VERSION 5.8 ;
BUSBITCHARS "[]" ;
DIVIDERCHAR "/" ;
UNITS
    DATABASE MICRONS 1000 ;
END UNITS

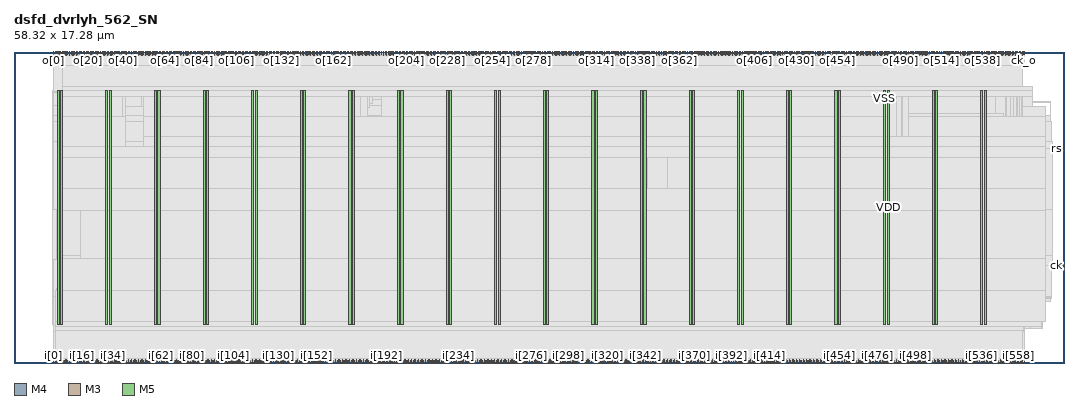
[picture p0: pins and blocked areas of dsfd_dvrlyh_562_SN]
MACRO dsfd_dvrlyh_562_SN
  FOREIGN dsfd_dvrlyh_562_SN 0 0 ;
  CLASS BLOCK ;
  SIZE 58.32 BY 17.28 ;
  PIN ck
    DIRECTION INPUT ;
    USE SIGNAL ;
    PORT
      LAYER M4 ;
        RECT  58.128 5.424 58.32 5.448 ;
    END
  END ck
  PIN ck_o
    DIRECTION OUTPUT ;
    USE SIGNAL ;
    PORT
      LAYER M3 ;
        RECT  56.088 17.136 56.106 17.28 ;
    END
  END ck_o
  PIN i[0]
    DIRECTION INPUT ;
    USE SIGNAL ;
    PORT
      LAYER M3 ;
        RECT  2.196 0 2.214 0.144 ;
    END
  END i[0]
  PIN i[100]
    DIRECTION INPUT ;
    USE SIGNAL ;
    PORT
      LAYER M3 ;
        RECT  11.808 0 11.826 0.144 ;
    END
  END i[100]
  PIN i[101]
    DIRECTION INPUT ;
    USE SIGNAL ;
    PORT
      LAYER M5 ;
        RECT  11.904 0 11.928 0.192 ;
    END
  END i[101]
  PIN i[102]
    DIRECTION INPUT ;
    USE SIGNAL ;
    PORT
      LAYER M3 ;
        RECT  11.988 0 12.006 0.144 ;
    END
  END i[102]
  PIN i[103]
    DIRECTION INPUT ;
    USE SIGNAL ;
    PORT
      LAYER M5 ;
        RECT  12.096 0 12.12 0.192 ;
    END
  END i[103]
  PIN i[104]
    DIRECTION INPUT ;
    USE SIGNAL ;
    PORT
      LAYER M3 ;
        RECT  12.204 0 12.222 0.144 ;
    END
  END i[104]
  PIN i[105]
    DIRECTION INPUT ;
    USE SIGNAL ;
    PORT
      LAYER M5 ;
        RECT  12.288 0 12.312 0.192 ;
    END
  END i[105]
  PIN i[106]
    DIRECTION INPUT ;
    USE SIGNAL ;
    PORT
      LAYER M3 ;
        RECT  12.384 0 12.402 0.144 ;
    END
  END i[106]
  PIN i[107]
    DIRECTION INPUT ;
    USE SIGNAL ;
    PORT
      LAYER M5 ;
        RECT  12.48 0 12.504 0.192 ;
    END
  END i[107]
  PIN i[108]
    DIRECTION INPUT ;
    USE SIGNAL ;
    PORT
      LAYER M3 ;
        RECT  12.564 0 12.582 0.144 ;
    END
  END i[108]
  PIN i[109]
    DIRECTION INPUT ;
    USE SIGNAL ;
    PORT
      LAYER M5 ;
        RECT  12.672 0 12.696 0.192 ;
    END
  END i[109]
  PIN i[10]
    DIRECTION INPUT ;
    USE SIGNAL ;
    PORT
      LAYER M3 ;
        RECT  3.168 0 3.186 0.144 ;
    END
  END i[10]
  PIN i[110]
    DIRECTION INPUT ;
    USE SIGNAL ;
    PORT
      LAYER M3 ;
        RECT  12.78 0 12.798 0.144 ;
    END
  END i[110]
  PIN i[111]
    DIRECTION INPUT ;
    USE SIGNAL ;
    PORT
      LAYER M5 ;
        RECT  12.864 0 12.888 0.192 ;
    END
  END i[111]
  PIN i[112]
    DIRECTION INPUT ;
    USE SIGNAL ;
    PORT
      LAYER M3 ;
        RECT  12.96 0 12.978 0.144 ;
    END
  END i[112]
  PIN i[113]
    DIRECTION INPUT ;
    USE SIGNAL ;
    PORT
      LAYER M5 ;
        RECT  13.056 0 13.08 0.192 ;
    END
  END i[113]
  PIN i[114]
    DIRECTION INPUT ;
    USE SIGNAL ;
    PORT
      LAYER M3 ;
        RECT  13.14 0 13.158 0.144 ;
    END
  END i[114]
  PIN i[115]
    DIRECTION INPUT ;
    USE SIGNAL ;
    PORT
      LAYER M5 ;
        RECT  13.248 0 13.272 0.192 ;
    END
  END i[115]
  PIN i[116]
    DIRECTION INPUT ;
    USE SIGNAL ;
    PORT
      LAYER M3 ;
        RECT  13.356 0 13.374 0.144 ;
    END
  END i[116]
  PIN i[117]
    DIRECTION INPUT ;
    USE SIGNAL ;
    PORT
      LAYER M5 ;
        RECT  13.44 0 13.464 0.192 ;
    END
  END i[117]
  PIN i[118]
    DIRECTION INPUT ;
    USE SIGNAL ;
    PORT
      LAYER M3 ;
        RECT  13.536 0 13.554 0.144 ;
    END
  END i[118]
  PIN i[119]
    DIRECTION INPUT ;
    USE SIGNAL ;
    PORT
      LAYER M5 ;
        RECT  13.632 0 13.656 0.192 ;
    END
  END i[119]
  PIN i[11]
    DIRECTION INPUT ;
    USE SIGNAL ;
    PORT
      LAYER M5 ;
        RECT  3.264 0 3.288 0.192 ;
    END
  END i[11]
  PIN i[120]
    DIRECTION INPUT ;
    USE SIGNAL ;
    PORT
      LAYER M3 ;
        RECT  13.716 0 13.734 0.144 ;
    END
  END i[120]
  PIN i[121]
    DIRECTION INPUT ;
    USE SIGNAL ;
    PORT
      LAYER M5 ;
        RECT  13.824 0 13.848 0.192 ;
    END
  END i[121]
  PIN i[122]
    DIRECTION INPUT ;
    USE SIGNAL ;
    PORT
      LAYER M3 ;
        RECT  13.932 0 13.95 0.144 ;
    END
  END i[122]
  PIN i[123]
    DIRECTION INPUT ;
    USE SIGNAL ;
    PORT
      LAYER M5 ;
        RECT  14.016 0 14.04 0.192 ;
    END
  END i[123]
  PIN i[124]
    DIRECTION INPUT ;
    USE SIGNAL ;
    PORT
      LAYER M3 ;
        RECT  14.112 0 14.13 0.144 ;
    END
  END i[124]
  PIN i[125]
    DIRECTION INPUT ;
    USE SIGNAL ;
    PORT
      LAYER M5 ;
        RECT  14.208 0 14.232 0.192 ;
    END
  END i[125]
  PIN i[126]
    DIRECTION INPUT ;
    USE SIGNAL ;
    PORT
      LAYER M3 ;
        RECT  14.292 0 14.31 0.144 ;
    END
  END i[126]
  PIN i[127]
    DIRECTION INPUT ;
    USE SIGNAL ;
    PORT
      LAYER M5 ;
        RECT  14.4 0 14.424 0.192 ;
    END
  END i[127]
  PIN i[128]
    DIRECTION INPUT ;
    USE SIGNAL ;
    PORT
      LAYER M3 ;
        RECT  14.508 0 14.526 0.144 ;
    END
  END i[128]
  PIN i[129]
    DIRECTION INPUT ;
    USE SIGNAL ;
    PORT
      LAYER M5 ;
        RECT  14.592 0 14.616 0.192 ;
    END
  END i[129]
  PIN i[12]
    DIRECTION INPUT ;
    USE SIGNAL ;
    PORT
      LAYER M3 ;
        RECT  3.348 0 3.366 0.144 ;
    END
  END i[12]
  PIN i[130]
    DIRECTION INPUT ;
    USE SIGNAL ;
    PORT
      LAYER M3 ;
        RECT  14.688 0 14.706 0.144 ;
    END
  END i[130]
  PIN i[131]
    DIRECTION INPUT ;
    USE SIGNAL ;
    PORT
      LAYER M5 ;
        RECT  14.784 0 14.808 0.192 ;
    END
  END i[131]
  PIN i[132]
    DIRECTION INPUT ;
    USE SIGNAL ;
    PORT
      LAYER M3 ;
        RECT  14.868 0 14.886 0.144 ;
    END
  END i[132]
  PIN i[133]
    DIRECTION INPUT ;
    USE SIGNAL ;
    PORT
      LAYER M5 ;
        RECT  14.976 0 15 0.192 ;
    END
  END i[133]
  PIN i[134]
    DIRECTION INPUT ;
    USE SIGNAL ;
    PORT
      LAYER M3 ;
        RECT  15.084 0 15.102 0.144 ;
    END
  END i[134]
  PIN i[135]
    DIRECTION INPUT ;
    USE SIGNAL ;
    PORT
      LAYER M5 ;
        RECT  15.168 0 15.192 0.192 ;
    END
  END i[135]
  PIN i[136]
    DIRECTION INPUT ;
    USE SIGNAL ;
    PORT
      LAYER M3 ;
        RECT  15.264 0 15.282 0.144 ;
    END
  END i[136]
  PIN i[137]
    DIRECTION INPUT ;
    USE SIGNAL ;
    PORT
      LAYER M5 ;
        RECT  15.36 0 15.384 0.192 ;
    END
  END i[137]
  PIN i[138]
    DIRECTION INPUT ;
    USE SIGNAL ;
    PORT
      LAYER M3 ;
        RECT  15.444 0 15.462 0.144 ;
    END
  END i[138]
  PIN i[139]
    DIRECTION INPUT ;
    USE SIGNAL ;
    PORT
      LAYER M5 ;
        RECT  15.552 0 15.576 0.192 ;
    END
  END i[139]
  PIN i[13]
    DIRECTION INPUT ;
    USE SIGNAL ;
    PORT
      LAYER M5 ;
        RECT  3.456 0 3.48 0.192 ;
    END
  END i[13]
  PIN i[140]
    DIRECTION INPUT ;
    USE SIGNAL ;
    PORT
      LAYER M3 ;
        RECT  15.66 0 15.678 0.144 ;
    END
  END i[140]
  PIN i[141]
    DIRECTION INPUT ;
    USE SIGNAL ;
    PORT
      LAYER M5 ;
        RECT  15.744 0 15.768 0.192 ;
    END
  END i[141]
  PIN i[142]
    DIRECTION INPUT ;
    USE SIGNAL ;
    PORT
      LAYER M3 ;
        RECT  15.84 0 15.858 0.144 ;
    END
  END i[142]
  PIN i[143]
    DIRECTION INPUT ;
    USE SIGNAL ;
    PORT
      LAYER M5 ;
        RECT  15.936 0 15.96 0.192 ;
    END
  END i[143]
  PIN i[144]
    DIRECTION INPUT ;
    USE SIGNAL ;
    PORT
      LAYER M3 ;
        RECT  16.02 0 16.038 0.144 ;
    END
  END i[144]
  PIN i[145]
    DIRECTION INPUT ;
    USE SIGNAL ;
    PORT
      LAYER M5 ;
        RECT  16.128 0 16.152 0.192 ;
    END
  END i[145]
  PIN i[146]
    DIRECTION INPUT ;
    USE SIGNAL ;
    PORT
      LAYER M3 ;
        RECT  16.236 0 16.254 0.144 ;
    END
  END i[146]
  PIN i[147]
    DIRECTION INPUT ;
    USE SIGNAL ;
    PORT
      LAYER M5 ;
        RECT  16.32 0 16.344 0.192 ;
    END
  END i[147]
  PIN i[148]
    DIRECTION INPUT ;
    USE SIGNAL ;
    PORT
      LAYER M3 ;
        RECT  16.416 0 16.434 0.144 ;
    END
  END i[148]
  PIN i[149]
    DIRECTION INPUT ;
    USE SIGNAL ;
    PORT
      LAYER M5 ;
        RECT  16.512 0 16.536 0.192 ;
    END
  END i[149]
  PIN i[14]
    DIRECTION INPUT ;
    USE SIGNAL ;
    PORT
      LAYER M3 ;
        RECT  3.528 0 3.546 0.144 ;
    END
  END i[14]
  PIN i[150]
    DIRECTION INPUT ;
    USE SIGNAL ;
    PORT
      LAYER M3 ;
        RECT  16.596 0 16.614 0.144 ;
    END
  END i[150]
  PIN i[151]
    DIRECTION INPUT ;
    USE SIGNAL ;
    PORT
      LAYER M5 ;
        RECT  16.704 0 16.728 0.192 ;
    END
  END i[151]
  PIN i[152]
    DIRECTION INPUT ;
    USE SIGNAL ;
    PORT
      LAYER M3 ;
        RECT  16.812 0 16.83 0.144 ;
    END
  END i[152]
  PIN i[153]
    DIRECTION INPUT ;
    USE SIGNAL ;
    PORT
      LAYER M5 ;
        RECT  16.896 0 16.92 0.192 ;
    END
  END i[153]
  PIN i[154]
    DIRECTION INPUT ;
    USE SIGNAL ;
    PORT
      LAYER M3 ;
        RECT  16.992 0 17.01 0.144 ;
    END
  END i[154]
  PIN i[155]
    DIRECTION INPUT ;
    USE SIGNAL ;
    PORT
      LAYER M5 ;
        RECT  17.088 0 17.112 0.192 ;
    END
  END i[155]
  PIN i[156]
    DIRECTION INPUT ;
    USE SIGNAL ;
    PORT
      LAYER M3 ;
        RECT  17.172 0 17.19 0.144 ;
    END
  END i[156]
  PIN i[157]
    DIRECTION INPUT ;
    USE SIGNAL ;
    PORT
      LAYER M5 ;
        RECT  17.28 0 17.304 0.192 ;
    END
  END i[157]
  PIN i[158]
    DIRECTION INPUT ;
    USE SIGNAL ;
    PORT
      LAYER M3 ;
        RECT  17.388 0 17.406 0.144 ;
    END
  END i[158]
  PIN i[159]
    DIRECTION INPUT ;
    USE SIGNAL ;
    PORT
      LAYER M5 ;
        RECT  17.472 0 17.496 0.192 ;
    END
  END i[159]
  PIN i[15]
    DIRECTION INPUT ;
    USE SIGNAL ;
    PORT
      LAYER M5 ;
        RECT  3.648 0 3.672 0.192 ;
    END
  END i[15]
  PIN i[160]
    DIRECTION INPUT ;
    USE SIGNAL ;
    PORT
      LAYER M3 ;
        RECT  17.568 0 17.586 0.144 ;
    END
  END i[160]
  PIN i[161]
    DIRECTION INPUT ;
    USE SIGNAL ;
    PORT
      LAYER M5 ;
        RECT  17.664 0 17.688 0.192 ;
    END
  END i[161]
  PIN i[162]
    DIRECTION INPUT ;
    USE SIGNAL ;
    PORT
      LAYER M3 ;
        RECT  17.748 0 17.766 0.144 ;
    END
  END i[162]
  PIN i[163]
    DIRECTION INPUT ;
    USE SIGNAL ;
    PORT
      LAYER M5 ;
        RECT  17.856 0 17.88 0.192 ;
    END
  END i[163]
  PIN i[164]
    DIRECTION INPUT ;
    USE SIGNAL ;
    PORT
      LAYER M3 ;
        RECT  17.964 0 17.982 0.144 ;
    END
  END i[164]
  PIN i[165]
    DIRECTION INPUT ;
    USE SIGNAL ;
    PORT
      LAYER M5 ;
        RECT  18.048 0 18.072 0.192 ;
    END
  END i[165]
  PIN i[166]
    DIRECTION INPUT ;
    USE SIGNAL ;
    PORT
      LAYER M3 ;
        RECT  18.144 0 18.162 0.144 ;
    END
  END i[166]
  PIN i[167]
    DIRECTION INPUT ;
    USE SIGNAL ;
    PORT
      LAYER M5 ;
        RECT  18.24 0 18.264 0.192 ;
    END
  END i[167]
  PIN i[168]
    DIRECTION INPUT ;
    USE SIGNAL ;
    PORT
      LAYER M3 ;
        RECT  18.324 0 18.342 0.144 ;
    END
  END i[168]
  PIN i[169]
    DIRECTION INPUT ;
    USE SIGNAL ;
    PORT
      LAYER M5 ;
        RECT  18.432 0 18.456 0.192 ;
    END
  END i[169]
  PIN i[16]
    DIRECTION INPUT ;
    USE SIGNAL ;
    PORT
      LAYER M3 ;
        RECT  3.744 0 3.762 0.144 ;
    END
  END i[16]
  PIN i[170]
    DIRECTION INPUT ;
    USE SIGNAL ;
    PORT
      LAYER M3 ;
        RECT  18.54 0 18.558 0.144 ;
    END
  END i[170]
  PIN i[171]
    DIRECTION INPUT ;
    USE SIGNAL ;
    PORT
      LAYER M5 ;
        RECT  18.624 0 18.648 0.192 ;
    END
  END i[171]
  PIN i[172]
    DIRECTION INPUT ;
    USE SIGNAL ;
    PORT
      LAYER M3 ;
        RECT  18.72 0 18.738 0.144 ;
    END
  END i[172]
  PIN i[173]
    DIRECTION INPUT ;
    USE SIGNAL ;
    PORT
      LAYER M5 ;
        RECT  18.816 0 18.84 0.192 ;
    END
  END i[173]
  PIN i[174]
    DIRECTION INPUT ;
    USE SIGNAL ;
    PORT
      LAYER M3 ;
        RECT  18.9 0 18.918 0.144 ;
    END
  END i[174]
  PIN i[175]
    DIRECTION INPUT ;
    USE SIGNAL ;
    PORT
      LAYER M5 ;
        RECT  19.008 0 19.032 0.192 ;
    END
  END i[175]
  PIN i[176]
    DIRECTION INPUT ;
    USE SIGNAL ;
    PORT
      LAYER M3 ;
        RECT  19.116 0 19.134 0.144 ;
    END
  END i[176]
  PIN i[177]
    DIRECTION INPUT ;
    USE SIGNAL ;
    PORT
      LAYER M5 ;
        RECT  19.2 0 19.224 0.192 ;
    END
  END i[177]
  PIN i[178]
    DIRECTION INPUT ;
    USE SIGNAL ;
    PORT
      LAYER M3 ;
        RECT  19.296 0 19.314 0.144 ;
    END
  END i[178]
  PIN i[179]
    DIRECTION INPUT ;
    USE SIGNAL ;
    PORT
      LAYER M5 ;
        RECT  19.392 0 19.416 0.192 ;
    END
  END i[179]
  PIN i[17]
    DIRECTION INPUT ;
    USE SIGNAL ;
    PORT
      LAYER M5 ;
        RECT  3.84 0 3.864 0.192 ;
    END
  END i[17]
  PIN i[180]
    DIRECTION INPUT ;
    USE SIGNAL ;
    PORT
      LAYER M3 ;
        RECT  19.512 0 19.53 0.144 ;
    END
  END i[180]
  PIN i[181]
    DIRECTION INPUT ;
    USE SIGNAL ;
    PORT
      LAYER M5 ;
        RECT  19.584 0 19.608 0.192 ;
    END
  END i[181]
  PIN i[182]
    DIRECTION INPUT ;
    USE SIGNAL ;
    PORT
      LAYER M3 ;
        RECT  19.692 0 19.71 0.144 ;
    END
  END i[182]
  PIN i[183]
    DIRECTION INPUT ;
    USE SIGNAL ;
    PORT
      LAYER M5 ;
        RECT  19.776 0 19.8 0.192 ;
    END
  END i[183]
  PIN i[184]
    DIRECTION INPUT ;
    USE SIGNAL ;
    PORT
      LAYER M3 ;
        RECT  19.872 0 19.89 0.144 ;
    END
  END i[184]
  PIN i[185]
    DIRECTION INPUT ;
    USE SIGNAL ;
    PORT
      LAYER M5 ;
        RECT  19.968 0 19.992 0.192 ;
    END
  END i[185]
  PIN i[186]
    DIRECTION INPUT ;
    USE SIGNAL ;
    PORT
      LAYER M3 ;
        RECT  20.088 0 20.106 0.144 ;
    END
  END i[186]
  PIN i[187]
    DIRECTION INPUT ;
    USE SIGNAL ;
    PORT
      LAYER M5 ;
        RECT  20.16 0 20.184 0.192 ;
    END
  END i[187]
  PIN i[188]
    DIRECTION INPUT ;
    USE SIGNAL ;
    PORT
      LAYER M3 ;
        RECT  20.268 0 20.286 0.144 ;
    END
  END i[188]
  PIN i[189]
    DIRECTION INPUT ;
    USE SIGNAL ;
    PORT
      LAYER M5 ;
        RECT  20.352 0 20.376 0.192 ;
    END
  END i[189]
  PIN i[18]
    DIRECTION INPUT ;
    USE SIGNAL ;
    PORT
      LAYER M3 ;
        RECT  3.924 0 3.942 0.144 ;
    END
  END i[18]
  PIN i[190]
    DIRECTION INPUT ;
    USE SIGNAL ;
    PORT
      LAYER M3 ;
        RECT  20.448 0 20.466 0.144 ;
    END
  END i[190]
  PIN i[191]
    DIRECTION INPUT ;
    USE SIGNAL ;
    PORT
      LAYER M5 ;
        RECT  20.544 0 20.568 0.192 ;
    END
  END i[191]
  PIN i[192]
    DIRECTION INPUT ;
    USE SIGNAL ;
    PORT
      LAYER M3 ;
        RECT  20.664 0 20.682 0.144 ;
    END
  END i[192]
  PIN i[193]
    DIRECTION INPUT ;
    USE SIGNAL ;
    PORT
      LAYER M5 ;
        RECT  20.736 0 20.76 0.192 ;
    END
  END i[193]
  PIN i[194]
    DIRECTION INPUT ;
    USE SIGNAL ;
    PORT
      LAYER M3 ;
        RECT  20.844 0 20.862 0.144 ;
    END
  END i[194]
  PIN i[195]
    DIRECTION INPUT ;
    USE SIGNAL ;
    PORT
      LAYER M5 ;
        RECT  20.928 0 20.952 0.192 ;
    END
  END i[195]
  PIN i[196]
    DIRECTION INPUT ;
    USE SIGNAL ;
    PORT
      LAYER M3 ;
        RECT  21.024 0 21.042 0.144 ;
    END
  END i[196]
  PIN i[197]
    DIRECTION INPUT ;
    USE SIGNAL ;
    PORT
      LAYER M5 ;
        RECT  21.12 0 21.144 0.192 ;
    END
  END i[197]
  PIN i[198]
    DIRECTION INPUT ;
    USE SIGNAL ;
    PORT
      LAYER M3 ;
        RECT  21.24 0 21.258 0.144 ;
    END
  END i[198]
  PIN i[199]
    DIRECTION INPUT ;
    USE SIGNAL ;
    PORT
      LAYER M5 ;
        RECT  21.312 0 21.336 0.192 ;
    END
  END i[199]
  PIN i[19]
    DIRECTION INPUT ;
    USE SIGNAL ;
    PORT
      LAYER M5 ;
        RECT  4.032 0 4.056 0.192 ;
    END
  END i[19]
  PIN i[1]
    DIRECTION INPUT ;
    USE SIGNAL ;
    PORT
      LAYER M5 ;
        RECT  2.304 0 2.328 0.192 ;
    END
  END i[1]
  PIN i[200]
    DIRECTION INPUT ;
    USE SIGNAL ;
    PORT
      LAYER M3 ;
        RECT  21.42 0 21.438 0.144 ;
    END
  END i[200]
  PIN i[201]
    DIRECTION INPUT ;
    USE SIGNAL ;
    PORT
      LAYER M5 ;
        RECT  21.504 0 21.528 0.192 ;
    END
  END i[201]
  PIN i[202]
    DIRECTION INPUT ;
    USE SIGNAL ;
    PORT
      LAYER M3 ;
        RECT  21.6 0 21.618 0.144 ;
    END
  END i[202]
  PIN i[203]
    DIRECTION INPUT ;
    USE SIGNAL ;
    PORT
      LAYER M5 ;
        RECT  21.696 0 21.72 0.192 ;
    END
  END i[203]
  PIN i[204]
    DIRECTION INPUT ;
    USE SIGNAL ;
    PORT
      LAYER M3 ;
        RECT  21.816 0 21.834 0.144 ;
    END
  END i[204]
  PIN i[205]
    DIRECTION INPUT ;
    USE SIGNAL ;
    PORT
      LAYER M5 ;
        RECT  21.888 0 21.912 0.192 ;
    END
  END i[205]
  PIN i[206]
    DIRECTION INPUT ;
    USE SIGNAL ;
    PORT
      LAYER M3 ;
        RECT  21.996 0 22.014 0.144 ;
    END
  END i[206]
  PIN i[207]
    DIRECTION INPUT ;
    USE SIGNAL ;
    PORT
      LAYER M5 ;
        RECT  22.08 0 22.104 0.192 ;
    END
  END i[207]
  PIN i[208]
    DIRECTION INPUT ;
    USE SIGNAL ;
    PORT
      LAYER M3 ;
        RECT  22.176 0 22.194 0.144 ;
    END
  END i[208]
  PIN i[209]
    DIRECTION INPUT ;
    USE SIGNAL ;
    PORT
      LAYER M5 ;
        RECT  22.272 0 22.296 0.192 ;
    END
  END i[209]
  PIN i[20]
    DIRECTION INPUT ;
    USE SIGNAL ;
    PORT
      LAYER M3 ;
        RECT  4.104 0 4.122 0.144 ;
    END
  END i[20]
  PIN i[210]
    DIRECTION INPUT ;
    USE SIGNAL ;
    PORT
      LAYER M3 ;
        RECT  22.392 0 22.41 0.144 ;
    END
  END i[210]
  PIN i[211]
    DIRECTION INPUT ;
    USE SIGNAL ;
    PORT
      LAYER M5 ;
        RECT  22.464 0 22.488 0.192 ;
    END
  END i[211]
  PIN i[212]
    DIRECTION INPUT ;
    USE SIGNAL ;
    PORT
      LAYER M3 ;
        RECT  22.572 0 22.59 0.144 ;
    END
  END i[212]
  PIN i[213]
    DIRECTION INPUT ;
    USE SIGNAL ;
    PORT
      LAYER M5 ;
        RECT  22.656 0 22.68 0.192 ;
    END
  END i[213]
  PIN i[214]
    DIRECTION INPUT ;
    USE SIGNAL ;
    PORT
      LAYER M3 ;
        RECT  22.752 0 22.77 0.144 ;
    END
  END i[214]
  PIN i[215]
    DIRECTION INPUT ;
    USE SIGNAL ;
    PORT
      LAYER M5 ;
        RECT  22.848 0 22.872 0.192 ;
    END
  END i[215]
  PIN i[216]
    DIRECTION INPUT ;
    USE SIGNAL ;
    PORT
      LAYER M3 ;
        RECT  22.968 0 22.986 0.144 ;
    END
  END i[216]
  PIN i[217]
    DIRECTION INPUT ;
    USE SIGNAL ;
    PORT
      LAYER M5 ;
        RECT  23.04 0 23.064 0.192 ;
    END
  END i[217]
  PIN i[218]
    DIRECTION INPUT ;
    USE SIGNAL ;
    PORT
      LAYER M3 ;
        RECT  23.148 0 23.166 0.144 ;
    END
  END i[218]
  PIN i[219]
    DIRECTION INPUT ;
    USE SIGNAL ;
    PORT
      LAYER M5 ;
        RECT  23.232 0 23.256 0.192 ;
    END
  END i[219]
  PIN i[21]
    DIRECTION INPUT ;
    USE SIGNAL ;
    PORT
      LAYER M5 ;
        RECT  4.224 0 4.248 0.192 ;
    END
  END i[21]
  PIN i[220]
    DIRECTION INPUT ;
    USE SIGNAL ;
    PORT
      LAYER M3 ;
        RECT  23.328 0 23.346 0.144 ;
    END
  END i[220]
  PIN i[221]
    DIRECTION INPUT ;
    USE SIGNAL ;
    PORT
      LAYER M5 ;
        RECT  23.424 0 23.448 0.192 ;
    END
  END i[221]
  PIN i[222]
    DIRECTION INPUT ;
    USE SIGNAL ;
    PORT
      LAYER M3 ;
        RECT  23.544 0 23.562 0.144 ;
    END
  END i[222]
  PIN i[223]
    DIRECTION INPUT ;
    USE SIGNAL ;
    PORT
      LAYER M5 ;
        RECT  23.616 0 23.64 0.192 ;
    END
  END i[223]
  PIN i[224]
    DIRECTION INPUT ;
    USE SIGNAL ;
    PORT
      LAYER M3 ;
        RECT  23.724 0 23.742 0.144 ;
    END
  END i[224]
  PIN i[225]
    DIRECTION INPUT ;
    USE SIGNAL ;
    PORT
      LAYER M5 ;
        RECT  23.808 0 23.832 0.192 ;
    END
  END i[225]
  PIN i[226]
    DIRECTION INPUT ;
    USE SIGNAL ;
    PORT
      LAYER M3 ;
        RECT  23.904 0 23.922 0.144 ;
    END
  END i[226]
  PIN i[227]
    DIRECTION INPUT ;
    USE SIGNAL ;
    PORT
      LAYER M5 ;
        RECT  24 0 24.024 0.192 ;
    END
  END i[227]
  PIN i[228]
    DIRECTION INPUT ;
    USE SIGNAL ;
    PORT
      LAYER M3 ;
        RECT  24.12 0 24.138 0.144 ;
    END
  END i[228]
  PIN i[229]
    DIRECTION INPUT ;
    USE SIGNAL ;
    PORT
      LAYER M5 ;
        RECT  24.192 0 24.216 0.192 ;
    END
  END i[229]
  PIN i[22]
    DIRECTION INPUT ;
    USE SIGNAL ;
    PORT
      LAYER M3 ;
        RECT  4.32 0 4.338 0.144 ;
    END
  END i[22]
  PIN i[230]
    DIRECTION INPUT ;
    USE SIGNAL ;
    PORT
      LAYER M3 ;
        RECT  24.3 0 24.318 0.144 ;
    END
  END i[230]
  PIN i[231]
    DIRECTION INPUT ;
    USE SIGNAL ;
    PORT
      LAYER M5 ;
        RECT  24.384 0 24.408 0.192 ;
    END
  END i[231]
  PIN i[232]
    DIRECTION INPUT ;
    USE SIGNAL ;
    PORT
      LAYER M3 ;
        RECT  24.48 0 24.498 0.144 ;
    END
  END i[232]
  PIN i[233]
    DIRECTION INPUT ;
    USE SIGNAL ;
    PORT
      LAYER M5 ;
        RECT  24.576 0 24.6 0.192 ;
    END
  END i[233]
  PIN i[234]
    DIRECTION INPUT ;
    USE SIGNAL ;
    PORT
      LAYER M3 ;
        RECT  24.696 0 24.714 0.144 ;
    END
  END i[234]
  PIN i[235]
    DIRECTION INPUT ;
    USE SIGNAL ;
    PORT
      LAYER M5 ;
        RECT  24.768 0 24.792 0.192 ;
    END
  END i[235]
  PIN i[236]
    DIRECTION INPUT ;
    USE SIGNAL ;
    PORT
      LAYER M3 ;
        RECT  24.876 0 24.894 0.144 ;
    END
  END i[236]
  PIN i[237]
    DIRECTION INPUT ;
    USE SIGNAL ;
    PORT
      LAYER M5 ;
        RECT  24.96 0 24.984 0.192 ;
    END
  END i[237]
  PIN i[238]
    DIRECTION INPUT ;
    USE SIGNAL ;
    PORT
      LAYER M3 ;
        RECT  25.056 0 25.074 0.144 ;
    END
  END i[238]
  PIN i[239]
    DIRECTION INPUT ;
    USE SIGNAL ;
    PORT
      LAYER M5 ;
        RECT  25.152 0 25.176 0.192 ;
    END
  END i[239]
  PIN i[23]
    DIRECTION INPUT ;
    USE SIGNAL ;
    PORT
      LAYER M5 ;
        RECT  4.416 0 4.44 0.192 ;
    END
  END i[23]
  PIN i[240]
    DIRECTION INPUT ;
    USE SIGNAL ;
    PORT
      LAYER M3 ;
        RECT  25.272 0 25.29 0.144 ;
    END
  END i[240]
  PIN i[241]
    DIRECTION INPUT ;
    USE SIGNAL ;
    PORT
      LAYER M5 ;
        RECT  25.344 0 25.368 0.192 ;
    END
  END i[241]
  PIN i[242]
    DIRECTION INPUT ;
    USE SIGNAL ;
    PORT
      LAYER M3 ;
        RECT  25.452 0 25.47 0.144 ;
    END
  END i[242]
  PIN i[243]
    DIRECTION INPUT ;
    USE SIGNAL ;
    PORT
      LAYER M5 ;
        RECT  25.536 0 25.56 0.192 ;
    END
  END i[243]
  PIN i[244]
    DIRECTION INPUT ;
    USE SIGNAL ;
    PORT
      LAYER M3 ;
        RECT  25.632 0 25.65 0.144 ;
    END
  END i[244]
  PIN i[245]
    DIRECTION INPUT ;
    USE SIGNAL ;
    PORT
      LAYER M5 ;
        RECT  25.728 0 25.752 0.192 ;
    END
  END i[245]
  PIN i[246]
    DIRECTION INPUT ;
    USE SIGNAL ;
    PORT
      LAYER M3 ;
        RECT  25.848 0 25.866 0.144 ;
    END
  END i[246]
  PIN i[247]
    DIRECTION INPUT ;
    USE SIGNAL ;
    PORT
      LAYER M5 ;
        RECT  25.92 0 25.944 0.192 ;
    END
  END i[247]
  PIN i[248]
    DIRECTION INPUT ;
    USE SIGNAL ;
    PORT
      LAYER M3 ;
        RECT  26.028 0 26.046 0.144 ;
    END
  END i[248]
  PIN i[249]
    DIRECTION INPUT ;
    USE SIGNAL ;
    PORT
      LAYER M5 ;
        RECT  26.112 0 26.136 0.192 ;
    END
  END i[249]
  PIN i[24]
    DIRECTION INPUT ;
    USE SIGNAL ;
    PORT
      LAYER M3 ;
        RECT  4.5 0 4.518 0.144 ;
    END
  END i[24]
  PIN i[250]
    DIRECTION INPUT ;
    USE SIGNAL ;
    PORT
      LAYER M3 ;
        RECT  26.208 0 26.226 0.144 ;
    END
  END i[250]
  PIN i[251]
    DIRECTION INPUT ;
    USE SIGNAL ;
    PORT
      LAYER M5 ;
        RECT  26.304 0 26.328 0.192 ;
    END
  END i[251]
  PIN i[252]
    DIRECTION INPUT ;
    USE SIGNAL ;
    PORT
      LAYER M3 ;
        RECT  26.424 0 26.442 0.144 ;
    END
  END i[252]
  PIN i[253]
    DIRECTION INPUT ;
    USE SIGNAL ;
    PORT
      LAYER M5 ;
        RECT  26.496 0 26.52 0.192 ;
    END
  END i[253]
  PIN i[254]
    DIRECTION INPUT ;
    USE SIGNAL ;
    PORT
      LAYER M3 ;
        RECT  26.604 0 26.622 0.144 ;
    END
  END i[254]
  PIN i[255]
    DIRECTION INPUT ;
    USE SIGNAL ;
    PORT
      LAYER M5 ;
        RECT  26.688 0 26.712 0.192 ;
    END
  END i[255]
  PIN i[256]
    DIRECTION INPUT ;
    USE SIGNAL ;
    PORT
      LAYER M3 ;
        RECT  26.784 0 26.802 0.144 ;
    END
  END i[256]
  PIN i[257]
    DIRECTION INPUT ;
    USE SIGNAL ;
    PORT
      LAYER M5 ;
        RECT  26.88 0 26.904 0.192 ;
    END
  END i[257]
  PIN i[258]
    DIRECTION INPUT ;
    USE SIGNAL ;
    PORT
      LAYER M3 ;
        RECT  27 0 27.018 0.144 ;
    END
  END i[258]
  PIN i[259]
    DIRECTION INPUT ;
    USE SIGNAL ;
    PORT
      LAYER M5 ;
        RECT  27.072 0 27.096 0.192 ;
    END
  END i[259]
  PIN i[25]
    DIRECTION INPUT ;
    USE SIGNAL ;
    PORT
      LAYER M5 ;
        RECT  4.608 0 4.632 0.192 ;
    END
  END i[25]
  PIN i[260]
    DIRECTION INPUT ;
    USE SIGNAL ;
    PORT
      LAYER M3 ;
        RECT  27.18 0 27.198 0.144 ;
    END
  END i[260]
  PIN i[261]
    DIRECTION INPUT ;
    USE SIGNAL ;
    PORT
      LAYER M5 ;
        RECT  27.264 0 27.288 0.192 ;
    END
  END i[261]
  PIN i[262]
    DIRECTION INPUT ;
    USE SIGNAL ;
    PORT
      LAYER M3 ;
        RECT  27.36 0 27.378 0.144 ;
    END
  END i[262]
  PIN i[263]
    DIRECTION INPUT ;
    USE SIGNAL ;
    PORT
      LAYER M5 ;
        RECT  27.456 0 27.48 0.192 ;
    END
  END i[263]
  PIN i[264]
    DIRECTION INPUT ;
    USE SIGNAL ;
    PORT
      LAYER M3 ;
        RECT  27.576 0 27.594 0.144 ;
    END
  END i[264]
  PIN i[265]
    DIRECTION INPUT ;
    USE SIGNAL ;
    PORT
      LAYER M5 ;
        RECT  27.648 0 27.672 0.192 ;
    END
  END i[265]
  PIN i[266]
    DIRECTION INPUT ;
    USE SIGNAL ;
    PORT
      LAYER M3 ;
        RECT  27.756 0 27.774 0.144 ;
    END
  END i[266]
  PIN i[267]
    DIRECTION INPUT ;
    USE SIGNAL ;
    PORT
      LAYER M5 ;
        RECT  27.84 0 27.864 0.192 ;
    END
  END i[267]
  PIN i[268]
    DIRECTION INPUT ;
    USE SIGNAL ;
    PORT
      LAYER M3 ;
        RECT  27.936 0 27.954 0.144 ;
    END
  END i[268]
  PIN i[269]
    DIRECTION INPUT ;
    USE SIGNAL ;
    PORT
      LAYER M5 ;
        RECT  28.032 0 28.056 0.192 ;
    END
  END i[269]
  PIN i[26]
    DIRECTION INPUT ;
    USE SIGNAL ;
    PORT
      LAYER M3 ;
        RECT  4.68 0 4.698 0.144 ;
    END
  END i[26]
  PIN i[270]
    DIRECTION INPUT ;
    USE SIGNAL ;
    PORT
      LAYER M3 ;
        RECT  28.152 0 28.17 0.144 ;
    END
  END i[270]
  PIN i[271]
    DIRECTION INPUT ;
    USE SIGNAL ;
    PORT
      LAYER M5 ;
        RECT  28.224 0 28.248 0.192 ;
    END
  END i[271]
  PIN i[272]
    DIRECTION INPUT ;
    USE SIGNAL ;
    PORT
      LAYER M3 ;
        RECT  28.332 0 28.35 0.144 ;
    END
  END i[272]
  PIN i[273]
    DIRECTION INPUT ;
    USE SIGNAL ;
    PORT
      LAYER M5 ;
        RECT  28.416 0 28.44 0.192 ;
    END
  END i[273]
  PIN i[274]
    DIRECTION INPUT ;
    USE SIGNAL ;
    PORT
      LAYER M3 ;
        RECT  28.512 0 28.53 0.144 ;
    END
  END i[274]
  PIN i[275]
    DIRECTION INPUT ;
    USE SIGNAL ;
    PORT
      LAYER M5 ;
        RECT  28.608 0 28.632 0.192 ;
    END
  END i[275]
  PIN i[276]
    DIRECTION INPUT ;
    USE SIGNAL ;
    PORT
      LAYER M3 ;
        RECT  28.728 0 28.746 0.144 ;
    END
  END i[276]
  PIN i[277]
    DIRECTION INPUT ;
    USE SIGNAL ;
    PORT
      LAYER M5 ;
        RECT  28.8 0 28.824 0.192 ;
    END
  END i[277]
  PIN i[278]
    DIRECTION INPUT ;
    USE SIGNAL ;
    PORT
      LAYER M3 ;
        RECT  28.908 0 28.926 0.144 ;
    END
  END i[278]
  PIN i[279]
    DIRECTION INPUT ;
    USE SIGNAL ;
    PORT
      LAYER M5 ;
        RECT  28.992 0 29.016 0.192 ;
    END
  END i[279]
  PIN i[27]
    DIRECTION INPUT ;
    USE SIGNAL ;
    PORT
      LAYER M5 ;
        RECT  4.8 0 4.824 0.192 ;
    END
  END i[27]
  PIN i[280]
    DIRECTION INPUT ;
    USE SIGNAL ;
    PORT
      LAYER M3 ;
        RECT  29.088 0 29.106 0.144 ;
    END
  END i[280]
  PIN i[281]
    DIRECTION INPUT ;
    USE SIGNAL ;
    PORT
      LAYER M5 ;
        RECT  29.184 0 29.208 0.192 ;
    END
  END i[281]
  PIN i[282]
    DIRECTION INPUT ;
    USE SIGNAL ;
    PORT
      LAYER M3 ;
        RECT  29.304 0 29.322 0.144 ;
    END
  END i[282]
  PIN i[283]
    DIRECTION INPUT ;
    USE SIGNAL ;
    PORT
      LAYER M5 ;
        RECT  29.376 0 29.4 0.192 ;
    END
  END i[283]
  PIN i[284]
    DIRECTION INPUT ;
    USE SIGNAL ;
    PORT
      LAYER M3 ;
        RECT  29.484 0 29.502 0.144 ;
    END
  END i[284]
  PIN i[285]
    DIRECTION INPUT ;
    USE SIGNAL ;
    PORT
      LAYER M5 ;
        RECT  29.568 0 29.592 0.192 ;
    END
  END i[285]
  PIN i[286]
    DIRECTION INPUT ;
    USE SIGNAL ;
    PORT
      LAYER M3 ;
        RECT  29.664 0 29.682 0.144 ;
    END
  END i[286]
  PIN i[287]
    DIRECTION INPUT ;
    USE SIGNAL ;
    PORT
      LAYER M5 ;
        RECT  29.76 0 29.784 0.192 ;
    END
  END i[287]
  PIN i[288]
    DIRECTION INPUT ;
    USE SIGNAL ;
    PORT
      LAYER M3 ;
        RECT  29.88 0 29.898 0.144 ;
    END
  END i[288]
  PIN i[289]
    DIRECTION INPUT ;
    USE SIGNAL ;
    PORT
      LAYER M5 ;
        RECT  29.952 0 29.976 0.192 ;
    END
  END i[289]
  PIN i[28]
    DIRECTION INPUT ;
    USE SIGNAL ;
    PORT
      LAYER M3 ;
        RECT  4.896 0 4.914 0.144 ;
    END
  END i[28]
  PIN i[290]
    DIRECTION INPUT ;
    USE SIGNAL ;
    PORT
      LAYER M3 ;
        RECT  30.06 0 30.078 0.144 ;
    END
  END i[290]
  PIN i[291]
    DIRECTION INPUT ;
    USE SIGNAL ;
    PORT
      LAYER M5 ;
        RECT  30.144 0 30.168 0.192 ;
    END
  END i[291]
  PIN i[292]
    DIRECTION INPUT ;
    USE SIGNAL ;
    PORT
      LAYER M3 ;
        RECT  30.24 0 30.258 0.144 ;
    END
  END i[292]
  PIN i[293]
    DIRECTION INPUT ;
    USE SIGNAL ;
    PORT
      LAYER M5 ;
        RECT  30.336 0 30.36 0.192 ;
    END
  END i[293]
  PIN i[294]
    DIRECTION INPUT ;
    USE SIGNAL ;
    PORT
      LAYER M3 ;
        RECT  30.456 0 30.474 0.144 ;
    END
  END i[294]
  PIN i[295]
    DIRECTION INPUT ;
    USE SIGNAL ;
    PORT
      LAYER M5 ;
        RECT  30.528 0 30.552 0.192 ;
    END
  END i[295]
  PIN i[296]
    DIRECTION INPUT ;
    USE SIGNAL ;
    PORT
      LAYER M3 ;
        RECT  30.636 0 30.654 0.144 ;
    END
  END i[296]
  PIN i[297]
    DIRECTION INPUT ;
    USE SIGNAL ;
    PORT
      LAYER M5 ;
        RECT  30.72 0 30.744 0.192 ;
    END
  END i[297]
  PIN i[298]
    DIRECTION INPUT ;
    USE SIGNAL ;
    PORT
      LAYER M3 ;
        RECT  30.816 0 30.834 0.144 ;
    END
  END i[298]
  PIN i[299]
    DIRECTION INPUT ;
    USE SIGNAL ;
    PORT
      LAYER M5 ;
        RECT  30.912 0 30.936 0.192 ;
    END
  END i[299]
  PIN i[29]
    DIRECTION INPUT ;
    USE SIGNAL ;
    PORT
      LAYER M5 ;
        RECT  4.992 0 5.016 0.192 ;
    END
  END i[29]
  PIN i[2]
    DIRECTION INPUT ;
    USE SIGNAL ;
    PORT
      LAYER M3 ;
        RECT  2.376 0 2.394 0.144 ;
    END
  END i[2]
  PIN i[300]
    DIRECTION INPUT ;
    USE SIGNAL ;
    PORT
      LAYER M3 ;
        RECT  31.032 0 31.05 0.144 ;
    END
  END i[300]
  PIN i[301]
    DIRECTION INPUT ;
    USE SIGNAL ;
    PORT
      LAYER M5 ;
        RECT  31.104 0 31.128 0.192 ;
    END
  END i[301]
  PIN i[302]
    DIRECTION INPUT ;
    USE SIGNAL ;
    PORT
      LAYER M3 ;
        RECT  31.212 0 31.23 0.144 ;
    END
  END i[302]
  PIN i[303]
    DIRECTION INPUT ;
    USE SIGNAL ;
    PORT
      LAYER M5 ;
        RECT  31.296 0 31.32 0.192 ;
    END
  END i[303]
  PIN i[304]
    DIRECTION INPUT ;
    USE SIGNAL ;
    PORT
      LAYER M3 ;
        RECT  31.392 0 31.41 0.144 ;
    END
  END i[304]
  PIN i[305]
    DIRECTION INPUT ;
    USE SIGNAL ;
    PORT
      LAYER M5 ;
        RECT  31.488 0 31.512 0.192 ;
    END
  END i[305]
  PIN i[306]
    DIRECTION INPUT ;
    USE SIGNAL ;
    PORT
      LAYER M3 ;
        RECT  31.608 0 31.626 0.144 ;
    END
  END i[306]
  PIN i[307]
    DIRECTION INPUT ;
    USE SIGNAL ;
    PORT
      LAYER M5 ;
        RECT  31.68 0 31.704 0.192 ;
    END
  END i[307]
  PIN i[308]
    DIRECTION INPUT ;
    USE SIGNAL ;
    PORT
      LAYER M3 ;
        RECT  31.788 0 31.806 0.144 ;
    END
  END i[308]
  PIN i[309]
    DIRECTION INPUT ;
    USE SIGNAL ;
    PORT
      LAYER M5 ;
        RECT  31.872 0 31.896 0.192 ;
    END
  END i[309]
  PIN i[30]
    DIRECTION INPUT ;
    USE SIGNAL ;
    PORT
      LAYER M3 ;
        RECT  5.076 0 5.094 0.144 ;
    END
  END i[30]
  PIN i[310]
    DIRECTION INPUT ;
    USE SIGNAL ;
    PORT
      LAYER M3 ;
        RECT  31.968 0 31.986 0.144 ;
    END
  END i[310]
  PIN i[311]
    DIRECTION INPUT ;
    USE SIGNAL ;
    PORT
      LAYER M5 ;
        RECT  32.064 0 32.088 0.192 ;
    END
  END i[311]
  PIN i[312]
    DIRECTION INPUT ;
    USE SIGNAL ;
    PORT
      LAYER M3 ;
        RECT  32.184 0 32.202 0.144 ;
    END
  END i[312]
  PIN i[313]
    DIRECTION INPUT ;
    USE SIGNAL ;
    PORT
      LAYER M5 ;
        RECT  32.256 0 32.28 0.192 ;
    END
  END i[313]
  PIN i[314]
    DIRECTION INPUT ;
    USE SIGNAL ;
    PORT
      LAYER M3 ;
        RECT  32.364 0 32.382 0.144 ;
    END
  END i[314]
  PIN i[315]
    DIRECTION INPUT ;
    USE SIGNAL ;
    PORT
      LAYER M5 ;
        RECT  32.448 0 32.472 0.192 ;
    END
  END i[315]
  PIN i[316]
    DIRECTION INPUT ;
    USE SIGNAL ;
    PORT
      LAYER M3 ;
        RECT  32.58 0 32.598 0.144 ;
    END
  END i[316]
  PIN i[317]
    DIRECTION INPUT ;
    USE SIGNAL ;
    PORT
      LAYER M5 ;
        RECT  32.64 0 32.664 0.192 ;
    END
  END i[317]
  PIN i[318]
    DIRECTION INPUT ;
    USE SIGNAL ;
    PORT
      LAYER M3 ;
        RECT  32.76 0 32.778 0.144 ;
    END
  END i[318]
  PIN i[319]
    DIRECTION INPUT ;
    USE SIGNAL ;
    PORT
      LAYER M5 ;
        RECT  32.832 0 32.856 0.192 ;
    END
  END i[319]
  PIN i[31]
    DIRECTION INPUT ;
    USE SIGNAL ;
    PORT
      LAYER M5 ;
        RECT  5.184 0 5.208 0.192 ;
    END
  END i[31]
  PIN i[320]
    DIRECTION INPUT ;
    USE SIGNAL ;
    PORT
      LAYER M3 ;
        RECT  32.94 0 32.958 0.144 ;
    END
  END i[320]
  PIN i[321]
    DIRECTION INPUT ;
    USE SIGNAL ;
    PORT
      LAYER M5 ;
        RECT  33.024 0 33.048 0.192 ;
    END
  END i[321]
  PIN i[322]
    DIRECTION INPUT ;
    USE SIGNAL ;
    PORT
      LAYER M3 ;
        RECT  33.156 0 33.174 0.144 ;
    END
  END i[322]
  PIN i[323]
    DIRECTION INPUT ;
    USE SIGNAL ;
    PORT
      LAYER M5 ;
        RECT  33.216 0 33.24 0.192 ;
    END
  END i[323]
  PIN i[324]
    DIRECTION INPUT ;
    USE SIGNAL ;
    PORT
      LAYER M3 ;
        RECT  33.336 0 33.354 0.144 ;
    END
  END i[324]
  PIN i[325]
    DIRECTION INPUT ;
    USE SIGNAL ;
    PORT
      LAYER M5 ;
        RECT  33.408 0 33.432 0.192 ;
    END
  END i[325]
  PIN i[326]
    DIRECTION INPUT ;
    USE SIGNAL ;
    PORT
      LAYER M3 ;
        RECT  33.516 0 33.534 0.144 ;
    END
  END i[326]
  PIN i[327]
    DIRECTION INPUT ;
    USE SIGNAL ;
    PORT
      LAYER M5 ;
        RECT  33.6 0 33.624 0.192 ;
    END
  END i[327]
  PIN i[328]
    DIRECTION INPUT ;
    USE SIGNAL ;
    PORT
      LAYER M3 ;
        RECT  33.732 0 33.75 0.144 ;
    END
  END i[328]
  PIN i[329]
    DIRECTION INPUT ;
    USE SIGNAL ;
    PORT
      LAYER M5 ;
        RECT  33.792 0 33.816 0.192 ;
    END
  END i[329]
  PIN i[32]
    DIRECTION INPUT ;
    USE SIGNAL ;
    PORT
      LAYER M3 ;
        RECT  5.256 0 5.274 0.144 ;
    END
  END i[32]
  PIN i[330]
    DIRECTION INPUT ;
    USE SIGNAL ;
    PORT
      LAYER M3 ;
        RECT  33.912 0 33.93 0.144 ;
    END
  END i[330]
  PIN i[331]
    DIRECTION INPUT ;
    USE SIGNAL ;
    PORT
      LAYER M5 ;
        RECT  33.984 0 34.008 0.192 ;
    END
  END i[331]
  PIN i[332]
    DIRECTION INPUT ;
    USE SIGNAL ;
    PORT
      LAYER M3 ;
        RECT  34.092 0 34.11 0.144 ;
    END
  END i[332]
  PIN i[333]
    DIRECTION INPUT ;
    USE SIGNAL ;
    PORT
      LAYER M5 ;
        RECT  34.176 0 34.2 0.192 ;
    END
  END i[333]
  PIN i[334]
    DIRECTION INPUT ;
    USE SIGNAL ;
    PORT
      LAYER M3 ;
        RECT  34.308 0 34.326 0.144 ;
    END
  END i[334]
  PIN i[335]
    DIRECTION INPUT ;
    USE SIGNAL ;
    PORT
      LAYER M5 ;
        RECT  34.368 0 34.392 0.192 ;
    END
  END i[335]
  PIN i[336]
    DIRECTION INPUT ;
    USE SIGNAL ;
    PORT
      LAYER M3 ;
        RECT  34.488 0 34.506 0.144 ;
    END
  END i[336]
  PIN i[337]
    DIRECTION INPUT ;
    USE SIGNAL ;
    PORT
      LAYER M5 ;
        RECT  34.56 0 34.584 0.192 ;
    END
  END i[337]
  PIN i[338]
    DIRECTION INPUT ;
    USE SIGNAL ;
    PORT
      LAYER M3 ;
        RECT  34.668 0 34.686 0.144 ;
    END
  END i[338]
  PIN i[339]
    DIRECTION INPUT ;
    USE SIGNAL ;
    PORT
      LAYER M5 ;
        RECT  34.752 0 34.776 0.192 ;
    END
  END i[339]
  PIN i[33]
    DIRECTION INPUT ;
    USE SIGNAL ;
    PORT
      LAYER M5 ;
        RECT  5.376 0 5.4 0.192 ;
    END
  END i[33]
  PIN i[340]
    DIRECTION INPUT ;
    USE SIGNAL ;
    PORT
      LAYER M3 ;
        RECT  34.884 0 34.902 0.144 ;
    END
  END i[340]
  PIN i[341]
    DIRECTION INPUT ;
    USE SIGNAL ;
    PORT
      LAYER M5 ;
        RECT  34.944 0 34.968 0.192 ;
    END
  END i[341]
  PIN i[342]
    DIRECTION INPUT ;
    USE SIGNAL ;
    PORT
      LAYER M3 ;
        RECT  35.064 0 35.082 0.144 ;
    END
  END i[342]
  PIN i[343]
    DIRECTION INPUT ;
    USE SIGNAL ;
    PORT
      LAYER M5 ;
        RECT  35.136 0 35.16 0.192 ;
    END
  END i[343]
  PIN i[344]
    DIRECTION INPUT ;
    USE SIGNAL ;
    PORT
      LAYER M3 ;
        RECT  35.244 0 35.262 0.144 ;
    END
  END i[344]
  PIN i[345]
    DIRECTION INPUT ;
    USE SIGNAL ;
    PORT
      LAYER M5 ;
        RECT  35.328 0 35.352 0.192 ;
    END
  END i[345]
  PIN i[346]
    DIRECTION INPUT ;
    USE SIGNAL ;
    PORT
      LAYER M3 ;
        RECT  35.46 0 35.478 0.144 ;
    END
  END i[346]
  PIN i[347]
    DIRECTION INPUT ;
    USE SIGNAL ;
    PORT
      LAYER M5 ;
        RECT  35.52 0 35.544 0.192 ;
    END
  END i[347]
  PIN i[348]
    DIRECTION INPUT ;
    USE SIGNAL ;
    PORT
      LAYER M3 ;
        RECT  35.64 0 35.658 0.144 ;
    END
  END i[348]
  PIN i[349]
    DIRECTION INPUT ;
    USE SIGNAL ;
    PORT
      LAYER M5 ;
        RECT  35.712 0 35.736 0.192 ;
    END
  END i[349]
  PIN i[34]
    DIRECTION INPUT ;
    USE SIGNAL ;
    PORT
      LAYER M3 ;
        RECT  5.472 0 5.49 0.144 ;
    END
  END i[34]
  PIN i[350]
    DIRECTION INPUT ;
    USE SIGNAL ;
    PORT
      LAYER M3 ;
        RECT  35.82 0 35.838 0.144 ;
    END
  END i[350]
  PIN i[351]
    DIRECTION INPUT ;
    USE SIGNAL ;
    PORT
      LAYER M5 ;
        RECT  35.904 0 35.928 0.192 ;
    END
  END i[351]
  PIN i[352]
    DIRECTION INPUT ;
    USE SIGNAL ;
    PORT
      LAYER M3 ;
        RECT  36.036 0 36.054 0.144 ;
    END
  END i[352]
  PIN i[353]
    DIRECTION INPUT ;
    USE SIGNAL ;
    PORT
      LAYER M5 ;
        RECT  36.096 0 36.12 0.192 ;
    END
  END i[353]
  PIN i[354]
    DIRECTION INPUT ;
    USE SIGNAL ;
    PORT
      LAYER M3 ;
        RECT  36.216 0 36.234 0.144 ;
    END
  END i[354]
  PIN i[355]
    DIRECTION INPUT ;
    USE SIGNAL ;
    PORT
      LAYER M5 ;
        RECT  36.288 0 36.312 0.192 ;
    END
  END i[355]
  PIN i[356]
    DIRECTION INPUT ;
    USE SIGNAL ;
    PORT
      LAYER M3 ;
        RECT  36.396 0 36.414 0.144 ;
    END
  END i[356]
  PIN i[357]
    DIRECTION INPUT ;
    USE SIGNAL ;
    PORT
      LAYER M5 ;
        RECT  36.48 0 36.504 0.192 ;
    END
  END i[357]
  PIN i[358]
    DIRECTION INPUT ;
    USE SIGNAL ;
    PORT
      LAYER M3 ;
        RECT  36.612 0 36.63 0.144 ;
    END
  END i[358]
  PIN i[359]
    DIRECTION INPUT ;
    USE SIGNAL ;
    PORT
      LAYER M5 ;
        RECT  36.672 0 36.696 0.192 ;
    END
  END i[359]
  PIN i[35]
    DIRECTION INPUT ;
    USE SIGNAL ;
    PORT
      LAYER M5 ;
        RECT  5.568 0 5.592 0.192 ;
    END
  END i[35]
  PIN i[360]
    DIRECTION INPUT ;
    USE SIGNAL ;
    PORT
      LAYER M3 ;
        RECT  36.792 0 36.81 0.144 ;
    END
  END i[360]
  PIN i[361]
    DIRECTION INPUT ;
    USE SIGNAL ;
    PORT
      LAYER M5 ;
        RECT  36.864 0 36.888 0.192 ;
    END
  END i[361]
  PIN i[362]
    DIRECTION INPUT ;
    USE SIGNAL ;
    PORT
      LAYER M3 ;
        RECT  36.972 0 36.99 0.144 ;
    END
  END i[362]
  PIN i[363]
    DIRECTION INPUT ;
    USE SIGNAL ;
    PORT
      LAYER M5 ;
        RECT  37.056 0 37.08 0.192 ;
    END
  END i[363]
  PIN i[364]
    DIRECTION INPUT ;
    USE SIGNAL ;
    PORT
      LAYER M3 ;
        RECT  37.188 0 37.206 0.144 ;
    END
  END i[364]
  PIN i[365]
    DIRECTION INPUT ;
    USE SIGNAL ;
    PORT
      LAYER M5 ;
        RECT  37.248 0 37.272 0.192 ;
    END
  END i[365]
  PIN i[366]
    DIRECTION INPUT ;
    USE SIGNAL ;
    PORT
      LAYER M3 ;
        RECT  37.368 0 37.386 0.144 ;
    END
  END i[366]
  PIN i[367]
    DIRECTION INPUT ;
    USE SIGNAL ;
    PORT
      LAYER M5 ;
        RECT  37.44 0 37.464 0.192 ;
    END
  END i[367]
  PIN i[368]
    DIRECTION INPUT ;
    USE SIGNAL ;
    PORT
      LAYER M3 ;
        RECT  37.548 0 37.566 0.144 ;
    END
  END i[368]
  PIN i[369]
    DIRECTION INPUT ;
    USE SIGNAL ;
    PORT
      LAYER M5 ;
        RECT  37.632 0 37.656 0.192 ;
    END
  END i[369]
  PIN i[36]
    DIRECTION INPUT ;
    USE SIGNAL ;
    PORT
      LAYER M3 ;
        RECT  5.652 0 5.67 0.144 ;
    END
  END i[36]
  PIN i[370]
    DIRECTION INPUT ;
    USE SIGNAL ;
    PORT
      LAYER M3 ;
        RECT  37.764 0 37.782 0.144 ;
    END
  END i[370]
  PIN i[371]
    DIRECTION INPUT ;
    USE SIGNAL ;
    PORT
      LAYER M5 ;
        RECT  37.824 0 37.848 0.192 ;
    END
  END i[371]
  PIN i[372]
    DIRECTION INPUT ;
    USE SIGNAL ;
    PORT
      LAYER M3 ;
        RECT  37.944 0 37.962 0.144 ;
    END
  END i[372]
  PIN i[373]
    DIRECTION INPUT ;
    USE SIGNAL ;
    PORT
      LAYER M5 ;
        RECT  38.016 0 38.04 0.192 ;
    END
  END i[373]
  PIN i[374]
    DIRECTION INPUT ;
    USE SIGNAL ;
    PORT
      LAYER M3 ;
        RECT  38.124 0 38.142 0.144 ;
    END
  END i[374]
  PIN i[375]
    DIRECTION INPUT ;
    USE SIGNAL ;
    PORT
      LAYER M5 ;
        RECT  38.208 0 38.232 0.192 ;
    END
  END i[375]
  PIN i[376]
    DIRECTION INPUT ;
    USE SIGNAL ;
    PORT
      LAYER M3 ;
        RECT  38.34 0 38.358 0.144 ;
    END
  END i[376]
  PIN i[377]
    DIRECTION INPUT ;
    USE SIGNAL ;
    PORT
      LAYER M5 ;
        RECT  38.4 0 38.424 0.192 ;
    END
  END i[377]
  PIN i[378]
    DIRECTION INPUT ;
    USE SIGNAL ;
    PORT
      LAYER M3 ;
        RECT  38.52 0 38.538 0.144 ;
    END
  END i[378]
  PIN i[379]
    DIRECTION INPUT ;
    USE SIGNAL ;
    PORT
      LAYER M5 ;
        RECT  38.592 0 38.616 0.192 ;
    END
  END i[379]
  PIN i[37]
    DIRECTION INPUT ;
    USE SIGNAL ;
    PORT
      LAYER M5 ;
        RECT  5.76 0 5.784 0.192 ;
    END
  END i[37]
  PIN i[380]
    DIRECTION INPUT ;
    USE SIGNAL ;
    PORT
      LAYER M3 ;
        RECT  38.7 0 38.718 0.144 ;
    END
  END i[380]
  PIN i[381]
    DIRECTION INPUT ;
    USE SIGNAL ;
    PORT
      LAYER M5 ;
        RECT  38.784 0 38.808 0.192 ;
    END
  END i[381]
  PIN i[382]
    DIRECTION INPUT ;
    USE SIGNAL ;
    PORT
      LAYER M3 ;
        RECT  38.916 0 38.934 0.144 ;
    END
  END i[382]
  PIN i[383]
    DIRECTION INPUT ;
    USE SIGNAL ;
    PORT
      LAYER M5 ;
        RECT  38.976 0 39 0.192 ;
    END
  END i[383]
  PIN i[384]
    DIRECTION INPUT ;
    USE SIGNAL ;
    PORT
      LAYER M3 ;
        RECT  39.096 0 39.114 0.144 ;
    END
  END i[384]
  PIN i[385]
    DIRECTION INPUT ;
    USE SIGNAL ;
    PORT
      LAYER M5 ;
        RECT  39.168 0 39.192 0.192 ;
    END
  END i[385]
  PIN i[386]
    DIRECTION INPUT ;
    USE SIGNAL ;
    PORT
      LAYER M3 ;
        RECT  39.276 0 39.294 0.144 ;
    END
  END i[386]
  PIN i[387]
    DIRECTION INPUT ;
    USE SIGNAL ;
    PORT
      LAYER M5 ;
        RECT  39.36 0 39.384 0.192 ;
    END
  END i[387]
  PIN i[388]
    DIRECTION INPUT ;
    USE SIGNAL ;
    PORT
      LAYER M3 ;
        RECT  39.492 0 39.51 0.144 ;
    END
  END i[388]
  PIN i[389]
    DIRECTION INPUT ;
    USE SIGNAL ;
    PORT
      LAYER M5 ;
        RECT  39.552 0 39.576 0.192 ;
    END
  END i[389]
  PIN i[38]
    DIRECTION INPUT ;
    USE SIGNAL ;
    PORT
      LAYER M3 ;
        RECT  5.868 0 5.886 0.144 ;
    END
  END i[38]
  PIN i[390]
    DIRECTION INPUT ;
    USE SIGNAL ;
    PORT
      LAYER M3 ;
        RECT  39.672 0 39.69 0.144 ;
    END
  END i[390]
  PIN i[391]
    DIRECTION INPUT ;
    USE SIGNAL ;
    PORT
      LAYER M5 ;
        RECT  39.744 0 39.768 0.192 ;
    END
  END i[391]
  PIN i[392]
    DIRECTION INPUT ;
    USE SIGNAL ;
    PORT
      LAYER M3 ;
        RECT  39.852 0 39.87 0.144 ;
    END
  END i[392]
  PIN i[393]
    DIRECTION INPUT ;
    USE SIGNAL ;
    PORT
      LAYER M5 ;
        RECT  39.936 0 39.96 0.192 ;
    END
  END i[393]
  PIN i[394]
    DIRECTION INPUT ;
    USE SIGNAL ;
    PORT
      LAYER M3 ;
        RECT  40.068 0 40.086 0.144 ;
    END
  END i[394]
  PIN i[395]
    DIRECTION INPUT ;
    USE SIGNAL ;
    PORT
      LAYER M5 ;
        RECT  40.128 0 40.152 0.192 ;
    END
  END i[395]
  PIN i[396]
    DIRECTION INPUT ;
    USE SIGNAL ;
    PORT
      LAYER M3 ;
        RECT  40.248 0 40.266 0.144 ;
    END
  END i[396]
  PIN i[397]
    DIRECTION INPUT ;
    USE SIGNAL ;
    PORT
      LAYER M5 ;
        RECT  40.32 0 40.344 0.192 ;
    END
  END i[397]
  PIN i[398]
    DIRECTION INPUT ;
    USE SIGNAL ;
    PORT
      LAYER M3 ;
        RECT  40.428 0 40.446 0.144 ;
    END
  END i[398]
  PIN i[399]
    DIRECTION INPUT ;
    USE SIGNAL ;
    PORT
      LAYER M5 ;
        RECT  40.512 0 40.536 0.192 ;
    END
  END i[399]
  PIN i[39]
    DIRECTION INPUT ;
    USE SIGNAL ;
    PORT
      LAYER M5 ;
        RECT  5.952 0 5.976 0.192 ;
    END
  END i[39]
  PIN i[3]
    DIRECTION INPUT ;
    USE SIGNAL ;
    PORT
      LAYER M5 ;
        RECT  2.496 0 2.52 0.192 ;
    END
  END i[3]
  PIN i[400]
    DIRECTION INPUT ;
    USE SIGNAL ;
    PORT
      LAYER M3 ;
        RECT  40.644 0 40.662 0.144 ;
    END
  END i[400]
  PIN i[401]
    DIRECTION INPUT ;
    USE SIGNAL ;
    PORT
      LAYER M5 ;
        RECT  40.704 0 40.728 0.192 ;
    END
  END i[401]
  PIN i[402]
    DIRECTION INPUT ;
    USE SIGNAL ;
    PORT
      LAYER M3 ;
        RECT  40.824 0 40.842 0.144 ;
    END
  END i[402]
  PIN i[403]
    DIRECTION INPUT ;
    USE SIGNAL ;
    PORT
      LAYER M5 ;
        RECT  40.896 0 40.92 0.192 ;
    END
  END i[403]
  PIN i[404]
    DIRECTION INPUT ;
    USE SIGNAL ;
    PORT
      LAYER M3 ;
        RECT  41.004 0 41.022 0.144 ;
    END
  END i[404]
  PIN i[405]
    DIRECTION INPUT ;
    USE SIGNAL ;
    PORT
      LAYER M5 ;
        RECT  41.088 0 41.112 0.192 ;
    END
  END i[405]
  PIN i[406]
    DIRECTION INPUT ;
    USE SIGNAL ;
    PORT
      LAYER M3 ;
        RECT  41.22 0 41.238 0.144 ;
    END
  END i[406]
  PIN i[407]
    DIRECTION INPUT ;
    USE SIGNAL ;
    PORT
      LAYER M5 ;
        RECT  41.28 0 41.304 0.192 ;
    END
  END i[407]
  PIN i[408]
    DIRECTION INPUT ;
    USE SIGNAL ;
    PORT
      LAYER M3 ;
        RECT  41.4 0 41.418 0.144 ;
    END
  END i[408]
  PIN i[409]
    DIRECTION INPUT ;
    USE SIGNAL ;
    PORT
      LAYER M5 ;
        RECT  41.472 0 41.496 0.192 ;
    END
  END i[409]
  PIN i[40]
    DIRECTION INPUT ;
    USE SIGNAL ;
    PORT
      LAYER M3 ;
        RECT  6.048 0 6.066 0.144 ;
    END
  END i[40]
  PIN i[410]
    DIRECTION INPUT ;
    USE SIGNAL ;
    PORT
      LAYER M3 ;
        RECT  41.58 0 41.598 0.144 ;
    END
  END i[410]
  PIN i[411]
    DIRECTION INPUT ;
    USE SIGNAL ;
    PORT
      LAYER M5 ;
        RECT  41.664 0 41.688 0.192 ;
    END
  END i[411]
  PIN i[412]
    DIRECTION INPUT ;
    USE SIGNAL ;
    PORT
      LAYER M3 ;
        RECT  41.796 0 41.814 0.144 ;
    END
  END i[412]
  PIN i[413]
    DIRECTION INPUT ;
    USE SIGNAL ;
    PORT
      LAYER M5 ;
        RECT  41.856 0 41.88 0.192 ;
    END
  END i[413]
  PIN i[414]
    DIRECTION INPUT ;
    USE SIGNAL ;
    PORT
      LAYER M3 ;
        RECT  41.976 0 41.994 0.144 ;
    END
  END i[414]
  PIN i[415]
    DIRECTION INPUT ;
    USE SIGNAL ;
    PORT
      LAYER M5 ;
        RECT  42.048 0 42.072 0.192 ;
    END
  END i[415]
  PIN i[416]
    DIRECTION INPUT ;
    USE SIGNAL ;
    PORT
      LAYER M3 ;
        RECT  42.156 0 42.174 0.144 ;
    END
  END i[416]
  PIN i[417]
    DIRECTION INPUT ;
    USE SIGNAL ;
    PORT
      LAYER M5 ;
        RECT  42.24 0 42.264 0.192 ;
    END
  END i[417]
  PIN i[418]
    DIRECTION INPUT ;
    USE SIGNAL ;
    PORT
      LAYER M3 ;
        RECT  42.372 0 42.39 0.144 ;
    END
  END i[418]
  PIN i[419]
    DIRECTION INPUT ;
    USE SIGNAL ;
    PORT
      LAYER M5 ;
        RECT  42.432 0 42.456 0.192 ;
    END
  END i[419]
  PIN i[41]
    DIRECTION INPUT ;
    USE SIGNAL ;
    PORT
      LAYER M5 ;
        RECT  6.144 0 6.168 0.192 ;
    END
  END i[41]
  PIN i[420]
    DIRECTION INPUT ;
    USE SIGNAL ;
    PORT
      LAYER M3 ;
        RECT  42.552 0 42.57 0.144 ;
    END
  END i[420]
  PIN i[421]
    DIRECTION INPUT ;
    USE SIGNAL ;
    PORT
      LAYER M5 ;
        RECT  42.624 0 42.648 0.192 ;
    END
  END i[421]
  PIN i[422]
    DIRECTION INPUT ;
    USE SIGNAL ;
    PORT
      LAYER M3 ;
        RECT  42.732 0 42.75 0.144 ;
    END
  END i[422]
  PIN i[423]
    DIRECTION INPUT ;
    USE SIGNAL ;
    PORT
      LAYER M5 ;
        RECT  42.864 0 42.888 0.192 ;
    END
  END i[423]
  PIN i[424]
    DIRECTION INPUT ;
    USE SIGNAL ;
    PORT
      LAYER M3 ;
        RECT  42.948 0 42.966 0.144 ;
    END
  END i[424]
  PIN i[425]
    DIRECTION INPUT ;
    USE SIGNAL ;
    PORT
      LAYER M5 ;
        RECT  43.056 0 43.08 0.192 ;
    END
  END i[425]
  PIN i[426]
    DIRECTION INPUT ;
    USE SIGNAL ;
    PORT
      LAYER M3 ;
        RECT  43.128 0 43.146 0.144 ;
    END
  END i[426]
  PIN i[427]
    DIRECTION INPUT ;
    USE SIGNAL ;
    PORT
      LAYER M5 ;
        RECT  43.248 0 43.272 0.192 ;
    END
  END i[427]
  PIN i[428]
    DIRECTION INPUT ;
    USE SIGNAL ;
    PORT
      LAYER M3 ;
        RECT  43.308 0 43.326 0.144 ;
    END
  END i[428]
  PIN i[429]
    DIRECTION INPUT ;
    USE SIGNAL ;
    PORT
      LAYER M5 ;
        RECT  43.44 0 43.464 0.192 ;
    END
  END i[429]
  PIN i[42]
    DIRECTION INPUT ;
    USE SIGNAL ;
    PORT
      LAYER M3 ;
        RECT  6.228 0 6.246 0.144 ;
    END
  END i[42]
  PIN i[430]
    DIRECTION INPUT ;
    USE SIGNAL ;
    PORT
      LAYER M3 ;
        RECT  43.524 0 43.542 0.144 ;
    END
  END i[430]
  PIN i[431]
    DIRECTION INPUT ;
    USE SIGNAL ;
    PORT
      LAYER M5 ;
        RECT  43.632 0 43.656 0.192 ;
    END
  END i[431]
  PIN i[432]
    DIRECTION INPUT ;
    USE SIGNAL ;
    PORT
      LAYER M3 ;
        RECT  43.704 0 43.722 0.144 ;
    END
  END i[432]
  PIN i[433]
    DIRECTION INPUT ;
    USE SIGNAL ;
    PORT
      LAYER M5 ;
        RECT  43.824 0 43.848 0.192 ;
    END
  END i[433]
  PIN i[434]
    DIRECTION INPUT ;
    USE SIGNAL ;
    PORT
      LAYER M3 ;
        RECT  43.884 0 43.902 0.144 ;
    END
  END i[434]
  PIN i[435]
    DIRECTION INPUT ;
    USE SIGNAL ;
    PORT
      LAYER M5 ;
        RECT  44.016 0 44.04 0.192 ;
    END
  END i[435]
  PIN i[436]
    DIRECTION INPUT ;
    USE SIGNAL ;
    PORT
      LAYER M3 ;
        RECT  44.1 0 44.118 0.144 ;
    END
  END i[436]
  PIN i[437]
    DIRECTION INPUT ;
    USE SIGNAL ;
    PORT
      LAYER M5 ;
        RECT  44.208 0 44.232 0.192 ;
    END
  END i[437]
  PIN i[438]
    DIRECTION INPUT ;
    USE SIGNAL ;
    PORT
      LAYER M3 ;
        RECT  44.28 0 44.298 0.144 ;
    END
  END i[438]
  PIN i[439]
    DIRECTION INPUT ;
    USE SIGNAL ;
    PORT
      LAYER M5 ;
        RECT  44.4 0 44.424 0.192 ;
    END
  END i[439]
  PIN i[43]
    DIRECTION INPUT ;
    USE SIGNAL ;
    PORT
      LAYER M5 ;
        RECT  6.336 0 6.36 0.192 ;
    END
  END i[43]
  PIN i[440]
    DIRECTION INPUT ;
    USE SIGNAL ;
    PORT
      LAYER M3 ;
        RECT  44.46 0 44.478 0.144 ;
    END
  END i[440]
  PIN i[441]
    DIRECTION INPUT ;
    USE SIGNAL ;
    PORT
      LAYER M5 ;
        RECT  44.592 0 44.616 0.192 ;
    END
  END i[441]
  PIN i[442]
    DIRECTION INPUT ;
    USE SIGNAL ;
    PORT
      LAYER M3 ;
        RECT  44.676 0 44.694 0.144 ;
    END
  END i[442]
  PIN i[443]
    DIRECTION INPUT ;
    USE SIGNAL ;
    PORT
      LAYER M5 ;
        RECT  44.784 0 44.808 0.192 ;
    END
  END i[443]
  PIN i[444]
    DIRECTION INPUT ;
    USE SIGNAL ;
    PORT
      LAYER M3 ;
        RECT  44.856 0 44.874 0.144 ;
    END
  END i[444]
  PIN i[445]
    DIRECTION INPUT ;
    USE SIGNAL ;
    PORT
      LAYER M5 ;
        RECT  44.976 0 45 0.192 ;
    END
  END i[445]
  PIN i[446]
    DIRECTION INPUT ;
    USE SIGNAL ;
    PORT
      LAYER M3 ;
        RECT  45.036 0 45.054 0.144 ;
    END
  END i[446]
  PIN i[447]
    DIRECTION INPUT ;
    USE SIGNAL ;
    PORT
      LAYER M5 ;
        RECT  45.168 0 45.192 0.192 ;
    END
  END i[447]
  PIN i[448]
    DIRECTION INPUT ;
    USE SIGNAL ;
    PORT
      LAYER M3 ;
        RECT  45.252 0 45.27 0.144 ;
    END
  END i[448]
  PIN i[449]
    DIRECTION INPUT ;
    USE SIGNAL ;
    PORT
      LAYER M5 ;
        RECT  45.36 0 45.384 0.192 ;
    END
  END i[449]
  PIN i[44]
    DIRECTION INPUT ;
    USE SIGNAL ;
    PORT
      LAYER M3 ;
        RECT  6.444 0 6.462 0.144 ;
    END
  END i[44]
  PIN i[450]
    DIRECTION INPUT ;
    USE SIGNAL ;
    PORT
      LAYER M3 ;
        RECT  45.432 0 45.45 0.144 ;
    END
  END i[450]
  PIN i[451]
    DIRECTION INPUT ;
    USE SIGNAL ;
    PORT
      LAYER M5 ;
        RECT  45.552 0 45.576 0.192 ;
    END
  END i[451]
  PIN i[452]
    DIRECTION INPUT ;
    USE SIGNAL ;
    PORT
      LAYER M3 ;
        RECT  45.612 0 45.63 0.144 ;
    END
  END i[452]
  PIN i[453]
    DIRECTION INPUT ;
    USE SIGNAL ;
    PORT
      LAYER M5 ;
        RECT  45.744 0 45.768 0.192 ;
    END
  END i[453]
  PIN i[454]
    DIRECTION INPUT ;
    USE SIGNAL ;
    PORT
      LAYER M3 ;
        RECT  45.828 0 45.846 0.144 ;
    END
  END i[454]
  PIN i[455]
    DIRECTION INPUT ;
    USE SIGNAL ;
    PORT
      LAYER M5 ;
        RECT  45.936 0 45.96 0.192 ;
    END
  END i[455]
  PIN i[456]
    DIRECTION INPUT ;
    USE SIGNAL ;
    PORT
      LAYER M3 ;
        RECT  46.008 0 46.026 0.144 ;
    END
  END i[456]
  PIN i[457]
    DIRECTION INPUT ;
    USE SIGNAL ;
    PORT
      LAYER M5 ;
        RECT  46.128 0 46.152 0.192 ;
    END
  END i[457]
  PIN i[458]
    DIRECTION INPUT ;
    USE SIGNAL ;
    PORT
      LAYER M3 ;
        RECT  46.224 0 46.242 0.144 ;
    END
  END i[458]
  PIN i[459]
    DIRECTION INPUT ;
    USE SIGNAL ;
    PORT
      LAYER M5 ;
        RECT  46.32 0 46.344 0.192 ;
    END
  END i[459]
  PIN i[45]
    DIRECTION INPUT ;
    USE SIGNAL ;
    PORT
      LAYER M5 ;
        RECT  6.528 0 6.552 0.192 ;
    END
  END i[45]
  PIN i[460]
    DIRECTION INPUT ;
    USE SIGNAL ;
    PORT
      LAYER M3 ;
        RECT  46.404 0 46.422 0.144 ;
    END
  END i[460]
  PIN i[461]
    DIRECTION INPUT ;
    USE SIGNAL ;
    PORT
      LAYER M5 ;
        RECT  46.512 0 46.536 0.192 ;
    END
  END i[461]
  PIN i[462]
    DIRECTION INPUT ;
    USE SIGNAL ;
    PORT
      LAYER M3 ;
        RECT  46.584 0 46.602 0.144 ;
    END
  END i[462]
  PIN i[463]
    DIRECTION INPUT ;
    USE SIGNAL ;
    PORT
      LAYER M5 ;
        RECT  46.704 0 46.728 0.192 ;
    END
  END i[463]
  PIN i[464]
    DIRECTION INPUT ;
    USE SIGNAL ;
    PORT
      LAYER M3 ;
        RECT  46.8 0 46.818 0.144 ;
    END
  END i[464]
  PIN i[465]
    DIRECTION INPUT ;
    USE SIGNAL ;
    PORT
      LAYER M5 ;
        RECT  46.896 0 46.92 0.192 ;
    END
  END i[465]
  PIN i[466]
    DIRECTION INPUT ;
    USE SIGNAL ;
    PORT
      LAYER M3 ;
        RECT  46.98 0 46.998 0.144 ;
    END
  END i[466]
  PIN i[467]
    DIRECTION INPUT ;
    USE SIGNAL ;
    PORT
      LAYER M5 ;
        RECT  47.088 0 47.112 0.192 ;
    END
  END i[467]
  PIN i[468]
    DIRECTION INPUT ;
    USE SIGNAL ;
    PORT
      LAYER M3 ;
        RECT  47.16 0 47.178 0.144 ;
    END
  END i[468]
  PIN i[469]
    DIRECTION INPUT ;
    USE SIGNAL ;
    PORT
      LAYER M5 ;
        RECT  47.28 0 47.304 0.192 ;
    END
  END i[469]
  PIN i[46]
    DIRECTION INPUT ;
    USE SIGNAL ;
    PORT
      LAYER M3 ;
        RECT  6.624 0 6.642 0.144 ;
    END
  END i[46]
  PIN i[470]
    DIRECTION INPUT ;
    USE SIGNAL ;
    PORT
      LAYER M3 ;
        RECT  47.376 0 47.394 0.144 ;
    END
  END i[470]
  PIN i[471]
    DIRECTION INPUT ;
    USE SIGNAL ;
    PORT
      LAYER M5 ;
        RECT  47.472 0 47.496 0.192 ;
    END
  END i[471]
  PIN i[472]
    DIRECTION INPUT ;
    USE SIGNAL ;
    PORT
      LAYER M3 ;
        RECT  47.556 0 47.574 0.144 ;
    END
  END i[472]
  PIN i[473]
    DIRECTION INPUT ;
    USE SIGNAL ;
    PORT
      LAYER M5 ;
        RECT  47.664 0 47.688 0.192 ;
    END
  END i[473]
  PIN i[474]
    DIRECTION INPUT ;
    USE SIGNAL ;
    PORT
      LAYER M3 ;
        RECT  47.736 0 47.754 0.144 ;
    END
  END i[474]
  PIN i[475]
    DIRECTION INPUT ;
    USE SIGNAL ;
    PORT
      LAYER M5 ;
        RECT  47.856 0 47.88 0.192 ;
    END
  END i[475]
  PIN i[476]
    DIRECTION INPUT ;
    USE SIGNAL ;
    PORT
      LAYER M3 ;
        RECT  47.952 0 47.97 0.144 ;
    END
  END i[476]
  PIN i[477]
    DIRECTION INPUT ;
    USE SIGNAL ;
    PORT
      LAYER M5 ;
        RECT  48.048 0 48.072 0.192 ;
    END
  END i[477]
  PIN i[478]
    DIRECTION INPUT ;
    USE SIGNAL ;
    PORT
      LAYER M3 ;
        RECT  48.132 0 48.15 0.144 ;
    END
  END i[478]
  PIN i[479]
    DIRECTION INPUT ;
    USE SIGNAL ;
    PORT
      LAYER M5 ;
        RECT  48.24 0 48.264 0.192 ;
    END
  END i[479]
  PIN i[47]
    DIRECTION INPUT ;
    USE SIGNAL ;
    PORT
      LAYER M5 ;
        RECT  6.72 0 6.744 0.192 ;
    END
  END i[47]
  PIN i[480]
    DIRECTION INPUT ;
    USE SIGNAL ;
    PORT
      LAYER M3 ;
        RECT  48.312 0 48.33 0.144 ;
    END
  END i[480]
  PIN i[481]
    DIRECTION INPUT ;
    USE SIGNAL ;
    PORT
      LAYER M5 ;
        RECT  48.432 0 48.456 0.192 ;
    END
  END i[481]
  PIN i[482]
    DIRECTION INPUT ;
    USE SIGNAL ;
    PORT
      LAYER M3 ;
        RECT  48.528 0 48.546 0.144 ;
    END
  END i[482]
  PIN i[483]
    DIRECTION INPUT ;
    USE SIGNAL ;
    PORT
      LAYER M5 ;
        RECT  48.624 0 48.648 0.192 ;
    END
  END i[483]
  PIN i[484]
    DIRECTION INPUT ;
    USE SIGNAL ;
    PORT
      LAYER M3 ;
        RECT  48.708 0 48.726 0.144 ;
    END
  END i[484]
  PIN i[485]
    DIRECTION INPUT ;
    USE SIGNAL ;
    PORT
      LAYER M5 ;
        RECT  48.816 0 48.84 0.192 ;
    END
  END i[485]
  PIN i[486]
    DIRECTION INPUT ;
    USE SIGNAL ;
    PORT
      LAYER M3 ;
        RECT  48.888 0 48.906 0.144 ;
    END
  END i[486]
  PIN i[487]
    DIRECTION INPUT ;
    USE SIGNAL ;
    PORT
      LAYER M5 ;
        RECT  49.008 0 49.032 0.192 ;
    END
  END i[487]
  PIN i[488]
    DIRECTION INPUT ;
    USE SIGNAL ;
    PORT
      LAYER M3 ;
        RECT  49.104 0 49.122 0.144 ;
    END
  END i[488]
  PIN i[489]
    DIRECTION INPUT ;
    USE SIGNAL ;
    PORT
      LAYER M5 ;
        RECT  49.2 0 49.224 0.192 ;
    END
  END i[489]
  PIN i[48]
    DIRECTION INPUT ;
    USE SIGNAL ;
    PORT
      LAYER M3 ;
        RECT  6.804 0 6.822 0.144 ;
    END
  END i[48]
  PIN i[490]
    DIRECTION INPUT ;
    USE SIGNAL ;
    PORT
      LAYER M3 ;
        RECT  49.284 0 49.302 0.144 ;
    END
  END i[490]
  PIN i[491]
    DIRECTION INPUT ;
    USE SIGNAL ;
    PORT
      LAYER M5 ;
        RECT  49.392 0 49.416 0.192 ;
    END
  END i[491]
  PIN i[492]
    DIRECTION INPUT ;
    USE SIGNAL ;
    PORT
      LAYER M3 ;
        RECT  49.464 0 49.482 0.144 ;
    END
  END i[492]
  PIN i[493]
    DIRECTION INPUT ;
    USE SIGNAL ;
    PORT
      LAYER M5 ;
        RECT  49.584 0 49.608 0.192 ;
    END
  END i[493]
  PIN i[494]
    DIRECTION INPUT ;
    USE SIGNAL ;
    PORT
      LAYER M3 ;
        RECT  49.68 0 49.698 0.144 ;
    END
  END i[494]
  PIN i[495]
    DIRECTION INPUT ;
    USE SIGNAL ;
    PORT
      LAYER M5 ;
        RECT  49.776 0 49.8 0.192 ;
    END
  END i[495]
  PIN i[496]
    DIRECTION INPUT ;
    USE SIGNAL ;
    PORT
      LAYER M3 ;
        RECT  49.86 0 49.878 0.144 ;
    END
  END i[496]
  PIN i[497]
    DIRECTION INPUT ;
    USE SIGNAL ;
    PORT
      LAYER M5 ;
        RECT  49.968 0 49.992 0.192 ;
    END
  END i[497]
  PIN i[498]
    DIRECTION INPUT ;
    USE SIGNAL ;
    PORT
      LAYER M3 ;
        RECT  50.04 0 50.058 0.144 ;
    END
  END i[498]
  PIN i[499]
    DIRECTION INPUT ;
    USE SIGNAL ;
    PORT
      LAYER M5 ;
        RECT  50.16 0 50.184 0.192 ;
    END
  END i[499]
  PIN i[49]
    DIRECTION INPUT ;
    USE SIGNAL ;
    PORT
      LAYER M5 ;
        RECT  6.912 0 6.936 0.192 ;
    END
  END i[49]
  PIN i[4]
    DIRECTION INPUT ;
    USE SIGNAL ;
    PORT
      LAYER M3 ;
        RECT  2.592 0 2.61 0.144 ;
    END
  END i[4]
  PIN i[500]
    DIRECTION INPUT ;
    USE SIGNAL ;
    PORT
      LAYER M3 ;
        RECT  50.256 0 50.274 0.144 ;
    END
  END i[500]
  PIN i[501]
    DIRECTION INPUT ;
    USE SIGNAL ;
    PORT
      LAYER M5 ;
        RECT  50.352 0 50.376 0.192 ;
    END
  END i[501]
  PIN i[502]
    DIRECTION INPUT ;
    USE SIGNAL ;
    PORT
      LAYER M3 ;
        RECT  50.436 0 50.454 0.144 ;
    END
  END i[502]
  PIN i[503]
    DIRECTION INPUT ;
    USE SIGNAL ;
    PORT
      LAYER M5 ;
        RECT  50.544 0 50.568 0.192 ;
    END
  END i[503]
  PIN i[504]
    DIRECTION INPUT ;
    USE SIGNAL ;
    PORT
      LAYER M3 ;
        RECT  50.616 0 50.634 0.144 ;
    END
  END i[504]
  PIN i[505]
    DIRECTION INPUT ;
    USE SIGNAL ;
    PORT
      LAYER M5 ;
        RECT  50.736 0 50.76 0.192 ;
    END
  END i[505]
  PIN i[506]
    DIRECTION INPUT ;
    USE SIGNAL ;
    PORT
      LAYER M3 ;
        RECT  50.832 0 50.85 0.144 ;
    END
  END i[506]
  PIN i[507]
    DIRECTION INPUT ;
    USE SIGNAL ;
    PORT
      LAYER M5 ;
        RECT  50.928 0 50.952 0.192 ;
    END
  END i[507]
  PIN i[508]
    DIRECTION INPUT ;
    USE SIGNAL ;
    PORT
      LAYER M3 ;
        RECT  51.012 0 51.03 0.144 ;
    END
  END i[508]
  PIN i[509]
    DIRECTION INPUT ;
    USE SIGNAL ;
    PORT
      LAYER M5 ;
        RECT  51.12 0 51.144 0.192 ;
    END
  END i[509]
  PIN i[50]
    DIRECTION INPUT ;
    USE SIGNAL ;
    PORT
      LAYER M3 ;
        RECT  7.02 0 7.038 0.144 ;
    END
  END i[50]
  PIN i[510]
    DIRECTION INPUT ;
    USE SIGNAL ;
    PORT
      LAYER M3 ;
        RECT  51.192 0 51.21 0.144 ;
    END
  END i[510]
  PIN i[511]
    DIRECTION INPUT ;
    USE SIGNAL ;
    PORT
      LAYER M5 ;
        RECT  51.312 0 51.336 0.192 ;
    END
  END i[511]
  PIN i[512]
    DIRECTION INPUT ;
    USE SIGNAL ;
    PORT
      LAYER M3 ;
        RECT  51.408 0 51.426 0.144 ;
    END
  END i[512]
  PIN i[513]
    DIRECTION INPUT ;
    USE SIGNAL ;
    PORT
      LAYER M5 ;
        RECT  51.504 0 51.528 0.192 ;
    END
  END i[513]
  PIN i[514]
    DIRECTION INPUT ;
    USE SIGNAL ;
    PORT
      LAYER M3 ;
        RECT  51.588 0 51.606 0.144 ;
    END
  END i[514]
  PIN i[515]
    DIRECTION INPUT ;
    USE SIGNAL ;
    PORT
      LAYER M5 ;
        RECT  51.696 0 51.72 0.192 ;
    END
  END i[515]
  PIN i[516]
    DIRECTION INPUT ;
    USE SIGNAL ;
    PORT
      LAYER M3 ;
        RECT  51.768 0 51.786 0.144 ;
    END
  END i[516]
  PIN i[517]
    DIRECTION INPUT ;
    USE SIGNAL ;
    PORT
      LAYER M5 ;
        RECT  51.888 0 51.912 0.192 ;
    END
  END i[517]
  PIN i[518]
    DIRECTION INPUT ;
    USE SIGNAL ;
    PORT
      LAYER M3 ;
        RECT  51.984 0 52.002 0.144 ;
    END
  END i[518]
  PIN i[519]
    DIRECTION INPUT ;
    USE SIGNAL ;
    PORT
      LAYER M5 ;
        RECT  52.08 0 52.104 0.192 ;
    END
  END i[519]
  PIN i[51]
    DIRECTION INPUT ;
    USE SIGNAL ;
    PORT
      LAYER M5 ;
        RECT  7.104 0 7.128 0.192 ;
    END
  END i[51]
  PIN i[520]
    DIRECTION INPUT ;
    USE SIGNAL ;
    PORT
      LAYER M3 ;
        RECT  52.164 0 52.182 0.144 ;
    END
  END i[520]
  PIN i[521]
    DIRECTION INPUT ;
    USE SIGNAL ;
    PORT
      LAYER M5 ;
        RECT  52.272 0 52.296 0.192 ;
    END
  END i[521]
  PIN i[522]
    DIRECTION INPUT ;
    USE SIGNAL ;
    PORT
      LAYER M3 ;
        RECT  52.344 0 52.362 0.144 ;
    END
  END i[522]
  PIN i[523]
    DIRECTION INPUT ;
    USE SIGNAL ;
    PORT
      LAYER M5 ;
        RECT  52.464 0 52.488 0.192 ;
    END
  END i[523]
  PIN i[524]
    DIRECTION INPUT ;
    USE SIGNAL ;
    PORT
      LAYER M3 ;
        RECT  52.56 0 52.578 0.144 ;
    END
  END i[524]
  PIN i[525]
    DIRECTION INPUT ;
    USE SIGNAL ;
    PORT
      LAYER M5 ;
        RECT  52.656 0 52.68 0.192 ;
    END
  END i[525]
  PIN i[526]
    DIRECTION INPUT ;
    USE SIGNAL ;
    PORT
      LAYER M3 ;
        RECT  52.74 0 52.758 0.144 ;
    END
  END i[526]
  PIN i[527]
    DIRECTION INPUT ;
    USE SIGNAL ;
    PORT
      LAYER M5 ;
        RECT  52.848 0 52.872 0.192 ;
    END
  END i[527]
  PIN i[528]
    DIRECTION INPUT ;
    USE SIGNAL ;
    PORT
      LAYER M3 ;
        RECT  52.92 0 52.938 0.144 ;
    END
  END i[528]
  PIN i[529]
    DIRECTION INPUT ;
    USE SIGNAL ;
    PORT
      LAYER M5 ;
        RECT  53.04 0 53.064 0.192 ;
    END
  END i[529]
  PIN i[52]
    DIRECTION INPUT ;
    USE SIGNAL ;
    PORT
      LAYER M3 ;
        RECT  7.2 0 7.218 0.144 ;
    END
  END i[52]
  PIN i[530]
    DIRECTION INPUT ;
    USE SIGNAL ;
    PORT
      LAYER M3 ;
        RECT  53.136 0 53.154 0.144 ;
    END
  END i[530]
  PIN i[531]
    DIRECTION INPUT ;
    USE SIGNAL ;
    PORT
      LAYER M5 ;
        RECT  53.232 0 53.256 0.192 ;
    END
  END i[531]
  PIN i[532]
    DIRECTION INPUT ;
    USE SIGNAL ;
    PORT
      LAYER M3 ;
        RECT  53.316 0 53.334 0.144 ;
    END
  END i[532]
  PIN i[533]
    DIRECTION INPUT ;
    USE SIGNAL ;
    PORT
      LAYER M5 ;
        RECT  53.424 0 53.448 0.192 ;
    END
  END i[533]
  PIN i[534]
    DIRECTION INPUT ;
    USE SIGNAL ;
    PORT
      LAYER M3 ;
        RECT  53.496 0 53.514 0.144 ;
    END
  END i[534]
  PIN i[535]
    DIRECTION INPUT ;
    USE SIGNAL ;
    PORT
      LAYER M5 ;
        RECT  53.616 0 53.64 0.192 ;
    END
  END i[535]
  PIN i[536]
    DIRECTION INPUT ;
    USE SIGNAL ;
    PORT
      LAYER M3 ;
        RECT  53.712 0 53.73 0.144 ;
    END
  END i[536]
  PIN i[537]
    DIRECTION INPUT ;
    USE SIGNAL ;
    PORT
      LAYER M5 ;
        RECT  53.808 0 53.832 0.192 ;
    END
  END i[537]
  PIN i[538]
    DIRECTION INPUT ;
    USE SIGNAL ;
    PORT
      LAYER M3 ;
        RECT  53.892 0 53.91 0.144 ;
    END
  END i[538]
  PIN i[539]
    DIRECTION INPUT ;
    USE SIGNAL ;
    PORT
      LAYER M5 ;
        RECT  54 0 54.024 0.192 ;
    END
  END i[539]
  PIN i[53]
    DIRECTION INPUT ;
    USE SIGNAL ;
    PORT
      LAYER M5 ;
        RECT  7.296 0 7.32 0.192 ;
    END
  END i[53]
  PIN i[540]
    DIRECTION INPUT ;
    USE SIGNAL ;
    PORT
      LAYER M3 ;
        RECT  54.072 0 54.09 0.144 ;
    END
  END i[540]
  PIN i[541]
    DIRECTION INPUT ;
    USE SIGNAL ;
    PORT
      LAYER M5 ;
        RECT  54.192 0 54.216 0.192 ;
    END
  END i[541]
  PIN i[542]
    DIRECTION INPUT ;
    USE SIGNAL ;
    PORT
      LAYER M3 ;
        RECT  54.288 0 54.306 0.144 ;
    END
  END i[542]
  PIN i[543]
    DIRECTION INPUT ;
    USE SIGNAL ;
    PORT
      LAYER M5 ;
        RECT  54.384 0 54.408 0.192 ;
    END
  END i[543]
  PIN i[544]
    DIRECTION INPUT ;
    USE SIGNAL ;
    PORT
      LAYER M3 ;
        RECT  54.468 0 54.486 0.144 ;
    END
  END i[544]
  PIN i[545]
    DIRECTION INPUT ;
    USE SIGNAL ;
    PORT
      LAYER M5 ;
        RECT  54.576 0 54.6 0.192 ;
    END
  END i[545]
  PIN i[546]
    DIRECTION INPUT ;
    USE SIGNAL ;
    PORT
      LAYER M3 ;
        RECT  54.648 0 54.666 0.144 ;
    END
  END i[546]
  PIN i[547]
    DIRECTION INPUT ;
    USE SIGNAL ;
    PORT
      LAYER M5 ;
        RECT  54.768 0 54.792 0.192 ;
    END
  END i[547]
  PIN i[548]
    DIRECTION INPUT ;
    USE SIGNAL ;
    PORT
      LAYER M3 ;
        RECT  54.864 0 54.882 0.144 ;
    END
  END i[548]
  PIN i[549]
    DIRECTION INPUT ;
    USE SIGNAL ;
    PORT
      LAYER M5 ;
        RECT  54.96 0 54.984 0.192 ;
    END
  END i[549]
  PIN i[54]
    DIRECTION INPUT ;
    USE SIGNAL ;
    PORT
      LAYER M3 ;
        RECT  7.38 0 7.398 0.144 ;
    END
  END i[54]
  PIN i[550]
    DIRECTION INPUT ;
    USE SIGNAL ;
    PORT
      LAYER M3 ;
        RECT  55.044 0 55.062 0.144 ;
    END
  END i[550]
  PIN i[551]
    DIRECTION INPUT ;
    USE SIGNAL ;
    PORT
      LAYER M5 ;
        RECT  55.152 0 55.176 0.192 ;
    END
  END i[551]
  PIN i[552]
    DIRECTION INPUT ;
    USE SIGNAL ;
    PORT
      LAYER M3 ;
        RECT  55.224 0 55.242 0.144 ;
    END
  END i[552]
  PIN i[553]
    DIRECTION INPUT ;
    USE SIGNAL ;
    PORT
      LAYER M5 ;
        RECT  55.344 0 55.368 0.192 ;
    END
  END i[553]
  PIN i[554]
    DIRECTION INPUT ;
    USE SIGNAL ;
    PORT
      LAYER M3 ;
        RECT  55.44 0 55.458 0.144 ;
    END
  END i[554]
  PIN i[555]
    DIRECTION INPUT ;
    USE SIGNAL ;
    PORT
      LAYER M5 ;
        RECT  55.536 0 55.56 0.192 ;
    END
  END i[555]
  PIN i[556]
    DIRECTION INPUT ;
    USE SIGNAL ;
    PORT
      LAYER M3 ;
        RECT  55.62 0 55.638 0.144 ;
    END
  END i[556]
  PIN i[557]
    DIRECTION INPUT ;
    USE SIGNAL ;
    PORT
      LAYER M5 ;
        RECT  55.728 0 55.752 0.192 ;
    END
  END i[557]
  PIN i[558]
    DIRECTION INPUT ;
    USE SIGNAL ;
    PORT
      LAYER M3 ;
        RECT  55.8 0 55.818 0.144 ;
    END
  END i[558]
  PIN i[559]
    DIRECTION INPUT ;
    USE SIGNAL ;
    PORT
      LAYER M5 ;
        RECT  55.92 0 55.944 0.192 ;
    END
  END i[559]
  PIN i[55]
    DIRECTION INPUT ;
    USE SIGNAL ;
    PORT
      LAYER M5 ;
        RECT  7.488 0 7.512 0.192 ;
    END
  END i[55]
  PIN i[560]
    DIRECTION INPUT ;
    USE SIGNAL ;
    PORT
      LAYER M3 ;
        RECT  56.016 0 56.034 0.144 ;
    END
  END i[560]
  PIN i[561]
    DIRECTION INPUT ;
    USE SIGNAL ;
    PORT
      LAYER M5 ;
        RECT  56.112 0 56.136 0.192 ;
    END
  END i[561]
  PIN i[56]
    DIRECTION INPUT ;
    USE SIGNAL ;
    PORT
      LAYER M3 ;
        RECT  7.596 0 7.614 0.144 ;
    END
  END i[56]
  PIN i[57]
    DIRECTION INPUT ;
    USE SIGNAL ;
    PORT
      LAYER M5 ;
        RECT  7.68 0 7.704 0.192 ;
    END
  END i[57]
  PIN i[58]
    DIRECTION INPUT ;
    USE SIGNAL ;
    PORT
      LAYER M3 ;
        RECT  7.776 0 7.794 0.144 ;
    END
  END i[58]
  PIN i[59]
    DIRECTION INPUT ;
    USE SIGNAL ;
    PORT
      LAYER M5 ;
        RECT  7.872 0 7.896 0.192 ;
    END
  END i[59]
  PIN i[5]
    DIRECTION INPUT ;
    USE SIGNAL ;
    PORT
      LAYER M5 ;
        RECT  2.688 0 2.712 0.192 ;
    END
  END i[5]
  PIN i[60]
    DIRECTION INPUT ;
    USE SIGNAL ;
    PORT
      LAYER M3 ;
        RECT  7.956 0 7.974 0.144 ;
    END
  END i[60]
  PIN i[61]
    DIRECTION INPUT ;
    USE SIGNAL ;
    PORT
      LAYER M5 ;
        RECT  8.064 0 8.088 0.192 ;
    END
  END i[61]
  PIN i[62]
    DIRECTION INPUT ;
    USE SIGNAL ;
    PORT
      LAYER M3 ;
        RECT  8.172 0 8.19 0.144 ;
    END
  END i[62]
  PIN i[63]
    DIRECTION INPUT ;
    USE SIGNAL ;
    PORT
      LAYER M5 ;
        RECT  8.256 0 8.28 0.192 ;
    END
  END i[63]
  PIN i[64]
    DIRECTION INPUT ;
    USE SIGNAL ;
    PORT
      LAYER M3 ;
        RECT  8.352 0 8.37 0.144 ;
    END
  END i[64]
  PIN i[65]
    DIRECTION INPUT ;
    USE SIGNAL ;
    PORT
      LAYER M5 ;
        RECT  8.448 0 8.472 0.192 ;
    END
  END i[65]
  PIN i[66]
    DIRECTION INPUT ;
    USE SIGNAL ;
    PORT
      LAYER M3 ;
        RECT  8.532 0 8.55 0.144 ;
    END
  END i[66]
  PIN i[67]
    DIRECTION INPUT ;
    USE SIGNAL ;
    PORT
      LAYER M5 ;
        RECT  8.64 0 8.664 0.192 ;
    END
  END i[67]
  PIN i[68]
    DIRECTION INPUT ;
    USE SIGNAL ;
    PORT
      LAYER M3 ;
        RECT  8.748 0 8.766 0.144 ;
    END
  END i[68]
  PIN i[69]
    DIRECTION INPUT ;
    USE SIGNAL ;
    PORT
      LAYER M5 ;
        RECT  8.832 0 8.856 0.192 ;
    END
  END i[69]
  PIN i[6]
    DIRECTION INPUT ;
    USE SIGNAL ;
    PORT
      LAYER M3 ;
        RECT  2.772 0 2.79 0.144 ;
    END
  END i[6]
  PIN i[70]
    DIRECTION INPUT ;
    USE SIGNAL ;
    PORT
      LAYER M3 ;
        RECT  8.928 0 8.946 0.144 ;
    END
  END i[70]
  PIN i[71]
    DIRECTION INPUT ;
    USE SIGNAL ;
    PORT
      LAYER M5 ;
        RECT  9.024 0 9.048 0.192 ;
    END
  END i[71]
  PIN i[72]
    DIRECTION INPUT ;
    USE SIGNAL ;
    PORT
      LAYER M3 ;
        RECT  9.108 0 9.126 0.144 ;
    END
  END i[72]
  PIN i[73]
    DIRECTION INPUT ;
    USE SIGNAL ;
    PORT
      LAYER M5 ;
        RECT  9.216 0 9.24 0.192 ;
    END
  END i[73]
  PIN i[74]
    DIRECTION INPUT ;
    USE SIGNAL ;
    PORT
      LAYER M3 ;
        RECT  9.324 0 9.342 0.144 ;
    END
  END i[74]
  PIN i[75]
    DIRECTION INPUT ;
    USE SIGNAL ;
    PORT
      LAYER M5 ;
        RECT  9.408 0 9.432 0.192 ;
    END
  END i[75]
  PIN i[76]
    DIRECTION INPUT ;
    USE SIGNAL ;
    PORT
      LAYER M3 ;
        RECT  9.504 0 9.522 0.144 ;
    END
  END i[76]
  PIN i[77]
    DIRECTION INPUT ;
    USE SIGNAL ;
    PORT
      LAYER M5 ;
        RECT  9.6 0 9.624 0.192 ;
    END
  END i[77]
  PIN i[78]
    DIRECTION INPUT ;
    USE SIGNAL ;
    PORT
      LAYER M3 ;
        RECT  9.684 0 9.702 0.144 ;
    END
  END i[78]
  PIN i[79]
    DIRECTION INPUT ;
    USE SIGNAL ;
    PORT
      LAYER M5 ;
        RECT  9.792 0 9.816 0.192 ;
    END
  END i[79]
  PIN i[7]
    DIRECTION INPUT ;
    USE SIGNAL ;
    PORT
      LAYER M5 ;
        RECT  2.88 0 2.904 0.192 ;
    END
  END i[7]
  PIN i[80]
    DIRECTION INPUT ;
    USE SIGNAL ;
    PORT
      LAYER M3 ;
        RECT  9.9 0 9.918 0.144 ;
    END
  END i[80]
  PIN i[81]
    DIRECTION INPUT ;
    USE SIGNAL ;
    PORT
      LAYER M5 ;
        RECT  9.984 0 10.008 0.192 ;
    END
  END i[81]
  PIN i[82]
    DIRECTION INPUT ;
    USE SIGNAL ;
    PORT
      LAYER M3 ;
        RECT  10.08 0 10.098 0.144 ;
    END
  END i[82]
  PIN i[83]
    DIRECTION INPUT ;
    USE SIGNAL ;
    PORT
      LAYER M5 ;
        RECT  10.176 0 10.2 0.192 ;
    END
  END i[83]
  PIN i[84]
    DIRECTION INPUT ;
    USE SIGNAL ;
    PORT
      LAYER M3 ;
        RECT  10.26 0 10.278 0.144 ;
    END
  END i[84]
  PIN i[85]
    DIRECTION INPUT ;
    USE SIGNAL ;
    PORT
      LAYER M5 ;
        RECT  10.368 0 10.392 0.192 ;
    END
  END i[85]
  PIN i[86]
    DIRECTION INPUT ;
    USE SIGNAL ;
    PORT
      LAYER M3 ;
        RECT  10.476 0 10.494 0.144 ;
    END
  END i[86]
  PIN i[87]
    DIRECTION INPUT ;
    USE SIGNAL ;
    PORT
      LAYER M5 ;
        RECT  10.56 0 10.584 0.192 ;
    END
  END i[87]
  PIN i[88]
    DIRECTION INPUT ;
    USE SIGNAL ;
    PORT
      LAYER M3 ;
        RECT  10.656 0 10.674 0.144 ;
    END
  END i[88]
  PIN i[89]
    DIRECTION INPUT ;
    USE SIGNAL ;
    PORT
      LAYER M5 ;
        RECT  10.752 0 10.776 0.192 ;
    END
  END i[89]
  PIN i[8]
    DIRECTION INPUT ;
    USE SIGNAL ;
    PORT
      LAYER M3 ;
        RECT  2.952 0 2.97 0.144 ;
    END
  END i[8]
  PIN i[90]
    DIRECTION INPUT ;
    USE SIGNAL ;
    PORT
      LAYER M3 ;
        RECT  10.836 0 10.854 0.144 ;
    END
  END i[90]
  PIN i[91]
    DIRECTION INPUT ;
    USE SIGNAL ;
    PORT
      LAYER M5 ;
        RECT  10.944 0 10.968 0.192 ;
    END
  END i[91]
  PIN i[92]
    DIRECTION INPUT ;
    USE SIGNAL ;
    PORT
      LAYER M3 ;
        RECT  11.052 0 11.07 0.144 ;
    END
  END i[92]
  PIN i[93]
    DIRECTION INPUT ;
    USE SIGNAL ;
    PORT
      LAYER M5 ;
        RECT  11.136 0 11.16 0.192 ;
    END
  END i[93]
  PIN i[94]
    DIRECTION INPUT ;
    USE SIGNAL ;
    PORT
      LAYER M3 ;
        RECT  11.232 0 11.25 0.144 ;
    END
  END i[94]
  PIN i[95]
    DIRECTION INPUT ;
    USE SIGNAL ;
    PORT
      LAYER M5 ;
        RECT  11.328 0 11.352 0.192 ;
    END
  END i[95]
  PIN i[96]
    DIRECTION INPUT ;
    USE SIGNAL ;
    PORT
      LAYER M3 ;
        RECT  11.412 0 11.43 0.144 ;
    END
  END i[96]
  PIN i[97]
    DIRECTION INPUT ;
    USE SIGNAL ;
    PORT
      LAYER M5 ;
        RECT  11.52 0 11.544 0.192 ;
    END
  END i[97]
  PIN i[98]
    DIRECTION INPUT ;
    USE SIGNAL ;
    PORT
      LAYER M3 ;
        RECT  11.628 0 11.646 0.144 ;
    END
  END i[98]
  PIN i[99]
    DIRECTION INPUT ;
    USE SIGNAL ;
    PORT
      LAYER M5 ;
        RECT  11.712 0 11.736 0.192 ;
    END
  END i[99]
  PIN i[9]
    DIRECTION INPUT ;
    USE SIGNAL ;
    PORT
      LAYER M5 ;
        RECT  3.072 0 3.096 0.192 ;
    END
  END i[9]
  PIN o[0]
    DIRECTION OUTPUT ;
    USE SIGNAL ;
    PORT
      LAYER M3 ;
        RECT  2.196 17.136 2.214 17.28 ;
    END
  END o[0]
  PIN o[100]
    DIRECTION OUTPUT ;
    USE SIGNAL ;
    PORT
      LAYER M3 ;
        RECT  11.808 17.136 11.826 17.28 ;
    END
  END o[100]
  PIN o[101]
    DIRECTION OUTPUT ;
    USE SIGNAL ;
    PORT
      LAYER M5 ;
        RECT  11.904 17.088 11.928 17.28 ;
    END
  END o[101]
  PIN o[102]
    DIRECTION OUTPUT ;
    USE SIGNAL ;
    PORT
      LAYER M3 ;
        RECT  11.988 17.136 12.006 17.28 ;
    END
  END o[102]
  PIN o[103]
    DIRECTION OUTPUT ;
    USE SIGNAL ;
    PORT
      LAYER M5 ;
        RECT  12.096 17.088 12.12 17.28 ;
    END
  END o[103]
  PIN o[104]
    DIRECTION OUTPUT ;
    USE SIGNAL ;
    PORT
      LAYER M3 ;
        RECT  12.168 17.136 12.186 17.28 ;
    END
  END o[104]
  PIN o[105]
    DIRECTION OUTPUT ;
    USE SIGNAL ;
    PORT
      LAYER M5 ;
        RECT  12.288 17.088 12.312 17.28 ;
    END
  END o[105]
  PIN o[106]
    DIRECTION OUTPUT ;
    USE SIGNAL ;
    PORT
      LAYER M3 ;
        RECT  12.348 17.136 12.366 17.28 ;
    END
  END o[106]
  PIN o[107]
    DIRECTION OUTPUT ;
    USE SIGNAL ;
    PORT
      LAYER M5 ;
        RECT  12.48 17.088 12.504 17.28 ;
    END
  END o[107]
  PIN o[108]
    DIRECTION OUTPUT ;
    USE SIGNAL ;
    PORT
      LAYER M3 ;
        RECT  12.564 17.136 12.582 17.28 ;
    END
  END o[108]
  PIN o[109]
    DIRECTION OUTPUT ;
    USE SIGNAL ;
    PORT
      LAYER M5 ;
        RECT  12.672 17.088 12.696 17.28 ;
    END
  END o[109]
  PIN o[10]
    DIRECTION OUTPUT ;
    USE SIGNAL ;
    PORT
      LAYER M3 ;
        RECT  3.168 17.136 3.186 17.28 ;
    END
  END o[10]
  PIN o[110]
    DIRECTION OUTPUT ;
    USE SIGNAL ;
    PORT
      LAYER M3 ;
        RECT  12.744 17.136 12.762 17.28 ;
    END
  END o[110]
  PIN o[111]
    DIRECTION OUTPUT ;
    USE SIGNAL ;
    PORT
      LAYER M5 ;
        RECT  12.864 17.088 12.888 17.28 ;
    END
  END o[111]
  PIN o[112]
    DIRECTION OUTPUT ;
    USE SIGNAL ;
    PORT
      LAYER M3 ;
        RECT  12.924 17.136 12.942 17.28 ;
    END
  END o[112]
  PIN o[113]
    DIRECTION OUTPUT ;
    USE SIGNAL ;
    PORT
      LAYER M5 ;
        RECT  13.056 17.088 13.08 17.28 ;
    END
  END o[113]
  PIN o[114]
    DIRECTION OUTPUT ;
    USE SIGNAL ;
    PORT
      LAYER M3 ;
        RECT  13.14 17.136 13.158 17.28 ;
    END
  END o[114]
  PIN o[115]
    DIRECTION OUTPUT ;
    USE SIGNAL ;
    PORT
      LAYER M5 ;
        RECT  13.248 17.088 13.272 17.28 ;
    END
  END o[115]
  PIN o[116]
    DIRECTION OUTPUT ;
    USE SIGNAL ;
    PORT
      LAYER M3 ;
        RECT  13.32 17.136 13.338 17.28 ;
    END
  END o[116]
  PIN o[117]
    DIRECTION OUTPUT ;
    USE SIGNAL ;
    PORT
      LAYER M5 ;
        RECT  13.44 17.088 13.464 17.28 ;
    END
  END o[117]
  PIN o[118]
    DIRECTION OUTPUT ;
    USE SIGNAL ;
    PORT
      LAYER M3 ;
        RECT  13.5 17.136 13.518 17.28 ;
    END
  END o[118]
  PIN o[119]
    DIRECTION OUTPUT ;
    USE SIGNAL ;
    PORT
      LAYER M5 ;
        RECT  13.632 17.088 13.656 17.28 ;
    END
  END o[119]
  PIN o[11]
    DIRECTION OUTPUT ;
    USE SIGNAL ;
    PORT
      LAYER M5 ;
        RECT  3.264 17.088 3.288 17.28 ;
    END
  END o[11]
  PIN o[120]
    DIRECTION OUTPUT ;
    USE SIGNAL ;
    PORT
      LAYER M3 ;
        RECT  13.716 17.136 13.734 17.28 ;
    END
  END o[120]
  PIN o[121]
    DIRECTION OUTPUT ;
    USE SIGNAL ;
    PORT
      LAYER M5 ;
        RECT  13.824 17.088 13.848 17.28 ;
    END
  END o[121]
  PIN o[122]
    DIRECTION OUTPUT ;
    USE SIGNAL ;
    PORT
      LAYER M3 ;
        RECT  13.896 17.136 13.914 17.28 ;
    END
  END o[122]
  PIN o[123]
    DIRECTION OUTPUT ;
    USE SIGNAL ;
    PORT
      LAYER M5 ;
        RECT  14.016 17.088 14.04 17.28 ;
    END
  END o[123]
  PIN o[124]
    DIRECTION OUTPUT ;
    USE SIGNAL ;
    PORT
      LAYER M3 ;
        RECT  14.076 17.136 14.094 17.28 ;
    END
  END o[124]
  PIN o[125]
    DIRECTION OUTPUT ;
    USE SIGNAL ;
    PORT
      LAYER M5 ;
        RECT  14.208 17.088 14.232 17.28 ;
    END
  END o[125]
  PIN o[126]
    DIRECTION OUTPUT ;
    USE SIGNAL ;
    PORT
      LAYER M3 ;
        RECT  14.292 17.136 14.31 17.28 ;
    END
  END o[126]
  PIN o[127]
    DIRECTION OUTPUT ;
    USE SIGNAL ;
    PORT
      LAYER M5 ;
        RECT  14.4 17.088 14.424 17.28 ;
    END
  END o[127]
  PIN o[128]
    DIRECTION OUTPUT ;
    USE SIGNAL ;
    PORT
      LAYER M3 ;
        RECT  14.472 17.136 14.49 17.28 ;
    END
  END o[128]
  PIN o[129]
    DIRECTION OUTPUT ;
    USE SIGNAL ;
    PORT
      LAYER M5 ;
        RECT  14.592 17.088 14.616 17.28 ;
    END
  END o[129]
  PIN o[12]
    DIRECTION OUTPUT ;
    USE SIGNAL ;
    PORT
      LAYER M3 ;
        RECT  3.348 17.136 3.366 17.28 ;
    END
  END o[12]
  PIN o[130]
    DIRECTION OUTPUT ;
    USE SIGNAL ;
    PORT
      LAYER M3 ;
        RECT  14.652 17.136 14.67 17.28 ;
    END
  END o[130]
  PIN o[131]
    DIRECTION OUTPUT ;
    USE SIGNAL ;
    PORT
      LAYER M5 ;
        RECT  14.784 17.088 14.808 17.28 ;
    END
  END o[131]
  PIN o[132]
    DIRECTION OUTPUT ;
    USE SIGNAL ;
    PORT
      LAYER M3 ;
        RECT  14.868 17.136 14.886 17.28 ;
    END
  END o[132]
  PIN o[133]
    DIRECTION OUTPUT ;
    USE SIGNAL ;
    PORT
      LAYER M5 ;
        RECT  14.976 17.088 15 17.28 ;
    END
  END o[133]
  PIN o[134]
    DIRECTION OUTPUT ;
    USE SIGNAL ;
    PORT
      LAYER M3 ;
        RECT  15.048 17.136 15.066 17.28 ;
    END
  END o[134]
  PIN o[135]
    DIRECTION OUTPUT ;
    USE SIGNAL ;
    PORT
      LAYER M5 ;
        RECT  15.168 17.088 15.192 17.28 ;
    END
  END o[135]
  PIN o[136]
    DIRECTION OUTPUT ;
    USE SIGNAL ;
    PORT
      LAYER M3 ;
        RECT  15.228 17.136 15.246 17.28 ;
    END
  END o[136]
  PIN o[137]
    DIRECTION OUTPUT ;
    USE SIGNAL ;
    PORT
      LAYER M5 ;
        RECT  15.36 17.088 15.384 17.28 ;
    END
  END o[137]
  PIN o[138]
    DIRECTION OUTPUT ;
    USE SIGNAL ;
    PORT
      LAYER M3 ;
        RECT  15.444 17.136 15.462 17.28 ;
    END
  END o[138]
  PIN o[139]
    DIRECTION OUTPUT ;
    USE SIGNAL ;
    PORT
      LAYER M5 ;
        RECT  15.552 17.088 15.576 17.28 ;
    END
  END o[139]
  PIN o[13]
    DIRECTION OUTPUT ;
    USE SIGNAL ;
    PORT
      LAYER M5 ;
        RECT  3.456 17.088 3.48 17.28 ;
    END
  END o[13]
  PIN o[140]
    DIRECTION OUTPUT ;
    USE SIGNAL ;
    PORT
      LAYER M3 ;
        RECT  15.624 17.136 15.642 17.28 ;
    END
  END o[140]
  PIN o[141]
    DIRECTION OUTPUT ;
    USE SIGNAL ;
    PORT
      LAYER M5 ;
        RECT  15.696 17.088 15.72 17.28 ;
    END
  END o[141]
  PIN o[142]
    DIRECTION OUTPUT ;
    USE SIGNAL ;
    PORT
      LAYER M3 ;
        RECT  15.804 17.136 15.822 17.28 ;
    END
  END o[142]
  PIN o[143]
    DIRECTION OUTPUT ;
    USE SIGNAL ;
    PORT
      LAYER M5 ;
        RECT  15.888 17.088 15.912 17.28 ;
    END
  END o[143]
  PIN o[144]
    DIRECTION OUTPUT ;
    USE SIGNAL ;
    PORT
      LAYER M3 ;
        RECT  16.02 17.136 16.038 17.28 ;
    END
  END o[144]
  PIN o[145]
    DIRECTION OUTPUT ;
    USE SIGNAL ;
    PORT
      LAYER M5 ;
        RECT  16.08 17.088 16.104 17.28 ;
    END
  END o[145]
  PIN o[146]
    DIRECTION OUTPUT ;
    USE SIGNAL ;
    PORT
      LAYER M3 ;
        RECT  16.2 17.136 16.218 17.28 ;
    END
  END o[146]
  PIN o[147]
    DIRECTION OUTPUT ;
    USE SIGNAL ;
    PORT
      LAYER M5 ;
        RECT  16.272 17.088 16.296 17.28 ;
    END
  END o[147]
  PIN o[148]
    DIRECTION OUTPUT ;
    USE SIGNAL ;
    PORT
      LAYER M3 ;
        RECT  16.38 17.136 16.398 17.28 ;
    END
  END o[148]
  PIN o[149]
    DIRECTION OUTPUT ;
    USE SIGNAL ;
    PORT
      LAYER M5 ;
        RECT  16.464 17.088 16.488 17.28 ;
    END
  END o[149]
  PIN o[14]
    DIRECTION OUTPUT ;
    USE SIGNAL ;
    PORT
      LAYER M3 ;
        RECT  3.528 17.136 3.546 17.28 ;
    END
  END o[14]
  PIN o[150]
    DIRECTION OUTPUT ;
    USE SIGNAL ;
    PORT
      LAYER M3 ;
        RECT  16.596 17.136 16.614 17.28 ;
    END
  END o[150]
  PIN o[151]
    DIRECTION OUTPUT ;
    USE SIGNAL ;
    PORT
      LAYER M5 ;
        RECT  16.656 17.088 16.68 17.28 ;
    END
  END o[151]
  PIN o[152]
    DIRECTION OUTPUT ;
    USE SIGNAL ;
    PORT
      LAYER M3 ;
        RECT  16.776 17.136 16.794 17.28 ;
    END
  END o[152]
  PIN o[153]
    DIRECTION OUTPUT ;
    USE SIGNAL ;
    PORT
      LAYER M5 ;
        RECT  16.848 17.088 16.872 17.28 ;
    END
  END o[153]
  PIN o[154]
    DIRECTION OUTPUT ;
    USE SIGNAL ;
    PORT
      LAYER M3 ;
        RECT  16.956 17.136 16.974 17.28 ;
    END
  END o[154]
  PIN o[155]
    DIRECTION OUTPUT ;
    USE SIGNAL ;
    PORT
      LAYER M5 ;
        RECT  17.04 17.088 17.064 17.28 ;
    END
  END o[155]
  PIN o[156]
    DIRECTION OUTPUT ;
    USE SIGNAL ;
    PORT
      LAYER M3 ;
        RECT  17.172 17.136 17.19 17.28 ;
    END
  END o[156]
  PIN o[157]
    DIRECTION OUTPUT ;
    USE SIGNAL ;
    PORT
      LAYER M5 ;
        RECT  17.232 17.088 17.256 17.28 ;
    END
  END o[157]
  PIN o[158]
    DIRECTION OUTPUT ;
    USE SIGNAL ;
    PORT
      LAYER M3 ;
        RECT  17.352 17.136 17.37 17.28 ;
    END
  END o[158]
  PIN o[159]
    DIRECTION OUTPUT ;
    USE SIGNAL ;
    PORT
      LAYER M5 ;
        RECT  17.424 17.088 17.448 17.28 ;
    END
  END o[159]
  PIN o[15]
    DIRECTION OUTPUT ;
    USE SIGNAL ;
    PORT
      LAYER M5 ;
        RECT  3.648 17.088 3.672 17.28 ;
    END
  END o[15]
  PIN o[160]
    DIRECTION OUTPUT ;
    USE SIGNAL ;
    PORT
      LAYER M3 ;
        RECT  17.532 17.136 17.55 17.28 ;
    END
  END o[160]
  PIN o[161]
    DIRECTION OUTPUT ;
    USE SIGNAL ;
    PORT
      LAYER M5 ;
        RECT  17.616 17.088 17.64 17.28 ;
    END
  END o[161]
  PIN o[162]
    DIRECTION OUTPUT ;
    USE SIGNAL ;
    PORT
      LAYER M3 ;
        RECT  17.748 17.136 17.766 17.28 ;
    END
  END o[162]
  PIN o[163]
    DIRECTION OUTPUT ;
    USE SIGNAL ;
    PORT
      LAYER M5 ;
        RECT  17.808 17.088 17.832 17.28 ;
    END
  END o[163]
  PIN o[164]
    DIRECTION OUTPUT ;
    USE SIGNAL ;
    PORT
      LAYER M3 ;
        RECT  17.928 17.136 17.946 17.28 ;
    END
  END o[164]
  PIN o[165]
    DIRECTION OUTPUT ;
    USE SIGNAL ;
    PORT
      LAYER M5 ;
        RECT  18 17.088 18.024 17.28 ;
    END
  END o[165]
  PIN o[166]
    DIRECTION OUTPUT ;
    USE SIGNAL ;
    PORT
      LAYER M3 ;
        RECT  18.108 17.136 18.126 17.28 ;
    END
  END o[166]
  PIN o[167]
    DIRECTION OUTPUT ;
    USE SIGNAL ;
    PORT
      LAYER M5 ;
        RECT  18.192 17.088 18.216 17.28 ;
    END
  END o[167]
  PIN o[168]
    DIRECTION OUTPUT ;
    USE SIGNAL ;
    PORT
      LAYER M3 ;
        RECT  18.324 17.136 18.342 17.28 ;
    END
  END o[168]
  PIN o[169]
    DIRECTION OUTPUT ;
    USE SIGNAL ;
    PORT
      LAYER M5 ;
        RECT  18.384 17.088 18.408 17.28 ;
    END
  END o[169]
  PIN o[16]
    DIRECTION OUTPUT ;
    USE SIGNAL ;
    PORT
      LAYER M3 ;
        RECT  3.744 17.136 3.762 17.28 ;
    END
  END o[16]
  PIN o[170]
    DIRECTION OUTPUT ;
    USE SIGNAL ;
    PORT
      LAYER M3 ;
        RECT  18.504 17.136 18.522 17.28 ;
    END
  END o[170]
  PIN o[171]
    DIRECTION OUTPUT ;
    USE SIGNAL ;
    PORT
      LAYER M5 ;
        RECT  18.576 17.088 18.6 17.28 ;
    END
  END o[171]
  PIN o[172]
    DIRECTION OUTPUT ;
    USE SIGNAL ;
    PORT
      LAYER M3 ;
        RECT  18.684 17.136 18.702 17.28 ;
    END
  END o[172]
  PIN o[173]
    DIRECTION OUTPUT ;
    USE SIGNAL ;
    PORT
      LAYER M5 ;
        RECT  18.768 17.088 18.792 17.28 ;
    END
  END o[173]
  PIN o[174]
    DIRECTION OUTPUT ;
    USE SIGNAL ;
    PORT
      LAYER M3 ;
        RECT  18.9 17.136 18.918 17.28 ;
    END
  END o[174]
  PIN o[175]
    DIRECTION OUTPUT ;
    USE SIGNAL ;
    PORT
      LAYER M5 ;
        RECT  18.96 17.088 18.984 17.28 ;
    END
  END o[175]
  PIN o[176]
    DIRECTION OUTPUT ;
    USE SIGNAL ;
    PORT
      LAYER M3 ;
        RECT  19.08 17.136 19.098 17.28 ;
    END
  END o[176]
  PIN o[177]
    DIRECTION OUTPUT ;
    USE SIGNAL ;
    PORT
      LAYER M5 ;
        RECT  19.152 17.088 19.176 17.28 ;
    END
  END o[177]
  PIN o[178]
    DIRECTION OUTPUT ;
    USE SIGNAL ;
    PORT
      LAYER M3 ;
        RECT  19.26 17.136 19.278 17.28 ;
    END
  END o[178]
  PIN o[179]
    DIRECTION OUTPUT ;
    USE SIGNAL ;
    PORT
      LAYER M5 ;
        RECT  19.344 17.088 19.368 17.28 ;
    END
  END o[179]
  PIN o[17]
    DIRECTION OUTPUT ;
    USE SIGNAL ;
    PORT
      LAYER M5 ;
        RECT  3.84 17.088 3.864 17.28 ;
    END
  END o[17]
  PIN o[180]
    DIRECTION OUTPUT ;
    USE SIGNAL ;
    PORT
      LAYER M3 ;
        RECT  19.476 17.136 19.494 17.28 ;
    END
  END o[180]
  PIN o[181]
    DIRECTION OUTPUT ;
    USE SIGNAL ;
    PORT
      LAYER M5 ;
        RECT  19.536 17.088 19.56 17.28 ;
    END
  END o[181]
  PIN o[182]
    DIRECTION OUTPUT ;
    USE SIGNAL ;
    PORT
      LAYER M3 ;
        RECT  19.656 17.136 19.674 17.28 ;
    END
  END o[182]
  PIN o[183]
    DIRECTION OUTPUT ;
    USE SIGNAL ;
    PORT
      LAYER M5 ;
        RECT  19.728 17.088 19.752 17.28 ;
    END
  END o[183]
  PIN o[184]
    DIRECTION OUTPUT ;
    USE SIGNAL ;
    PORT
      LAYER M3 ;
        RECT  19.836 17.136 19.854 17.28 ;
    END
  END o[184]
  PIN o[185]
    DIRECTION OUTPUT ;
    USE SIGNAL ;
    PORT
      LAYER M5 ;
        RECT  19.92 17.088 19.944 17.28 ;
    END
  END o[185]
  PIN o[186]
    DIRECTION OUTPUT ;
    USE SIGNAL ;
    PORT
      LAYER M3 ;
        RECT  20.052 17.136 20.07 17.28 ;
    END
  END o[186]
  PIN o[187]
    DIRECTION OUTPUT ;
    USE SIGNAL ;
    PORT
      LAYER M5 ;
        RECT  20.112 17.088 20.136 17.28 ;
    END
  END o[187]
  PIN o[188]
    DIRECTION OUTPUT ;
    USE SIGNAL ;
    PORT
      LAYER M3 ;
        RECT  20.232 17.136 20.25 17.28 ;
    END
  END o[188]
  PIN o[189]
    DIRECTION OUTPUT ;
    USE SIGNAL ;
    PORT
      LAYER M5 ;
        RECT  20.304 17.088 20.328 17.28 ;
    END
  END o[189]
  PIN o[18]
    DIRECTION OUTPUT ;
    USE SIGNAL ;
    PORT
      LAYER M3 ;
        RECT  3.924 17.136 3.942 17.28 ;
    END
  END o[18]
  PIN o[190]
    DIRECTION OUTPUT ;
    USE SIGNAL ;
    PORT
      LAYER M3 ;
        RECT  20.412 17.136 20.43 17.28 ;
    END
  END o[190]
  PIN o[191]
    DIRECTION OUTPUT ;
    USE SIGNAL ;
    PORT
      LAYER M5 ;
        RECT  20.496 17.088 20.52 17.28 ;
    END
  END o[191]
  PIN o[192]
    DIRECTION OUTPUT ;
    USE SIGNAL ;
    PORT
      LAYER M3 ;
        RECT  20.628 17.136 20.646 17.28 ;
    END
  END o[192]
  PIN o[193]
    DIRECTION OUTPUT ;
    USE SIGNAL ;
    PORT
      LAYER M5 ;
        RECT  20.688 17.088 20.712 17.28 ;
    END
  END o[193]
  PIN o[194]
    DIRECTION OUTPUT ;
    USE SIGNAL ;
    PORT
      LAYER M3 ;
        RECT  20.808 17.136 20.826 17.28 ;
    END
  END o[194]
  PIN o[195]
    DIRECTION OUTPUT ;
    USE SIGNAL ;
    PORT
      LAYER M5 ;
        RECT  20.88 17.088 20.904 17.28 ;
    END
  END o[195]
  PIN o[196]
    DIRECTION OUTPUT ;
    USE SIGNAL ;
    PORT
      LAYER M3 ;
        RECT  20.988 17.136 21.006 17.28 ;
    END
  END o[196]
  PIN o[197]
    DIRECTION OUTPUT ;
    USE SIGNAL ;
    PORT
      LAYER M5 ;
        RECT  21.072 17.088 21.096 17.28 ;
    END
  END o[197]
  PIN o[198]
    DIRECTION OUTPUT ;
    USE SIGNAL ;
    PORT
      LAYER M3 ;
        RECT  21.204 17.136 21.222 17.28 ;
    END
  END o[198]
  PIN o[199]
    DIRECTION OUTPUT ;
    USE SIGNAL ;
    PORT
      LAYER M5 ;
        RECT  21.264 17.088 21.288 17.28 ;
    END
  END o[199]
  PIN o[19]
    DIRECTION OUTPUT ;
    USE SIGNAL ;
    PORT
      LAYER M5 ;
        RECT  4.032 17.088 4.056 17.28 ;
    END
  END o[19]
  PIN o[1]
    DIRECTION OUTPUT ;
    USE SIGNAL ;
    PORT
      LAYER M5 ;
        RECT  2.304 17.088 2.328 17.28 ;
    END
  END o[1]
  PIN o[200]
    DIRECTION OUTPUT ;
    USE SIGNAL ;
    PORT
      LAYER M3 ;
        RECT  21.384 17.136 21.402 17.28 ;
    END
  END o[200]
  PIN o[201]
    DIRECTION OUTPUT ;
    USE SIGNAL ;
    PORT
      LAYER M5 ;
        RECT  21.456 17.088 21.48 17.28 ;
    END
  END o[201]
  PIN o[202]
    DIRECTION OUTPUT ;
    USE SIGNAL ;
    PORT
      LAYER M3 ;
        RECT  21.564 17.136 21.582 17.28 ;
    END
  END o[202]
  PIN o[203]
    DIRECTION OUTPUT ;
    USE SIGNAL ;
    PORT
      LAYER M5 ;
        RECT  21.648 17.088 21.672 17.28 ;
    END
  END o[203]
  PIN o[204]
    DIRECTION OUTPUT ;
    USE SIGNAL ;
    PORT
      LAYER M3 ;
        RECT  21.78 17.136 21.798 17.28 ;
    END
  END o[204]
  PIN o[205]
    DIRECTION OUTPUT ;
    USE SIGNAL ;
    PORT
      LAYER M5 ;
        RECT  21.84 17.088 21.864 17.28 ;
    END
  END o[205]
  PIN o[206]
    DIRECTION OUTPUT ;
    USE SIGNAL ;
    PORT
      LAYER M3 ;
        RECT  21.96 17.136 21.978 17.28 ;
    END
  END o[206]
  PIN o[207]
    DIRECTION OUTPUT ;
    USE SIGNAL ;
    PORT
      LAYER M5 ;
        RECT  22.032 17.088 22.056 17.28 ;
    END
  END o[207]
  PIN o[208]
    DIRECTION OUTPUT ;
    USE SIGNAL ;
    PORT
      LAYER M3 ;
        RECT  22.14 17.136 22.158 17.28 ;
    END
  END o[208]
  PIN o[209]
    DIRECTION OUTPUT ;
    USE SIGNAL ;
    PORT
      LAYER M5 ;
        RECT  22.224 17.088 22.248 17.28 ;
    END
  END o[209]
  PIN o[20]
    DIRECTION OUTPUT ;
    USE SIGNAL ;
    PORT
      LAYER M3 ;
        RECT  4.104 17.136 4.122 17.28 ;
    END
  END o[20]
  PIN o[210]
    DIRECTION OUTPUT ;
    USE SIGNAL ;
    PORT
      LAYER M3 ;
        RECT  22.356 17.136 22.374 17.28 ;
    END
  END o[210]
  PIN o[211]
    DIRECTION OUTPUT ;
    USE SIGNAL ;
    PORT
      LAYER M5 ;
        RECT  22.416 17.088 22.44 17.28 ;
    END
  END o[211]
  PIN o[212]
    DIRECTION OUTPUT ;
    USE SIGNAL ;
    PORT
      LAYER M3 ;
        RECT  22.536 17.136 22.554 17.28 ;
    END
  END o[212]
  PIN o[213]
    DIRECTION OUTPUT ;
    USE SIGNAL ;
    PORT
      LAYER M5 ;
        RECT  22.608 17.088 22.632 17.28 ;
    END
  END o[213]
  PIN o[214]
    DIRECTION OUTPUT ;
    USE SIGNAL ;
    PORT
      LAYER M3 ;
        RECT  22.716 17.136 22.734 17.28 ;
    END
  END o[214]
  PIN o[215]
    DIRECTION OUTPUT ;
    USE SIGNAL ;
    PORT
      LAYER M5 ;
        RECT  22.8 17.088 22.824 17.28 ;
    END
  END o[215]
  PIN o[216]
    DIRECTION OUTPUT ;
    USE SIGNAL ;
    PORT
      LAYER M3 ;
        RECT  22.932 17.136 22.95 17.28 ;
    END
  END o[216]
  PIN o[217]
    DIRECTION OUTPUT ;
    USE SIGNAL ;
    PORT
      LAYER M5 ;
        RECT  22.992 17.088 23.016 17.28 ;
    END
  END o[217]
  PIN o[218]
    DIRECTION OUTPUT ;
    USE SIGNAL ;
    PORT
      LAYER M3 ;
        RECT  23.112 17.136 23.13 17.28 ;
    END
  END o[218]
  PIN o[219]
    DIRECTION OUTPUT ;
    USE SIGNAL ;
    PORT
      LAYER M5 ;
        RECT  23.184 17.088 23.208 17.28 ;
    END
  END o[219]
  PIN o[21]
    DIRECTION OUTPUT ;
    USE SIGNAL ;
    PORT
      LAYER M5 ;
        RECT  4.224 17.088 4.248 17.28 ;
    END
  END o[21]
  PIN o[220]
    DIRECTION OUTPUT ;
    USE SIGNAL ;
    PORT
      LAYER M3 ;
        RECT  23.292 17.136 23.31 17.28 ;
    END
  END o[220]
  PIN o[221]
    DIRECTION OUTPUT ;
    USE SIGNAL ;
    PORT
      LAYER M5 ;
        RECT  23.376 17.088 23.4 17.28 ;
    END
  END o[221]
  PIN o[222]
    DIRECTION OUTPUT ;
    USE SIGNAL ;
    PORT
      LAYER M3 ;
        RECT  23.508 17.136 23.526 17.28 ;
    END
  END o[222]
  PIN o[223]
    DIRECTION OUTPUT ;
    USE SIGNAL ;
    PORT
      LAYER M5 ;
        RECT  23.568 17.088 23.592 17.28 ;
    END
  END o[223]
  PIN o[224]
    DIRECTION OUTPUT ;
    USE SIGNAL ;
    PORT
      LAYER M3 ;
        RECT  23.688 17.136 23.706 17.28 ;
    END
  END o[224]
  PIN o[225]
    DIRECTION OUTPUT ;
    USE SIGNAL ;
    PORT
      LAYER M5 ;
        RECT  23.76 17.088 23.784 17.28 ;
    END
  END o[225]
  PIN o[226]
    DIRECTION OUTPUT ;
    USE SIGNAL ;
    PORT
      LAYER M3 ;
        RECT  23.868 17.136 23.886 17.28 ;
    END
  END o[226]
  PIN o[227]
    DIRECTION OUTPUT ;
    USE SIGNAL ;
    PORT
      LAYER M5 ;
        RECT  23.952 17.088 23.976 17.28 ;
    END
  END o[227]
  PIN o[228]
    DIRECTION OUTPUT ;
    USE SIGNAL ;
    PORT
      LAYER M3 ;
        RECT  24.084 17.136 24.102 17.28 ;
    END
  END o[228]
  PIN o[229]
    DIRECTION OUTPUT ;
    USE SIGNAL ;
    PORT
      LAYER M5 ;
        RECT  24.144 17.088 24.168 17.28 ;
    END
  END o[229]
  PIN o[22]
    DIRECTION OUTPUT ;
    USE SIGNAL ;
    PORT
      LAYER M3 ;
        RECT  4.32 17.136 4.338 17.28 ;
    END
  END o[22]
  PIN o[230]
    DIRECTION OUTPUT ;
    USE SIGNAL ;
    PORT
      LAYER M3 ;
        RECT  24.264 17.136 24.282 17.28 ;
    END
  END o[230]
  PIN o[231]
    DIRECTION OUTPUT ;
    USE SIGNAL ;
    PORT
      LAYER M5 ;
        RECT  24.336 17.088 24.36 17.28 ;
    END
  END o[231]
  PIN o[232]
    DIRECTION OUTPUT ;
    USE SIGNAL ;
    PORT
      LAYER M3 ;
        RECT  24.444 17.136 24.462 17.28 ;
    END
  END o[232]
  PIN o[233]
    DIRECTION OUTPUT ;
    USE SIGNAL ;
    PORT
      LAYER M5 ;
        RECT  24.528 17.088 24.552 17.28 ;
    END
  END o[233]
  PIN o[234]
    DIRECTION OUTPUT ;
    USE SIGNAL ;
    PORT
      LAYER M3 ;
        RECT  24.66 17.136 24.678 17.28 ;
    END
  END o[234]
  PIN o[235]
    DIRECTION OUTPUT ;
    USE SIGNAL ;
    PORT
      LAYER M5 ;
        RECT  24.72 17.088 24.744 17.28 ;
    END
  END o[235]
  PIN o[236]
    DIRECTION OUTPUT ;
    USE SIGNAL ;
    PORT
      LAYER M3 ;
        RECT  24.84 17.136 24.858 17.28 ;
    END
  END o[236]
  PIN o[237]
    DIRECTION OUTPUT ;
    USE SIGNAL ;
    PORT
      LAYER M5 ;
        RECT  24.912 17.088 24.936 17.28 ;
    END
  END o[237]
  PIN o[238]
    DIRECTION OUTPUT ;
    USE SIGNAL ;
    PORT
      LAYER M3 ;
        RECT  25.02 17.136 25.038 17.28 ;
    END
  END o[238]
  PIN o[239]
    DIRECTION OUTPUT ;
    USE SIGNAL ;
    PORT
      LAYER M5 ;
        RECT  25.104 17.088 25.128 17.28 ;
    END
  END o[239]
  PIN o[23]
    DIRECTION OUTPUT ;
    USE SIGNAL ;
    PORT
      LAYER M5 ;
        RECT  4.416 17.088 4.44 17.28 ;
    END
  END o[23]
  PIN o[240]
    DIRECTION OUTPUT ;
    USE SIGNAL ;
    PORT
      LAYER M3 ;
        RECT  25.236 17.136 25.254 17.28 ;
    END
  END o[240]
  PIN o[241]
    DIRECTION OUTPUT ;
    USE SIGNAL ;
    PORT
      LAYER M5 ;
        RECT  25.296 17.088 25.32 17.28 ;
    END
  END o[241]
  PIN o[242]
    DIRECTION OUTPUT ;
    USE SIGNAL ;
    PORT
      LAYER M3 ;
        RECT  25.416 17.136 25.434 17.28 ;
    END
  END o[242]
  PIN o[243]
    DIRECTION OUTPUT ;
    USE SIGNAL ;
    PORT
      LAYER M5 ;
        RECT  25.488 17.088 25.512 17.28 ;
    END
  END o[243]
  PIN o[244]
    DIRECTION OUTPUT ;
    USE SIGNAL ;
    PORT
      LAYER M3 ;
        RECT  25.596 17.136 25.614 17.28 ;
    END
  END o[244]
  PIN o[245]
    DIRECTION OUTPUT ;
    USE SIGNAL ;
    PORT
      LAYER M5 ;
        RECT  25.68 17.088 25.704 17.28 ;
    END
  END o[245]
  PIN o[246]
    DIRECTION OUTPUT ;
    USE SIGNAL ;
    PORT
      LAYER M3 ;
        RECT  25.776 17.136 25.794 17.28 ;
    END
  END o[246]
  PIN o[247]
    DIRECTION OUTPUT ;
    USE SIGNAL ;
    PORT
      LAYER M5 ;
        RECT  25.872 17.088 25.896 17.28 ;
    END
  END o[247]
  PIN o[248]
    DIRECTION OUTPUT ;
    USE SIGNAL ;
    PORT
      LAYER M3 ;
        RECT  25.992 17.136 26.01 17.28 ;
    END
  END o[248]
  PIN o[249]
    DIRECTION OUTPUT ;
    USE SIGNAL ;
    PORT
      LAYER M5 ;
        RECT  26.064 17.088 26.088 17.28 ;
    END
  END o[249]
  PIN o[24]
    DIRECTION OUTPUT ;
    USE SIGNAL ;
    PORT
      LAYER M3 ;
        RECT  4.5 17.136 4.518 17.28 ;
    END
  END o[24]
  PIN o[250]
    DIRECTION OUTPUT ;
    USE SIGNAL ;
    PORT
      LAYER M3 ;
        RECT  26.172 17.136 26.19 17.28 ;
    END
  END o[250]
  PIN o[251]
    DIRECTION OUTPUT ;
    USE SIGNAL ;
    PORT
      LAYER M5 ;
        RECT  26.256 17.088 26.28 17.28 ;
    END
  END o[251]
  PIN o[252]
    DIRECTION OUTPUT ;
    USE SIGNAL ;
    PORT
      LAYER M3 ;
        RECT  26.352 17.136 26.37 17.28 ;
    END
  END o[252]
  PIN o[253]
    DIRECTION OUTPUT ;
    USE SIGNAL ;
    PORT
      LAYER M5 ;
        RECT  26.448 17.088 26.472 17.28 ;
    END
  END o[253]
  PIN o[254]
    DIRECTION OUTPUT ;
    USE SIGNAL ;
    PORT
      LAYER M3 ;
        RECT  26.568 17.136 26.586 17.28 ;
    END
  END o[254]
  PIN o[255]
    DIRECTION OUTPUT ;
    USE SIGNAL ;
    PORT
      LAYER M5 ;
        RECT  26.64 17.088 26.664 17.28 ;
    END
  END o[255]
  PIN o[256]
    DIRECTION OUTPUT ;
    USE SIGNAL ;
    PORT
      LAYER M3 ;
        RECT  26.748 17.136 26.766 17.28 ;
    END
  END o[256]
  PIN o[257]
    DIRECTION OUTPUT ;
    USE SIGNAL ;
    PORT
      LAYER M5 ;
        RECT  26.832 17.088 26.856 17.28 ;
    END
  END o[257]
  PIN o[258]
    DIRECTION OUTPUT ;
    USE SIGNAL ;
    PORT
      LAYER M3 ;
        RECT  26.928 17.136 26.946 17.28 ;
    END
  END o[258]
  PIN o[259]
    DIRECTION OUTPUT ;
    USE SIGNAL ;
    PORT
      LAYER M5 ;
        RECT  27.024 17.088 27.048 17.28 ;
    END
  END o[259]
  PIN o[25]
    DIRECTION OUTPUT ;
    USE SIGNAL ;
    PORT
      LAYER M5 ;
        RECT  4.608 17.088 4.632 17.28 ;
    END
  END o[25]
  PIN o[260]
    DIRECTION OUTPUT ;
    USE SIGNAL ;
    PORT
      LAYER M3 ;
        RECT  27.144 17.136 27.162 17.28 ;
    END
  END o[260]
  PIN o[261]
    DIRECTION OUTPUT ;
    USE SIGNAL ;
    PORT
      LAYER M5 ;
        RECT  27.216 17.088 27.24 17.28 ;
    END
  END o[261]
  PIN o[262]
    DIRECTION OUTPUT ;
    USE SIGNAL ;
    PORT
      LAYER M3 ;
        RECT  27.324 17.136 27.342 17.28 ;
    END
  END o[262]
  PIN o[263]
    DIRECTION OUTPUT ;
    USE SIGNAL ;
    PORT
      LAYER M5 ;
        RECT  27.408 17.088 27.432 17.28 ;
    END
  END o[263]
  PIN o[264]
    DIRECTION OUTPUT ;
    USE SIGNAL ;
    PORT
      LAYER M3 ;
        RECT  27.504 17.136 27.522 17.28 ;
    END
  END o[264]
  PIN o[265]
    DIRECTION OUTPUT ;
    USE SIGNAL ;
    PORT
      LAYER M5 ;
        RECT  27.6 17.088 27.624 17.28 ;
    END
  END o[265]
  PIN o[266]
    DIRECTION OUTPUT ;
    USE SIGNAL ;
    PORT
      LAYER M3 ;
        RECT  27.72 17.136 27.738 17.28 ;
    END
  END o[266]
  PIN o[267]
    DIRECTION OUTPUT ;
    USE SIGNAL ;
    PORT
      LAYER M5 ;
        RECT  27.792 17.088 27.816 17.28 ;
    END
  END o[267]
  PIN o[268]
    DIRECTION OUTPUT ;
    USE SIGNAL ;
    PORT
      LAYER M3 ;
        RECT  27.9 17.136 27.918 17.28 ;
    END
  END o[268]
  PIN o[269]
    DIRECTION OUTPUT ;
    USE SIGNAL ;
    PORT
      LAYER M5 ;
        RECT  27.984 17.088 28.008 17.28 ;
    END
  END o[269]
  PIN o[26]
    DIRECTION OUTPUT ;
    USE SIGNAL ;
    PORT
      LAYER M3 ;
        RECT  4.68 17.136 4.698 17.28 ;
    END
  END o[26]
  PIN o[270]
    DIRECTION OUTPUT ;
    USE SIGNAL ;
    PORT
      LAYER M3 ;
        RECT  28.08 17.136 28.098 17.28 ;
    END
  END o[270]
  PIN o[271]
    DIRECTION OUTPUT ;
    USE SIGNAL ;
    PORT
      LAYER M5 ;
        RECT  28.176 17.088 28.2 17.28 ;
    END
  END o[271]
  PIN o[272]
    DIRECTION OUTPUT ;
    USE SIGNAL ;
    PORT
      LAYER M3 ;
        RECT  28.296 17.136 28.314 17.28 ;
    END
  END o[272]
  PIN o[273]
    DIRECTION OUTPUT ;
    USE SIGNAL ;
    PORT
      LAYER M5 ;
        RECT  28.368 17.088 28.392 17.28 ;
    END
  END o[273]
  PIN o[274]
    DIRECTION OUTPUT ;
    USE SIGNAL ;
    PORT
      LAYER M3 ;
        RECT  28.476 17.136 28.494 17.28 ;
    END
  END o[274]
  PIN o[275]
    DIRECTION OUTPUT ;
    USE SIGNAL ;
    PORT
      LAYER M5 ;
        RECT  28.56 17.088 28.584 17.28 ;
    END
  END o[275]
  PIN o[276]
    DIRECTION OUTPUT ;
    USE SIGNAL ;
    PORT
      LAYER M3 ;
        RECT  28.656 17.136 28.674 17.28 ;
    END
  END o[276]
  PIN o[277]
    DIRECTION OUTPUT ;
    USE SIGNAL ;
    PORT
      LAYER M5 ;
        RECT  28.752 17.088 28.776 17.28 ;
    END
  END o[277]
  PIN o[278]
    DIRECTION OUTPUT ;
    USE SIGNAL ;
    PORT
      LAYER M3 ;
        RECT  28.872 17.136 28.89 17.28 ;
    END
  END o[278]
  PIN o[279]
    DIRECTION OUTPUT ;
    USE SIGNAL ;
    PORT
      LAYER M5 ;
        RECT  28.944 17.088 28.968 17.28 ;
    END
  END o[279]
  PIN o[27]
    DIRECTION OUTPUT ;
    USE SIGNAL ;
    PORT
      LAYER M5 ;
        RECT  4.8 17.088 4.824 17.28 ;
    END
  END o[27]
  PIN o[280]
    DIRECTION OUTPUT ;
    USE SIGNAL ;
    PORT
      LAYER M3 ;
        RECT  29.052 17.136 29.07 17.28 ;
    END
  END o[280]
  PIN o[281]
    DIRECTION OUTPUT ;
    USE SIGNAL ;
    PORT
      LAYER M5 ;
        RECT  29.136 17.088 29.16 17.28 ;
    END
  END o[281]
  PIN o[282]
    DIRECTION OUTPUT ;
    USE SIGNAL ;
    PORT
      LAYER M3 ;
        RECT  29.232 17.136 29.25 17.28 ;
    END
  END o[282]
  PIN o[283]
    DIRECTION OUTPUT ;
    USE SIGNAL ;
    PORT
      LAYER M5 ;
        RECT  29.328 17.088 29.352 17.28 ;
    END
  END o[283]
  PIN o[284]
    DIRECTION OUTPUT ;
    USE SIGNAL ;
    PORT
      LAYER M3 ;
        RECT  29.448 17.136 29.466 17.28 ;
    END
  END o[284]
  PIN o[285]
    DIRECTION OUTPUT ;
    USE SIGNAL ;
    PORT
      LAYER M5 ;
        RECT  29.52 17.088 29.544 17.28 ;
    END
  END o[285]
  PIN o[286]
    DIRECTION OUTPUT ;
    USE SIGNAL ;
    PORT
      LAYER M3 ;
        RECT  29.628 17.136 29.646 17.28 ;
    END
  END o[286]
  PIN o[287]
    DIRECTION OUTPUT ;
    USE SIGNAL ;
    PORT
      LAYER M5 ;
        RECT  29.712 17.088 29.736 17.28 ;
    END
  END o[287]
  PIN o[288]
    DIRECTION OUTPUT ;
    USE SIGNAL ;
    PORT
      LAYER M3 ;
        RECT  29.808 17.136 29.826 17.28 ;
    END
  END o[288]
  PIN o[289]
    DIRECTION OUTPUT ;
    USE SIGNAL ;
    PORT
      LAYER M5 ;
        RECT  29.904 17.088 29.928 17.28 ;
    END
  END o[289]
  PIN o[28]
    DIRECTION OUTPUT ;
    USE SIGNAL ;
    PORT
      LAYER M3 ;
        RECT  4.896 17.136 4.914 17.28 ;
    END
  END o[28]
  PIN o[290]
    DIRECTION OUTPUT ;
    USE SIGNAL ;
    PORT
      LAYER M3 ;
        RECT  30.024 17.136 30.042 17.28 ;
    END
  END o[290]
  PIN o[291]
    DIRECTION OUTPUT ;
    USE SIGNAL ;
    PORT
      LAYER M5 ;
        RECT  30.096 17.088 30.12 17.28 ;
    END
  END o[291]
  PIN o[292]
    DIRECTION OUTPUT ;
    USE SIGNAL ;
    PORT
      LAYER M3 ;
        RECT  30.204 17.136 30.222 17.28 ;
    END
  END o[292]
  PIN o[293]
    DIRECTION OUTPUT ;
    USE SIGNAL ;
    PORT
      LAYER M5 ;
        RECT  30.288 17.088 30.312 17.28 ;
    END
  END o[293]
  PIN o[294]
    DIRECTION OUTPUT ;
    USE SIGNAL ;
    PORT
      LAYER M3 ;
        RECT  30.384 17.136 30.402 17.28 ;
    END
  END o[294]
  PIN o[295]
    DIRECTION OUTPUT ;
    USE SIGNAL ;
    PORT
      LAYER M5 ;
        RECT  30.48 17.088 30.504 17.28 ;
    END
  END o[295]
  PIN o[296]
    DIRECTION OUTPUT ;
    USE SIGNAL ;
    PORT
      LAYER M3 ;
        RECT  30.6 17.136 30.618 17.28 ;
    END
  END o[296]
  PIN o[297]
    DIRECTION OUTPUT ;
    USE SIGNAL ;
    PORT
      LAYER M5 ;
        RECT  30.672 17.088 30.696 17.28 ;
    END
  END o[297]
  PIN o[298]
    DIRECTION OUTPUT ;
    USE SIGNAL ;
    PORT
      LAYER M3 ;
        RECT  30.78 17.136 30.798 17.28 ;
    END
  END o[298]
  PIN o[299]
    DIRECTION OUTPUT ;
    USE SIGNAL ;
    PORT
      LAYER M5 ;
        RECT  30.864 17.088 30.888 17.28 ;
    END
  END o[299]
  PIN o[29]
    DIRECTION OUTPUT ;
    USE SIGNAL ;
    PORT
      LAYER M5 ;
        RECT  4.992 17.088 5.016 17.28 ;
    END
  END o[29]
  PIN o[2]
    DIRECTION OUTPUT ;
    USE SIGNAL ;
    PORT
      LAYER M3 ;
        RECT  2.376 17.136 2.394 17.28 ;
    END
  END o[2]
  PIN o[300]
    DIRECTION OUTPUT ;
    USE SIGNAL ;
    PORT
      LAYER M3 ;
        RECT  30.96 17.136 30.978 17.28 ;
    END
  END o[300]
  PIN o[301]
    DIRECTION OUTPUT ;
    USE SIGNAL ;
    PORT
      LAYER M5 ;
        RECT  31.056 17.088 31.08 17.28 ;
    END
  END o[301]
  PIN o[302]
    DIRECTION OUTPUT ;
    USE SIGNAL ;
    PORT
      LAYER M3 ;
        RECT  31.176 17.136 31.194 17.28 ;
    END
  END o[302]
  PIN o[303]
    DIRECTION OUTPUT ;
    USE SIGNAL ;
    PORT
      LAYER M5 ;
        RECT  31.248 17.088 31.272 17.28 ;
    END
  END o[303]
  PIN o[304]
    DIRECTION OUTPUT ;
    USE SIGNAL ;
    PORT
      LAYER M3 ;
        RECT  31.356 17.136 31.374 17.28 ;
    END
  END o[304]
  PIN o[305]
    DIRECTION OUTPUT ;
    USE SIGNAL ;
    PORT
      LAYER M5 ;
        RECT  31.44 17.088 31.464 17.28 ;
    END
  END o[305]
  PIN o[306]
    DIRECTION OUTPUT ;
    USE SIGNAL ;
    PORT
      LAYER M3 ;
        RECT  31.536 17.136 31.554 17.28 ;
    END
  END o[306]
  PIN o[307]
    DIRECTION OUTPUT ;
    USE SIGNAL ;
    PORT
      LAYER M5 ;
        RECT  31.632 17.088 31.656 17.28 ;
    END
  END o[307]
  PIN o[308]
    DIRECTION OUTPUT ;
    USE SIGNAL ;
    PORT
      LAYER M3 ;
        RECT  31.752 17.136 31.77 17.28 ;
    END
  END o[308]
  PIN o[309]
    DIRECTION OUTPUT ;
    USE SIGNAL ;
    PORT
      LAYER M5 ;
        RECT  31.824 17.088 31.848 17.28 ;
    END
  END o[309]
  PIN o[30]
    DIRECTION OUTPUT ;
    USE SIGNAL ;
    PORT
      LAYER M3 ;
        RECT  5.076 17.136 5.094 17.28 ;
    END
  END o[30]
  PIN o[310]
    DIRECTION OUTPUT ;
    USE SIGNAL ;
    PORT
      LAYER M3 ;
        RECT  31.932 17.136 31.95 17.28 ;
    END
  END o[310]
  PIN o[311]
    DIRECTION OUTPUT ;
    USE SIGNAL ;
    PORT
      LAYER M5 ;
        RECT  32.016 17.088 32.04 17.28 ;
    END
  END o[311]
  PIN o[312]
    DIRECTION OUTPUT ;
    USE SIGNAL ;
    PORT
      LAYER M3 ;
        RECT  32.112 17.136 32.13 17.28 ;
    END
  END o[312]
  PIN o[313]
    DIRECTION OUTPUT ;
    USE SIGNAL ;
    PORT
      LAYER M5 ;
        RECT  32.208 17.088 32.232 17.28 ;
    END
  END o[313]
  PIN o[314]
    DIRECTION OUTPUT ;
    USE SIGNAL ;
    PORT
      LAYER M3 ;
        RECT  32.328 17.136 32.346 17.28 ;
    END
  END o[314]
  PIN o[315]
    DIRECTION OUTPUT ;
    USE SIGNAL ;
    PORT
      LAYER M5 ;
        RECT  32.4 17.088 32.424 17.28 ;
    END
  END o[315]
  PIN o[316]
    DIRECTION OUTPUT ;
    USE SIGNAL ;
    PORT
      LAYER M3 ;
        RECT  32.508 17.136 32.526 17.28 ;
    END
  END o[316]
  PIN o[317]
    DIRECTION OUTPUT ;
    USE SIGNAL ;
    PORT
      LAYER M5 ;
        RECT  32.592 17.088 32.616 17.28 ;
    END
  END o[317]
  PIN o[318]
    DIRECTION OUTPUT ;
    USE SIGNAL ;
    PORT
      LAYER M3 ;
        RECT  32.688 17.136 32.706 17.28 ;
    END
  END o[318]
  PIN o[319]
    DIRECTION OUTPUT ;
    USE SIGNAL ;
    PORT
      LAYER M5 ;
        RECT  32.784 17.088 32.808 17.28 ;
    END
  END o[319]
  PIN o[31]
    DIRECTION OUTPUT ;
    USE SIGNAL ;
    PORT
      LAYER M5 ;
        RECT  5.184 17.088 5.208 17.28 ;
    END
  END o[31]
  PIN o[320]
    DIRECTION OUTPUT ;
    USE SIGNAL ;
    PORT
      LAYER M3 ;
        RECT  32.904 17.136 32.922 17.28 ;
    END
  END o[320]
  PIN o[321]
    DIRECTION OUTPUT ;
    USE SIGNAL ;
    PORT
      LAYER M5 ;
        RECT  32.976 17.088 33 17.28 ;
    END
  END o[321]
  PIN o[322]
    DIRECTION OUTPUT ;
    USE SIGNAL ;
    PORT
      LAYER M3 ;
        RECT  33.084 17.136 33.102 17.28 ;
    END
  END o[322]
  PIN o[323]
    DIRECTION OUTPUT ;
    USE SIGNAL ;
    PORT
      LAYER M5 ;
        RECT  33.168 17.088 33.192 17.28 ;
    END
  END o[323]
  PIN o[324]
    DIRECTION OUTPUT ;
    USE SIGNAL ;
    PORT
      LAYER M3 ;
        RECT  33.264 17.136 33.282 17.28 ;
    END
  END o[324]
  PIN o[325]
    DIRECTION OUTPUT ;
    USE SIGNAL ;
    PORT
      LAYER M5 ;
        RECT  33.36 17.088 33.384 17.28 ;
    END
  END o[325]
  PIN o[326]
    DIRECTION OUTPUT ;
    USE SIGNAL ;
    PORT
      LAYER M3 ;
        RECT  33.48 17.136 33.498 17.28 ;
    END
  END o[326]
  PIN o[327]
    DIRECTION OUTPUT ;
    USE SIGNAL ;
    PORT
      LAYER M5 ;
        RECT  33.552 17.088 33.576 17.28 ;
    END
  END o[327]
  PIN o[328]
    DIRECTION OUTPUT ;
    USE SIGNAL ;
    PORT
      LAYER M3 ;
        RECT  33.66 17.136 33.678 17.28 ;
    END
  END o[328]
  PIN o[329]
    DIRECTION OUTPUT ;
    USE SIGNAL ;
    PORT
      LAYER M5 ;
        RECT  33.744 17.088 33.768 17.28 ;
    END
  END o[329]
  PIN o[32]
    DIRECTION OUTPUT ;
    USE SIGNAL ;
    PORT
      LAYER M3 ;
        RECT  5.256 17.136 5.274 17.28 ;
    END
  END o[32]
  PIN o[330]
    DIRECTION OUTPUT ;
    USE SIGNAL ;
    PORT
      LAYER M3 ;
        RECT  33.84 17.136 33.858 17.28 ;
    END
  END o[330]
  PIN o[331]
    DIRECTION OUTPUT ;
    USE SIGNAL ;
    PORT
      LAYER M5 ;
        RECT  33.936 17.088 33.96 17.28 ;
    END
  END o[331]
  PIN o[332]
    DIRECTION OUTPUT ;
    USE SIGNAL ;
    PORT
      LAYER M3 ;
        RECT  34.056 17.136 34.074 17.28 ;
    END
  END o[332]
  PIN o[333]
    DIRECTION OUTPUT ;
    USE SIGNAL ;
    PORT
      LAYER M5 ;
        RECT  34.128 17.088 34.152 17.28 ;
    END
  END o[333]
  PIN o[334]
    DIRECTION OUTPUT ;
    USE SIGNAL ;
    PORT
      LAYER M3 ;
        RECT  34.236 17.136 34.254 17.28 ;
    END
  END o[334]
  PIN o[335]
    DIRECTION OUTPUT ;
    USE SIGNAL ;
    PORT
      LAYER M5 ;
        RECT  34.32 17.088 34.344 17.28 ;
    END
  END o[335]
  PIN o[336]
    DIRECTION OUTPUT ;
    USE SIGNAL ;
    PORT
      LAYER M3 ;
        RECT  34.416 17.136 34.434 17.28 ;
    END
  END o[336]
  PIN o[337]
    DIRECTION OUTPUT ;
    USE SIGNAL ;
    PORT
      LAYER M5 ;
        RECT  34.512 17.088 34.536 17.28 ;
    END
  END o[337]
  PIN o[338]
    DIRECTION OUTPUT ;
    USE SIGNAL ;
    PORT
      LAYER M3 ;
        RECT  34.632 17.136 34.65 17.28 ;
    END
  END o[338]
  PIN o[339]
    DIRECTION OUTPUT ;
    USE SIGNAL ;
    PORT
      LAYER M5 ;
        RECT  34.704 17.088 34.728 17.28 ;
    END
  END o[339]
  PIN o[33]
    DIRECTION OUTPUT ;
    USE SIGNAL ;
    PORT
      LAYER M5 ;
        RECT  5.376 17.088 5.4 17.28 ;
    END
  END o[33]
  PIN o[340]
    DIRECTION OUTPUT ;
    USE SIGNAL ;
    PORT
      LAYER M3 ;
        RECT  34.812 17.136 34.83 17.28 ;
    END
  END o[340]
  PIN o[341]
    DIRECTION OUTPUT ;
    USE SIGNAL ;
    PORT
      LAYER M5 ;
        RECT  34.896 17.088 34.92 17.28 ;
    END
  END o[341]
  PIN o[342]
    DIRECTION OUTPUT ;
    USE SIGNAL ;
    PORT
      LAYER M3 ;
        RECT  34.992 17.136 35.01 17.28 ;
    END
  END o[342]
  PIN o[343]
    DIRECTION OUTPUT ;
    USE SIGNAL ;
    PORT
      LAYER M5 ;
        RECT  35.088 17.088 35.112 17.28 ;
    END
  END o[343]
  PIN o[344]
    DIRECTION OUTPUT ;
    USE SIGNAL ;
    PORT
      LAYER M3 ;
        RECT  35.208 17.136 35.226 17.28 ;
    END
  END o[344]
  PIN o[345]
    DIRECTION OUTPUT ;
    USE SIGNAL ;
    PORT
      LAYER M5 ;
        RECT  35.28 17.088 35.304 17.28 ;
    END
  END o[345]
  PIN o[346]
    DIRECTION OUTPUT ;
    USE SIGNAL ;
    PORT
      LAYER M3 ;
        RECT  35.388 17.136 35.406 17.28 ;
    END
  END o[346]
  PIN o[347]
    DIRECTION OUTPUT ;
    USE SIGNAL ;
    PORT
      LAYER M5 ;
        RECT  35.472 17.088 35.496 17.28 ;
    END
  END o[347]
  PIN o[348]
    DIRECTION OUTPUT ;
    USE SIGNAL ;
    PORT
      LAYER M3 ;
        RECT  35.568 17.136 35.586 17.28 ;
    END
  END o[348]
  PIN o[349]
    DIRECTION OUTPUT ;
    USE SIGNAL ;
    PORT
      LAYER M5 ;
        RECT  35.664 17.088 35.688 17.28 ;
    END
  END o[349]
  PIN o[34]
    DIRECTION OUTPUT ;
    USE SIGNAL ;
    PORT
      LAYER M3 ;
        RECT  5.472 17.136 5.49 17.28 ;
    END
  END o[34]
  PIN o[350]
    DIRECTION OUTPUT ;
    USE SIGNAL ;
    PORT
      LAYER M3 ;
        RECT  35.784 17.136 35.802 17.28 ;
    END
  END o[350]
  PIN o[351]
    DIRECTION OUTPUT ;
    USE SIGNAL ;
    PORT
      LAYER M5 ;
        RECT  35.856 17.088 35.88 17.28 ;
    END
  END o[351]
  PIN o[352]
    DIRECTION OUTPUT ;
    USE SIGNAL ;
    PORT
      LAYER M3 ;
        RECT  35.964 17.136 35.982 17.28 ;
    END
  END o[352]
  PIN o[353]
    DIRECTION OUTPUT ;
    USE SIGNAL ;
    PORT
      LAYER M5 ;
        RECT  36.048 17.088 36.072 17.28 ;
    END
  END o[353]
  PIN o[354]
    DIRECTION OUTPUT ;
    USE SIGNAL ;
    PORT
      LAYER M3 ;
        RECT  36.144 17.136 36.162 17.28 ;
    END
  END o[354]
  PIN o[355]
    DIRECTION OUTPUT ;
    USE SIGNAL ;
    PORT
      LAYER M5 ;
        RECT  36.24 17.088 36.264 17.28 ;
    END
  END o[355]
  PIN o[356]
    DIRECTION OUTPUT ;
    USE SIGNAL ;
    PORT
      LAYER M3 ;
        RECT  36.36 17.136 36.378 17.28 ;
    END
  END o[356]
  PIN o[357]
    DIRECTION OUTPUT ;
    USE SIGNAL ;
    PORT
      LAYER M5 ;
        RECT  36.432 17.088 36.456 17.28 ;
    END
  END o[357]
  PIN o[358]
    DIRECTION OUTPUT ;
    USE SIGNAL ;
    PORT
      LAYER M3 ;
        RECT  36.54 17.136 36.558 17.28 ;
    END
  END o[358]
  PIN o[359]
    DIRECTION OUTPUT ;
    USE SIGNAL ;
    PORT
      LAYER M5 ;
        RECT  36.624 17.088 36.648 17.28 ;
    END
  END o[359]
  PIN o[35]
    DIRECTION OUTPUT ;
    USE SIGNAL ;
    PORT
      LAYER M5 ;
        RECT  5.568 17.088 5.592 17.28 ;
    END
  END o[35]
  PIN o[360]
    DIRECTION OUTPUT ;
    USE SIGNAL ;
    PORT
      LAYER M3 ;
        RECT  36.72 17.136 36.738 17.28 ;
    END
  END o[360]
  PIN o[361]
    DIRECTION OUTPUT ;
    USE SIGNAL ;
    PORT
      LAYER M5 ;
        RECT  36.816 17.088 36.84 17.28 ;
    END
  END o[361]
  PIN o[362]
    DIRECTION OUTPUT ;
    USE SIGNAL ;
    PORT
      LAYER M3 ;
        RECT  36.936 17.136 36.954 17.28 ;
    END
  END o[362]
  PIN o[363]
    DIRECTION OUTPUT ;
    USE SIGNAL ;
    PORT
      LAYER M5 ;
        RECT  37.008 17.088 37.032 17.28 ;
    END
  END o[363]
  PIN o[364]
    DIRECTION OUTPUT ;
    USE SIGNAL ;
    PORT
      LAYER M3 ;
        RECT  37.116 17.136 37.134 17.28 ;
    END
  END o[364]
  PIN o[365]
    DIRECTION OUTPUT ;
    USE SIGNAL ;
    PORT
      LAYER M5 ;
        RECT  37.2 17.088 37.224 17.28 ;
    END
  END o[365]
  PIN o[366]
    DIRECTION OUTPUT ;
    USE SIGNAL ;
    PORT
      LAYER M3 ;
        RECT  37.296 17.136 37.314 17.28 ;
    END
  END o[366]
  PIN o[367]
    DIRECTION OUTPUT ;
    USE SIGNAL ;
    PORT
      LAYER M5 ;
        RECT  37.392 17.088 37.416 17.28 ;
    END
  END o[367]
  PIN o[368]
    DIRECTION OUTPUT ;
    USE SIGNAL ;
    PORT
      LAYER M3 ;
        RECT  37.512 17.136 37.53 17.28 ;
    END
  END o[368]
  PIN o[369]
    DIRECTION OUTPUT ;
    USE SIGNAL ;
    PORT
      LAYER M5 ;
        RECT  37.584 17.088 37.608 17.28 ;
    END
  END o[369]
  PIN o[36]
    DIRECTION OUTPUT ;
    USE SIGNAL ;
    PORT
      LAYER M3 ;
        RECT  5.652 17.136 5.67 17.28 ;
    END
  END o[36]
  PIN o[370]
    DIRECTION OUTPUT ;
    USE SIGNAL ;
    PORT
      LAYER M3 ;
        RECT  37.692 17.136 37.71 17.28 ;
    END
  END o[370]
  PIN o[371]
    DIRECTION OUTPUT ;
    USE SIGNAL ;
    PORT
      LAYER M5 ;
        RECT  37.776 17.088 37.8 17.28 ;
    END
  END o[371]
  PIN o[372]
    DIRECTION OUTPUT ;
    USE SIGNAL ;
    PORT
      LAYER M3 ;
        RECT  37.872 17.136 37.89 17.28 ;
    END
  END o[372]
  PIN o[373]
    DIRECTION OUTPUT ;
    USE SIGNAL ;
    PORT
      LAYER M5 ;
        RECT  37.968 17.088 37.992 17.28 ;
    END
  END o[373]
  PIN o[374]
    DIRECTION OUTPUT ;
    USE SIGNAL ;
    PORT
      LAYER M3 ;
        RECT  38.088 17.136 38.106 17.28 ;
    END
  END o[374]
  PIN o[375]
    DIRECTION OUTPUT ;
    USE SIGNAL ;
    PORT
      LAYER M5 ;
        RECT  38.16 17.088 38.184 17.28 ;
    END
  END o[375]
  PIN o[376]
    DIRECTION OUTPUT ;
    USE SIGNAL ;
    PORT
      LAYER M3 ;
        RECT  38.268 17.136 38.286 17.28 ;
    END
  END o[376]
  PIN o[377]
    DIRECTION OUTPUT ;
    USE SIGNAL ;
    PORT
      LAYER M5 ;
        RECT  38.352 17.088 38.376 17.28 ;
    END
  END o[377]
  PIN o[378]
    DIRECTION OUTPUT ;
    USE SIGNAL ;
    PORT
      LAYER M3 ;
        RECT  38.448 17.136 38.466 17.28 ;
    END
  END o[378]
  PIN o[379]
    DIRECTION OUTPUT ;
    USE SIGNAL ;
    PORT
      LAYER M5 ;
        RECT  38.544 17.088 38.568 17.28 ;
    END
  END o[379]
  PIN o[37]
    DIRECTION OUTPUT ;
    USE SIGNAL ;
    PORT
      LAYER M5 ;
        RECT  5.76 17.088 5.784 17.28 ;
    END
  END o[37]
  PIN o[380]
    DIRECTION OUTPUT ;
    USE SIGNAL ;
    PORT
      LAYER M3 ;
        RECT  38.664 17.136 38.682 17.28 ;
    END
  END o[380]
  PIN o[381]
    DIRECTION OUTPUT ;
    USE SIGNAL ;
    PORT
      LAYER M5 ;
        RECT  38.736 17.088 38.76 17.28 ;
    END
  END o[381]
  PIN o[382]
    DIRECTION OUTPUT ;
    USE SIGNAL ;
    PORT
      LAYER M3 ;
        RECT  38.844 17.136 38.862 17.28 ;
    END
  END o[382]
  PIN o[383]
    DIRECTION OUTPUT ;
    USE SIGNAL ;
    PORT
      LAYER M5 ;
        RECT  38.928 17.088 38.952 17.28 ;
    END
  END o[383]
  PIN o[384]
    DIRECTION OUTPUT ;
    USE SIGNAL ;
    PORT
      LAYER M3 ;
        RECT  39.024 17.136 39.042 17.28 ;
    END
  END o[384]
  PIN o[385]
    DIRECTION OUTPUT ;
    USE SIGNAL ;
    PORT
      LAYER M5 ;
        RECT  39.12 17.088 39.144 17.28 ;
    END
  END o[385]
  PIN o[386]
    DIRECTION OUTPUT ;
    USE SIGNAL ;
    PORT
      LAYER M3 ;
        RECT  39.24 17.136 39.258 17.28 ;
    END
  END o[386]
  PIN o[387]
    DIRECTION OUTPUT ;
    USE SIGNAL ;
    PORT
      LAYER M5 ;
        RECT  39.312 17.088 39.336 17.28 ;
    END
  END o[387]
  PIN o[388]
    DIRECTION OUTPUT ;
    USE SIGNAL ;
    PORT
      LAYER M3 ;
        RECT  39.42 17.136 39.438 17.28 ;
    END
  END o[388]
  PIN o[389]
    DIRECTION OUTPUT ;
    USE SIGNAL ;
    PORT
      LAYER M5 ;
        RECT  39.504 17.088 39.528 17.28 ;
    END
  END o[389]
  PIN o[38]
    DIRECTION OUTPUT ;
    USE SIGNAL ;
    PORT
      LAYER M3 ;
        RECT  5.832 17.136 5.85 17.28 ;
    END
  END o[38]
  PIN o[390]
    DIRECTION OUTPUT ;
    USE SIGNAL ;
    PORT
      LAYER M3 ;
        RECT  39.6 17.136 39.618 17.28 ;
    END
  END o[390]
  PIN o[391]
    DIRECTION OUTPUT ;
    USE SIGNAL ;
    PORT
      LAYER M5 ;
        RECT  39.696 17.088 39.72 17.28 ;
    END
  END o[391]
  PIN o[392]
    DIRECTION OUTPUT ;
    USE SIGNAL ;
    PORT
      LAYER M3 ;
        RECT  39.78 17.136 39.798 17.28 ;
    END
  END o[392]
  PIN o[393]
    DIRECTION OUTPUT ;
    USE SIGNAL ;
    PORT
      LAYER M5 ;
        RECT  39.888 17.088 39.912 17.28 ;
    END
  END o[393]
  PIN o[394]
    DIRECTION OUTPUT ;
    USE SIGNAL ;
    PORT
      LAYER M3 ;
        RECT  39.996 17.136 40.014 17.28 ;
    END
  END o[394]
  PIN o[395]
    DIRECTION OUTPUT ;
    USE SIGNAL ;
    PORT
      LAYER M5 ;
        RECT  40.08 17.088 40.104 17.28 ;
    END
  END o[395]
  PIN o[396]
    DIRECTION OUTPUT ;
    USE SIGNAL ;
    PORT
      LAYER M3 ;
        RECT  40.176 17.136 40.194 17.28 ;
    END
  END o[396]
  PIN o[397]
    DIRECTION OUTPUT ;
    USE SIGNAL ;
    PORT
      LAYER M5 ;
        RECT  40.272 17.088 40.296 17.28 ;
    END
  END o[397]
  PIN o[398]
    DIRECTION OUTPUT ;
    USE SIGNAL ;
    PORT
      LAYER M3 ;
        RECT  40.356 17.136 40.374 17.28 ;
    END
  END o[398]
  PIN o[399]
    DIRECTION OUTPUT ;
    USE SIGNAL ;
    PORT
      LAYER M5 ;
        RECT  40.464 17.088 40.488 17.28 ;
    END
  END o[399]
  PIN o[39]
    DIRECTION OUTPUT ;
    USE SIGNAL ;
    PORT
      LAYER M5 ;
        RECT  5.952 17.088 5.976 17.28 ;
    END
  END o[39]
  PIN o[3]
    DIRECTION OUTPUT ;
    USE SIGNAL ;
    PORT
      LAYER M5 ;
        RECT  2.496 17.088 2.52 17.28 ;
    END
  END o[3]
  PIN o[400]
    DIRECTION OUTPUT ;
    USE SIGNAL ;
    PORT
      LAYER M3 ;
        RECT  40.572 17.136 40.59 17.28 ;
    END
  END o[400]
  PIN o[401]
    DIRECTION OUTPUT ;
    USE SIGNAL ;
    PORT
      LAYER M5 ;
        RECT  40.656 17.088 40.68 17.28 ;
    END
  END o[401]
  PIN o[402]
    DIRECTION OUTPUT ;
    USE SIGNAL ;
    PORT
      LAYER M3 ;
        RECT  40.752 17.136 40.77 17.28 ;
    END
  END o[402]
  PIN o[403]
    DIRECTION OUTPUT ;
    USE SIGNAL ;
    PORT
      LAYER M5 ;
        RECT  40.848 17.088 40.872 17.28 ;
    END
  END o[403]
  PIN o[404]
    DIRECTION OUTPUT ;
    USE SIGNAL ;
    PORT
      LAYER M3 ;
        RECT  40.932 17.136 40.95 17.28 ;
    END
  END o[404]
  PIN o[405]
    DIRECTION OUTPUT ;
    USE SIGNAL ;
    PORT
      LAYER M5 ;
        RECT  41.04 17.088 41.064 17.28 ;
    END
  END o[405]
  PIN o[406]
    DIRECTION OUTPUT ;
    USE SIGNAL ;
    PORT
      LAYER M3 ;
        RECT  41.148 17.136 41.166 17.28 ;
    END
  END o[406]
  PIN o[407]
    DIRECTION OUTPUT ;
    USE SIGNAL ;
    PORT
      LAYER M5 ;
        RECT  41.232 17.088 41.256 17.28 ;
    END
  END o[407]
  PIN o[408]
    DIRECTION OUTPUT ;
    USE SIGNAL ;
    PORT
      LAYER M3 ;
        RECT  41.328 17.136 41.346 17.28 ;
    END
  END o[408]
  PIN o[409]
    DIRECTION OUTPUT ;
    USE SIGNAL ;
    PORT
      LAYER M5 ;
        RECT  41.424 17.088 41.448 17.28 ;
    END
  END o[409]
  PIN o[40]
    DIRECTION OUTPUT ;
    USE SIGNAL ;
    PORT
      LAYER M3 ;
        RECT  6.048 17.136 6.066 17.28 ;
    END
  END o[40]
  PIN o[410]
    DIRECTION OUTPUT ;
    USE SIGNAL ;
    PORT
      LAYER M3 ;
        RECT  41.508 17.136 41.526 17.28 ;
    END
  END o[410]
  PIN o[411]
    DIRECTION OUTPUT ;
    USE SIGNAL ;
    PORT
      LAYER M5 ;
        RECT  41.616 17.088 41.64 17.28 ;
    END
  END o[411]
  PIN o[412]
    DIRECTION OUTPUT ;
    USE SIGNAL ;
    PORT
      LAYER M3 ;
        RECT  41.724 17.136 41.742 17.28 ;
    END
  END o[412]
  PIN o[413]
    DIRECTION OUTPUT ;
    USE SIGNAL ;
    PORT
      LAYER M5 ;
        RECT  41.808 17.088 41.832 17.28 ;
    END
  END o[413]
  PIN o[414]
    DIRECTION OUTPUT ;
    USE SIGNAL ;
    PORT
      LAYER M3 ;
        RECT  41.904 17.136 41.922 17.28 ;
    END
  END o[414]
  PIN o[415]
    DIRECTION OUTPUT ;
    USE SIGNAL ;
    PORT
      LAYER M5 ;
        RECT  42 17.088 42.024 17.28 ;
    END
  END o[415]
  PIN o[416]
    DIRECTION OUTPUT ;
    USE SIGNAL ;
    PORT
      LAYER M3 ;
        RECT  42.084 17.136 42.102 17.28 ;
    END
  END o[416]
  PIN o[417]
    DIRECTION OUTPUT ;
    USE SIGNAL ;
    PORT
      LAYER M5 ;
        RECT  42.192 17.088 42.216 17.28 ;
    END
  END o[417]
  PIN o[418]
    DIRECTION OUTPUT ;
    USE SIGNAL ;
    PORT
      LAYER M3 ;
        RECT  42.3 17.136 42.318 17.28 ;
    END
  END o[418]
  PIN o[419]
    DIRECTION OUTPUT ;
    USE SIGNAL ;
    PORT
      LAYER M5 ;
        RECT  42.384 17.088 42.408 17.28 ;
    END
  END o[419]
  PIN o[41]
    DIRECTION OUTPUT ;
    USE SIGNAL ;
    PORT
      LAYER M5 ;
        RECT  6.144 17.088 6.168 17.28 ;
    END
  END o[41]
  PIN o[420]
    DIRECTION OUTPUT ;
    USE SIGNAL ;
    PORT
      LAYER M3 ;
        RECT  42.48 17.136 42.498 17.28 ;
    END
  END o[420]
  PIN o[421]
    DIRECTION OUTPUT ;
    USE SIGNAL ;
    PORT
      LAYER M5 ;
        RECT  42.576 17.088 42.6 17.28 ;
    END
  END o[421]
  PIN o[422]
    DIRECTION OUTPUT ;
    USE SIGNAL ;
    PORT
      LAYER M3 ;
        RECT  42.66 17.136 42.678 17.28 ;
    END
  END o[422]
  PIN o[423]
    DIRECTION OUTPUT ;
    USE SIGNAL ;
    PORT
      LAYER M5 ;
        RECT  42.768 17.088 42.792 17.28 ;
    END
  END o[423]
  PIN o[424]
    DIRECTION OUTPUT ;
    USE SIGNAL ;
    PORT
      LAYER M3 ;
        RECT  42.876 17.136 42.894 17.28 ;
    END
  END o[424]
  PIN o[425]
    DIRECTION OUTPUT ;
    USE SIGNAL ;
    PORT
      LAYER M5 ;
        RECT  42.96 17.088 42.984 17.28 ;
    END
  END o[425]
  PIN o[426]
    DIRECTION OUTPUT ;
    USE SIGNAL ;
    PORT
      LAYER M3 ;
        RECT  43.056 17.136 43.074 17.28 ;
    END
  END o[426]
  PIN o[427]
    DIRECTION OUTPUT ;
    USE SIGNAL ;
    PORT
      LAYER M5 ;
        RECT  43.152 17.088 43.176 17.28 ;
    END
  END o[427]
  PIN o[428]
    DIRECTION OUTPUT ;
    USE SIGNAL ;
    PORT
      LAYER M3 ;
        RECT  43.236 17.136 43.254 17.28 ;
    END
  END o[428]
  PIN o[429]
    DIRECTION OUTPUT ;
    USE SIGNAL ;
    PORT
      LAYER M5 ;
        RECT  43.344 17.088 43.368 17.28 ;
    END
  END o[429]
  PIN o[42]
    DIRECTION OUTPUT ;
    USE SIGNAL ;
    PORT
      LAYER M3 ;
        RECT  6.228 17.136 6.246 17.28 ;
    END
  END o[42]
  PIN o[430]
    DIRECTION OUTPUT ;
    USE SIGNAL ;
    PORT
      LAYER M3 ;
        RECT  43.452 17.136 43.47 17.28 ;
    END
  END o[430]
  PIN o[431]
    DIRECTION OUTPUT ;
    USE SIGNAL ;
    PORT
      LAYER M5 ;
        RECT  43.536 17.088 43.56 17.28 ;
    END
  END o[431]
  PIN o[432]
    DIRECTION OUTPUT ;
    USE SIGNAL ;
    PORT
      LAYER M3 ;
        RECT  43.632 17.136 43.65 17.28 ;
    END
  END o[432]
  PIN o[433]
    DIRECTION OUTPUT ;
    USE SIGNAL ;
    PORT
      LAYER M5 ;
        RECT  43.728 17.088 43.752 17.28 ;
    END
  END o[433]
  PIN o[434]
    DIRECTION OUTPUT ;
    USE SIGNAL ;
    PORT
      LAYER M3 ;
        RECT  43.812 17.136 43.83 17.28 ;
    END
  END o[434]
  PIN o[435]
    DIRECTION OUTPUT ;
    USE SIGNAL ;
    PORT
      LAYER M5 ;
        RECT  43.92 17.088 43.944 17.28 ;
    END
  END o[435]
  PIN o[436]
    DIRECTION OUTPUT ;
    USE SIGNAL ;
    PORT
      LAYER M3 ;
        RECT  44.028 17.136 44.046 17.28 ;
    END
  END o[436]
  PIN o[437]
    DIRECTION OUTPUT ;
    USE SIGNAL ;
    PORT
      LAYER M5 ;
        RECT  44.112 17.088 44.136 17.28 ;
    END
  END o[437]
  PIN o[438]
    DIRECTION OUTPUT ;
    USE SIGNAL ;
    PORT
      LAYER M3 ;
        RECT  44.208 17.136 44.226 17.28 ;
    END
  END o[438]
  PIN o[439]
    DIRECTION OUTPUT ;
    USE SIGNAL ;
    PORT
      LAYER M5 ;
        RECT  44.304 17.088 44.328 17.28 ;
    END
  END o[439]
  PIN o[43]
    DIRECTION OUTPUT ;
    USE SIGNAL ;
    PORT
      LAYER M5 ;
        RECT  6.336 17.088 6.36 17.28 ;
    END
  END o[43]
  PIN o[440]
    DIRECTION OUTPUT ;
    USE SIGNAL ;
    PORT
      LAYER M3 ;
        RECT  44.388 17.136 44.406 17.28 ;
    END
  END o[440]
  PIN o[441]
    DIRECTION OUTPUT ;
    USE SIGNAL ;
    PORT
      LAYER M5 ;
        RECT  44.496 17.088 44.52 17.28 ;
    END
  END o[441]
  PIN o[442]
    DIRECTION OUTPUT ;
    USE SIGNAL ;
    PORT
      LAYER M3 ;
        RECT  44.604 17.136 44.622 17.28 ;
    END
  END o[442]
  PIN o[443]
    DIRECTION OUTPUT ;
    USE SIGNAL ;
    PORT
      LAYER M5 ;
        RECT  44.688 17.088 44.712 17.28 ;
    END
  END o[443]
  PIN o[444]
    DIRECTION OUTPUT ;
    USE SIGNAL ;
    PORT
      LAYER M3 ;
        RECT  44.784 17.136 44.802 17.28 ;
    END
  END o[444]
  PIN o[445]
    DIRECTION OUTPUT ;
    USE SIGNAL ;
    PORT
      LAYER M5 ;
        RECT  44.88 17.088 44.904 17.28 ;
    END
  END o[445]
  PIN o[446]
    DIRECTION OUTPUT ;
    USE SIGNAL ;
    PORT
      LAYER M3 ;
        RECT  44.964 17.136 44.982 17.28 ;
    END
  END o[446]
  PIN o[447]
    DIRECTION OUTPUT ;
    USE SIGNAL ;
    PORT
      LAYER M5 ;
        RECT  45.072 17.088 45.096 17.28 ;
    END
  END o[447]
  PIN o[448]
    DIRECTION OUTPUT ;
    USE SIGNAL ;
    PORT
      LAYER M3 ;
        RECT  45.18 17.136 45.198 17.28 ;
    END
  END o[448]
  PIN o[449]
    DIRECTION OUTPUT ;
    USE SIGNAL ;
    PORT
      LAYER M5 ;
        RECT  45.264 17.088 45.288 17.28 ;
    END
  END o[449]
  PIN o[44]
    DIRECTION OUTPUT ;
    USE SIGNAL ;
    PORT
      LAYER M3 ;
        RECT  6.408 17.136 6.426 17.28 ;
    END
  END o[44]
  PIN o[450]
    DIRECTION OUTPUT ;
    USE SIGNAL ;
    PORT
      LAYER M3 ;
        RECT  45.36 17.136 45.378 17.28 ;
    END
  END o[450]
  PIN o[451]
    DIRECTION OUTPUT ;
    USE SIGNAL ;
    PORT
      LAYER M5 ;
        RECT  45.456 17.088 45.48 17.28 ;
    END
  END o[451]
  PIN o[452]
    DIRECTION OUTPUT ;
    USE SIGNAL ;
    PORT
      LAYER M3 ;
        RECT  45.54 17.136 45.558 17.28 ;
    END
  END o[452]
  PIN o[453]
    DIRECTION OUTPUT ;
    USE SIGNAL ;
    PORT
      LAYER M5 ;
        RECT  45.648 17.088 45.672 17.28 ;
    END
  END o[453]
  PIN o[454]
    DIRECTION OUTPUT ;
    USE SIGNAL ;
    PORT
      LAYER M3 ;
        RECT  45.756 17.136 45.774 17.28 ;
    END
  END o[454]
  PIN o[455]
    DIRECTION OUTPUT ;
    USE SIGNAL ;
    PORT
      LAYER M5 ;
        RECT  45.84 17.088 45.864 17.28 ;
    END
  END o[455]
  PIN o[456]
    DIRECTION OUTPUT ;
    USE SIGNAL ;
    PORT
      LAYER M3 ;
        RECT  45.936 17.136 45.954 17.28 ;
    END
  END o[456]
  PIN o[457]
    DIRECTION OUTPUT ;
    USE SIGNAL ;
    PORT
      LAYER M5 ;
        RECT  46.032 17.088 46.056 17.28 ;
    END
  END o[457]
  PIN o[458]
    DIRECTION OUTPUT ;
    USE SIGNAL ;
    PORT
      LAYER M3 ;
        RECT  46.116 17.136 46.134 17.28 ;
    END
  END o[458]
  PIN o[459]
    DIRECTION OUTPUT ;
    USE SIGNAL ;
    PORT
      LAYER M5 ;
        RECT  46.224 17.088 46.248 17.28 ;
    END
  END o[459]
  PIN o[45]
    DIRECTION OUTPUT ;
    USE SIGNAL ;
    PORT
      LAYER M5 ;
        RECT  6.528 17.088 6.552 17.28 ;
    END
  END o[45]
  PIN o[460]
    DIRECTION OUTPUT ;
    USE SIGNAL ;
    PORT
      LAYER M3 ;
        RECT  46.332 17.136 46.35 17.28 ;
    END
  END o[460]
  PIN o[461]
    DIRECTION OUTPUT ;
    USE SIGNAL ;
    PORT
      LAYER M5 ;
        RECT  46.416 17.088 46.44 17.28 ;
    END
  END o[461]
  PIN o[462]
    DIRECTION OUTPUT ;
    USE SIGNAL ;
    PORT
      LAYER M3 ;
        RECT  46.512 17.136 46.53 17.28 ;
    END
  END o[462]
  PIN o[463]
    DIRECTION OUTPUT ;
    USE SIGNAL ;
    PORT
      LAYER M5 ;
        RECT  46.608 17.088 46.632 17.28 ;
    END
  END o[463]
  PIN o[464]
    DIRECTION OUTPUT ;
    USE SIGNAL ;
    PORT
      LAYER M3 ;
        RECT  46.692 17.136 46.71 17.28 ;
    END
  END o[464]
  PIN o[465]
    DIRECTION OUTPUT ;
    USE SIGNAL ;
    PORT
      LAYER M5 ;
        RECT  46.8 17.088 46.824 17.28 ;
    END
  END o[465]
  PIN o[466]
    DIRECTION OUTPUT ;
    USE SIGNAL ;
    PORT
      LAYER M3 ;
        RECT  46.908 17.136 46.926 17.28 ;
    END
  END o[466]
  PIN o[467]
    DIRECTION OUTPUT ;
    USE SIGNAL ;
    PORT
      LAYER M5 ;
        RECT  46.992 17.088 47.016 17.28 ;
    END
  END o[467]
  PIN o[468]
    DIRECTION OUTPUT ;
    USE SIGNAL ;
    PORT
      LAYER M3 ;
        RECT  47.088 17.136 47.106 17.28 ;
    END
  END o[468]
  PIN o[469]
    DIRECTION OUTPUT ;
    USE SIGNAL ;
    PORT
      LAYER M5 ;
        RECT  47.184 17.088 47.208 17.28 ;
    END
  END o[469]
  PIN o[46]
    DIRECTION OUTPUT ;
    USE SIGNAL ;
    PORT
      LAYER M3 ;
        RECT  6.624 17.136 6.642 17.28 ;
    END
  END o[46]
  PIN o[470]
    DIRECTION OUTPUT ;
    USE SIGNAL ;
    PORT
      LAYER M3 ;
        RECT  47.268 17.136 47.286 17.28 ;
    END
  END o[470]
  PIN o[471]
    DIRECTION OUTPUT ;
    USE SIGNAL ;
    PORT
      LAYER M5 ;
        RECT  47.376 17.088 47.4 17.28 ;
    END
  END o[471]
  PIN o[472]
    DIRECTION OUTPUT ;
    USE SIGNAL ;
    PORT
      LAYER M3 ;
        RECT  47.484 17.136 47.502 17.28 ;
    END
  END o[472]
  PIN o[473]
    DIRECTION OUTPUT ;
    USE SIGNAL ;
    PORT
      LAYER M5 ;
        RECT  47.568 17.088 47.592 17.28 ;
    END
  END o[473]
  PIN o[474]
    DIRECTION OUTPUT ;
    USE SIGNAL ;
    PORT
      LAYER M3 ;
        RECT  47.664 17.136 47.682 17.28 ;
    END
  END o[474]
  PIN o[475]
    DIRECTION OUTPUT ;
    USE SIGNAL ;
    PORT
      LAYER M5 ;
        RECT  47.76 17.088 47.784 17.28 ;
    END
  END o[475]
  PIN o[476]
    DIRECTION OUTPUT ;
    USE SIGNAL ;
    PORT
      LAYER M3 ;
        RECT  47.844 17.136 47.862 17.28 ;
    END
  END o[476]
  PIN o[477]
    DIRECTION OUTPUT ;
    USE SIGNAL ;
    PORT
      LAYER M5 ;
        RECT  47.952 17.088 47.976 17.28 ;
    END
  END o[477]
  PIN o[478]
    DIRECTION OUTPUT ;
    USE SIGNAL ;
    PORT
      LAYER M3 ;
        RECT  48.06 17.136 48.078 17.28 ;
    END
  END o[478]
  PIN o[479]
    DIRECTION OUTPUT ;
    USE SIGNAL ;
    PORT
      LAYER M5 ;
        RECT  48.144 17.088 48.168 17.28 ;
    END
  END o[479]
  PIN o[47]
    DIRECTION OUTPUT ;
    USE SIGNAL ;
    PORT
      LAYER M5 ;
        RECT  6.72 17.088 6.744 17.28 ;
    END
  END o[47]
  PIN o[480]
    DIRECTION OUTPUT ;
    USE SIGNAL ;
    PORT
      LAYER M3 ;
        RECT  48.24 17.136 48.258 17.28 ;
    END
  END o[480]
  PIN o[481]
    DIRECTION OUTPUT ;
    USE SIGNAL ;
    PORT
      LAYER M5 ;
        RECT  48.336 17.088 48.36 17.28 ;
    END
  END o[481]
  PIN o[482]
    DIRECTION OUTPUT ;
    USE SIGNAL ;
    PORT
      LAYER M3 ;
        RECT  48.42 17.136 48.438 17.28 ;
    END
  END o[482]
  PIN o[483]
    DIRECTION OUTPUT ;
    USE SIGNAL ;
    PORT
      LAYER M5 ;
        RECT  48.528 17.088 48.552 17.28 ;
    END
  END o[483]
  PIN o[484]
    DIRECTION OUTPUT ;
    USE SIGNAL ;
    PORT
      LAYER M3 ;
        RECT  48.636 17.136 48.654 17.28 ;
    END
  END o[484]
  PIN o[485]
    DIRECTION OUTPUT ;
    USE SIGNAL ;
    PORT
      LAYER M5 ;
        RECT  48.72 17.088 48.744 17.28 ;
    END
  END o[485]
  PIN o[486]
    DIRECTION OUTPUT ;
    USE SIGNAL ;
    PORT
      LAYER M3 ;
        RECT  48.816 17.136 48.834 17.28 ;
    END
  END o[486]
  PIN o[487]
    DIRECTION OUTPUT ;
    USE SIGNAL ;
    PORT
      LAYER M5 ;
        RECT  48.912 17.088 48.936 17.28 ;
    END
  END o[487]
  PIN o[488]
    DIRECTION OUTPUT ;
    USE SIGNAL ;
    PORT
      LAYER M3 ;
        RECT  48.996 17.136 49.014 17.28 ;
    END
  END o[488]
  PIN o[489]
    DIRECTION OUTPUT ;
    USE SIGNAL ;
    PORT
      LAYER M5 ;
        RECT  49.104 17.088 49.128 17.28 ;
    END
  END o[489]
  PIN o[48]
    DIRECTION OUTPUT ;
    USE SIGNAL ;
    PORT
      LAYER M3 ;
        RECT  6.804 17.136 6.822 17.28 ;
    END
  END o[48]
  PIN o[490]
    DIRECTION OUTPUT ;
    USE SIGNAL ;
    PORT
      LAYER M3 ;
        RECT  49.212 17.136 49.23 17.28 ;
    END
  END o[490]
  PIN o[491]
    DIRECTION OUTPUT ;
    USE SIGNAL ;
    PORT
      LAYER M5 ;
        RECT  49.296 17.088 49.32 17.28 ;
    END
  END o[491]
  PIN o[492]
    DIRECTION OUTPUT ;
    USE SIGNAL ;
    PORT
      LAYER M3 ;
        RECT  49.392 17.136 49.41 17.28 ;
    END
  END o[492]
  PIN o[493]
    DIRECTION OUTPUT ;
    USE SIGNAL ;
    PORT
      LAYER M5 ;
        RECT  49.488 17.088 49.512 17.28 ;
    END
  END o[493]
  PIN o[494]
    DIRECTION OUTPUT ;
    USE SIGNAL ;
    PORT
      LAYER M3 ;
        RECT  49.572 17.136 49.59 17.28 ;
    END
  END o[494]
  PIN o[495]
    DIRECTION OUTPUT ;
    USE SIGNAL ;
    PORT
      LAYER M5 ;
        RECT  49.68 17.088 49.704 17.28 ;
    END
  END o[495]
  PIN o[496]
    DIRECTION OUTPUT ;
    USE SIGNAL ;
    PORT
      LAYER M3 ;
        RECT  49.788 17.136 49.806 17.28 ;
    END
  END o[496]
  PIN o[497]
    DIRECTION OUTPUT ;
    USE SIGNAL ;
    PORT
      LAYER M5 ;
        RECT  49.872 17.088 49.896 17.28 ;
    END
  END o[497]
  PIN o[498]
    DIRECTION OUTPUT ;
    USE SIGNAL ;
    PORT
      LAYER M3 ;
        RECT  49.968 17.136 49.986 17.28 ;
    END
  END o[498]
  PIN o[499]
    DIRECTION OUTPUT ;
    USE SIGNAL ;
    PORT
      LAYER M5 ;
        RECT  50.064 17.088 50.088 17.28 ;
    END
  END o[499]
  PIN o[49]
    DIRECTION OUTPUT ;
    USE SIGNAL ;
    PORT
      LAYER M5 ;
        RECT  6.912 17.088 6.936 17.28 ;
    END
  END o[49]
  PIN o[4]
    DIRECTION OUTPUT ;
    USE SIGNAL ;
    PORT
      LAYER M3 ;
        RECT  2.592 17.136 2.61 17.28 ;
    END
  END o[4]
  PIN o[500]
    DIRECTION OUTPUT ;
    USE SIGNAL ;
    PORT
      LAYER M3 ;
        RECT  50.148 17.136 50.166 17.28 ;
    END
  END o[500]
  PIN o[501]
    DIRECTION OUTPUT ;
    USE SIGNAL ;
    PORT
      LAYER M5 ;
        RECT  50.256 17.088 50.28 17.28 ;
    END
  END o[501]
  PIN o[502]
    DIRECTION OUTPUT ;
    USE SIGNAL ;
    PORT
      LAYER M3 ;
        RECT  50.364 17.136 50.382 17.28 ;
    END
  END o[502]
  PIN o[503]
    DIRECTION OUTPUT ;
    USE SIGNAL ;
    PORT
      LAYER M5 ;
        RECT  50.448 17.088 50.472 17.28 ;
    END
  END o[503]
  PIN o[504]
    DIRECTION OUTPUT ;
    USE SIGNAL ;
    PORT
      LAYER M3 ;
        RECT  50.544 17.136 50.562 17.28 ;
    END
  END o[504]
  PIN o[505]
    DIRECTION OUTPUT ;
    USE SIGNAL ;
    PORT
      LAYER M5 ;
        RECT  50.64 17.088 50.664 17.28 ;
    END
  END o[505]
  PIN o[506]
    DIRECTION OUTPUT ;
    USE SIGNAL ;
    PORT
      LAYER M3 ;
        RECT  50.724 17.136 50.742 17.28 ;
    END
  END o[506]
  PIN o[507]
    DIRECTION OUTPUT ;
    USE SIGNAL ;
    PORT
      LAYER M5 ;
        RECT  50.832 17.088 50.856 17.28 ;
    END
  END o[507]
  PIN o[508]
    DIRECTION OUTPUT ;
    USE SIGNAL ;
    PORT
      LAYER M3 ;
        RECT  50.94 17.136 50.958 17.28 ;
    END
  END o[508]
  PIN o[509]
    DIRECTION OUTPUT ;
    USE SIGNAL ;
    PORT
      LAYER M5 ;
        RECT  51.024 17.088 51.048 17.28 ;
    END
  END o[509]
  PIN o[50]
    DIRECTION OUTPUT ;
    USE SIGNAL ;
    PORT
      LAYER M3 ;
        RECT  6.984 17.136 7.002 17.28 ;
    END
  END o[50]
  PIN o[510]
    DIRECTION OUTPUT ;
    USE SIGNAL ;
    PORT
      LAYER M3 ;
        RECT  51.12 17.136 51.138 17.28 ;
    END
  END o[510]
  PIN o[511]
    DIRECTION OUTPUT ;
    USE SIGNAL ;
    PORT
      LAYER M5 ;
        RECT  51.216 17.088 51.24 17.28 ;
    END
  END o[511]
  PIN o[512]
    DIRECTION OUTPUT ;
    USE SIGNAL ;
    PORT
      LAYER M3 ;
        RECT  51.3 17.136 51.318 17.28 ;
    END
  END o[512]
  PIN o[513]
    DIRECTION OUTPUT ;
    USE SIGNAL ;
    PORT
      LAYER M5 ;
        RECT  51.408 17.088 51.432 17.28 ;
    END
  END o[513]
  PIN o[514]
    DIRECTION OUTPUT ;
    USE SIGNAL ;
    PORT
      LAYER M3 ;
        RECT  51.516 17.136 51.534 17.28 ;
    END
  END o[514]
  PIN o[515]
    DIRECTION OUTPUT ;
    USE SIGNAL ;
    PORT
      LAYER M5 ;
        RECT  51.6 17.088 51.624 17.28 ;
    END
  END o[515]
  PIN o[516]
    DIRECTION OUTPUT ;
    USE SIGNAL ;
    PORT
      LAYER M3 ;
        RECT  51.696 17.136 51.714 17.28 ;
    END
  END o[516]
  PIN o[517]
    DIRECTION OUTPUT ;
    USE SIGNAL ;
    PORT
      LAYER M5 ;
        RECT  51.792 17.088 51.816 17.28 ;
    END
  END o[517]
  PIN o[518]
    DIRECTION OUTPUT ;
    USE SIGNAL ;
    PORT
      LAYER M3 ;
        RECT  51.876 17.136 51.894 17.28 ;
    END
  END o[518]
  PIN o[519]
    DIRECTION OUTPUT ;
    USE SIGNAL ;
    PORT
      LAYER M5 ;
        RECT  51.984 17.088 52.008 17.28 ;
    END
  END o[519]
  PIN o[51]
    DIRECTION OUTPUT ;
    USE SIGNAL ;
    PORT
      LAYER M5 ;
        RECT  7.104 17.088 7.128 17.28 ;
    END
  END o[51]
  PIN o[520]
    DIRECTION OUTPUT ;
    USE SIGNAL ;
    PORT
      LAYER M3 ;
        RECT  52.092 17.136 52.11 17.28 ;
    END
  END o[520]
  PIN o[521]
    DIRECTION OUTPUT ;
    USE SIGNAL ;
    PORT
      LAYER M5 ;
        RECT  52.176 17.088 52.2 17.28 ;
    END
  END o[521]
  PIN o[522]
    DIRECTION OUTPUT ;
    USE SIGNAL ;
    PORT
      LAYER M3 ;
        RECT  52.272 17.136 52.29 17.28 ;
    END
  END o[522]
  PIN o[523]
    DIRECTION OUTPUT ;
    USE SIGNAL ;
    PORT
      LAYER M5 ;
        RECT  52.368 17.088 52.392 17.28 ;
    END
  END o[523]
  PIN o[524]
    DIRECTION OUTPUT ;
    USE SIGNAL ;
    PORT
      LAYER M3 ;
        RECT  52.452 17.136 52.47 17.28 ;
    END
  END o[524]
  PIN o[525]
    DIRECTION OUTPUT ;
    USE SIGNAL ;
    PORT
      LAYER M5 ;
        RECT  52.56 17.088 52.584 17.28 ;
    END
  END o[525]
  PIN o[526]
    DIRECTION OUTPUT ;
    USE SIGNAL ;
    PORT
      LAYER M3 ;
        RECT  52.668 17.136 52.686 17.28 ;
    END
  END o[526]
  PIN o[527]
    DIRECTION OUTPUT ;
    USE SIGNAL ;
    PORT
      LAYER M5 ;
        RECT  52.752 17.088 52.776 17.28 ;
    END
  END o[527]
  PIN o[528]
    DIRECTION OUTPUT ;
    USE SIGNAL ;
    PORT
      LAYER M3 ;
        RECT  52.848 17.136 52.866 17.28 ;
    END
  END o[528]
  PIN o[529]
    DIRECTION OUTPUT ;
    USE SIGNAL ;
    PORT
      LAYER M5 ;
        RECT  52.944 17.088 52.968 17.28 ;
    END
  END o[529]
  PIN o[52]
    DIRECTION OUTPUT ;
    USE SIGNAL ;
    PORT
      LAYER M3 ;
        RECT  7.2 17.136 7.218 17.28 ;
    END
  END o[52]
  PIN o[530]
    DIRECTION OUTPUT ;
    USE SIGNAL ;
    PORT
      LAYER M3 ;
        RECT  53.028 17.136 53.046 17.28 ;
    END
  END o[530]
  PIN o[531]
    DIRECTION OUTPUT ;
    USE SIGNAL ;
    PORT
      LAYER M5 ;
        RECT  53.136 17.088 53.16 17.28 ;
    END
  END o[531]
  PIN o[532]
    DIRECTION OUTPUT ;
    USE SIGNAL ;
    PORT
      LAYER M3 ;
        RECT  53.208 17.136 53.226 17.28 ;
    END
  END o[532]
  PIN o[533]
    DIRECTION OUTPUT ;
    USE SIGNAL ;
    PORT
      LAYER M5 ;
        RECT  53.328 17.088 53.352 17.28 ;
    END
  END o[533]
  PIN o[534]
    DIRECTION OUTPUT ;
    USE SIGNAL ;
    PORT
      LAYER M3 ;
        RECT  53.424 17.136 53.442 17.28 ;
    END
  END o[534]
  PIN o[535]
    DIRECTION OUTPUT ;
    USE SIGNAL ;
    PORT
      LAYER M5 ;
        RECT  53.52 17.088 53.544 17.28 ;
    END
  END o[535]
  PIN o[536]
    DIRECTION OUTPUT ;
    USE SIGNAL ;
    PORT
      LAYER M3 ;
        RECT  53.604 17.136 53.622 17.28 ;
    END
  END o[536]
  PIN o[537]
    DIRECTION OUTPUT ;
    USE SIGNAL ;
    PORT
      LAYER M5 ;
        RECT  53.712 17.088 53.736 17.28 ;
    END
  END o[537]
  PIN o[538]
    DIRECTION OUTPUT ;
    USE SIGNAL ;
    PORT
      LAYER M3 ;
        RECT  53.784 17.136 53.802 17.28 ;
    END
  END o[538]
  PIN o[539]
    DIRECTION OUTPUT ;
    USE SIGNAL ;
    PORT
      LAYER M5 ;
        RECT  53.904 17.088 53.928 17.28 ;
    END
  END o[539]
  PIN o[53]
    DIRECTION OUTPUT ;
    USE SIGNAL ;
    PORT
      LAYER M5 ;
        RECT  7.296 17.088 7.32 17.28 ;
    END
  END o[53]
  PIN o[540]
    DIRECTION OUTPUT ;
    USE SIGNAL ;
    PORT
      LAYER M3 ;
        RECT  54 17.136 54.018 17.28 ;
    END
  END o[540]
  PIN o[541]
    DIRECTION OUTPUT ;
    USE SIGNAL ;
    PORT
      LAYER M5 ;
        RECT  54.096 17.088 54.12 17.28 ;
    END
  END o[541]
  PIN o[542]
    DIRECTION OUTPUT ;
    USE SIGNAL ;
    PORT
      LAYER M3 ;
        RECT  54.18 17.136 54.198 17.28 ;
    END
  END o[542]
  PIN o[543]
    DIRECTION OUTPUT ;
    USE SIGNAL ;
    PORT
      LAYER M5 ;
        RECT  54.288 17.088 54.312 17.28 ;
    END
  END o[543]
  PIN o[544]
    DIRECTION OUTPUT ;
    USE SIGNAL ;
    PORT
      LAYER M3 ;
        RECT  54.36 17.136 54.378 17.28 ;
    END
  END o[544]
  PIN o[545]
    DIRECTION OUTPUT ;
    USE SIGNAL ;
    PORT
      LAYER M5 ;
        RECT  54.48 17.088 54.504 17.28 ;
    END
  END o[545]
  PIN o[546]
    DIRECTION OUTPUT ;
    USE SIGNAL ;
    PORT
      LAYER M3 ;
        RECT  54.576 17.136 54.594 17.28 ;
    END
  END o[546]
  PIN o[547]
    DIRECTION OUTPUT ;
    USE SIGNAL ;
    PORT
      LAYER M5 ;
        RECT  54.672 17.088 54.696 17.28 ;
    END
  END o[547]
  PIN o[548]
    DIRECTION OUTPUT ;
    USE SIGNAL ;
    PORT
      LAYER M3 ;
        RECT  54.756 17.136 54.774 17.28 ;
    END
  END o[548]
  PIN o[549]
    DIRECTION OUTPUT ;
    USE SIGNAL ;
    PORT
      LAYER M5 ;
        RECT  54.864 17.088 54.888 17.28 ;
    END
  END o[549]
  PIN o[54]
    DIRECTION OUTPUT ;
    USE SIGNAL ;
    PORT
      LAYER M3 ;
        RECT  7.38 17.136 7.398 17.28 ;
    END
  END o[54]
  PIN o[550]
    DIRECTION OUTPUT ;
    USE SIGNAL ;
    PORT
      LAYER M3 ;
        RECT  54.936 17.136 54.954 17.28 ;
    END
  END o[550]
  PIN o[551]
    DIRECTION OUTPUT ;
    USE SIGNAL ;
    PORT
      LAYER M5 ;
        RECT  55.056 17.088 55.08 17.28 ;
    END
  END o[551]
  PIN o[552]
    DIRECTION OUTPUT ;
    USE SIGNAL ;
    PORT
      LAYER M3 ;
        RECT  55.152 17.136 55.17 17.28 ;
    END
  END o[552]
  PIN o[553]
    DIRECTION OUTPUT ;
    USE SIGNAL ;
    PORT
      LAYER M5 ;
        RECT  55.248 17.088 55.272 17.28 ;
    END
  END o[553]
  PIN o[554]
    DIRECTION OUTPUT ;
    USE SIGNAL ;
    PORT
      LAYER M3 ;
        RECT  55.332 17.136 55.35 17.28 ;
    END
  END o[554]
  PIN o[555]
    DIRECTION OUTPUT ;
    USE SIGNAL ;
    PORT
      LAYER M5 ;
        RECT  55.44 17.088 55.464 17.28 ;
    END
  END o[555]
  PIN o[556]
    DIRECTION OUTPUT ;
    USE SIGNAL ;
    PORT
      LAYER M3 ;
        RECT  55.512 17.136 55.53 17.28 ;
    END
  END o[556]
  PIN o[557]
    DIRECTION OUTPUT ;
    USE SIGNAL ;
    PORT
      LAYER M5 ;
        RECT  55.632 17.088 55.656 17.28 ;
    END
  END o[557]
  PIN o[558]
    DIRECTION OUTPUT ;
    USE SIGNAL ;
    PORT
      LAYER M3 ;
        RECT  55.728 17.136 55.746 17.28 ;
    END
  END o[558]
  PIN o[559]
    DIRECTION OUTPUT ;
    USE SIGNAL ;
    PORT
      LAYER M5 ;
        RECT  55.824 17.088 55.848 17.28 ;
    END
  END o[559]
  PIN o[55]
    DIRECTION OUTPUT ;
    USE SIGNAL ;
    PORT
      LAYER M5 ;
        RECT  7.488 17.088 7.512 17.28 ;
    END
  END o[55]
  PIN o[560]
    DIRECTION OUTPUT ;
    USE SIGNAL ;
    PORT
      LAYER M3 ;
        RECT  55.908 17.136 55.926 17.28 ;
    END
  END o[560]
  PIN o[561]
    DIRECTION OUTPUT ;
    USE SIGNAL ;
    PORT
      LAYER M5 ;
        RECT  56.016 17.088 56.04 17.28 ;
    END
  END o[561]
  PIN o[56]
    DIRECTION OUTPUT ;
    USE SIGNAL ;
    PORT
      LAYER M3 ;
        RECT  7.56 17.136 7.578 17.28 ;
    END
  END o[56]
  PIN o[57]
    DIRECTION OUTPUT ;
    USE SIGNAL ;
    PORT
      LAYER M5 ;
        RECT  7.68 17.088 7.704 17.28 ;
    END
  END o[57]
  PIN o[58]
    DIRECTION OUTPUT ;
    USE SIGNAL ;
    PORT
      LAYER M3 ;
        RECT  7.776 17.136 7.794 17.28 ;
    END
  END o[58]
  PIN o[59]
    DIRECTION OUTPUT ;
    USE SIGNAL ;
    PORT
      LAYER M5 ;
        RECT  7.872 17.088 7.896 17.28 ;
    END
  END o[59]
  PIN o[5]
    DIRECTION OUTPUT ;
    USE SIGNAL ;
    PORT
      LAYER M5 ;
        RECT  2.688 17.088 2.712 17.28 ;
    END
  END o[5]
  PIN o[60]
    DIRECTION OUTPUT ;
    USE SIGNAL ;
    PORT
      LAYER M3 ;
        RECT  7.956 17.136 7.974 17.28 ;
    END
  END o[60]
  PIN o[61]
    DIRECTION OUTPUT ;
    USE SIGNAL ;
    PORT
      LAYER M5 ;
        RECT  8.064 17.088 8.088 17.28 ;
    END
  END o[61]
  PIN o[62]
    DIRECTION OUTPUT ;
    USE SIGNAL ;
    PORT
      LAYER M3 ;
        RECT  8.136 17.136 8.154 17.28 ;
    END
  END o[62]
  PIN o[63]
    DIRECTION OUTPUT ;
    USE SIGNAL ;
    PORT
      LAYER M5 ;
        RECT  8.256 17.088 8.28 17.28 ;
    END
  END o[63]
  PIN o[64]
    DIRECTION OUTPUT ;
    USE SIGNAL ;
    PORT
      LAYER M3 ;
        RECT  8.352 17.136 8.37 17.28 ;
    END
  END o[64]
  PIN o[65]
    DIRECTION OUTPUT ;
    USE SIGNAL ;
    PORT
      LAYER M5 ;
        RECT  8.448 17.088 8.472 17.28 ;
    END
  END o[65]
  PIN o[66]
    DIRECTION OUTPUT ;
    USE SIGNAL ;
    PORT
      LAYER M3 ;
        RECT  8.532 17.136 8.55 17.28 ;
    END
  END o[66]
  PIN o[67]
    DIRECTION OUTPUT ;
    USE SIGNAL ;
    PORT
      LAYER M5 ;
        RECT  8.64 17.088 8.664 17.28 ;
    END
  END o[67]
  PIN o[68]
    DIRECTION OUTPUT ;
    USE SIGNAL ;
    PORT
      LAYER M3 ;
        RECT  8.712 17.136 8.73 17.28 ;
    END
  END o[68]
  PIN o[69]
    DIRECTION OUTPUT ;
    USE SIGNAL ;
    PORT
      LAYER M5 ;
        RECT  8.832 17.088 8.856 17.28 ;
    END
  END o[69]
  PIN o[6]
    DIRECTION OUTPUT ;
    USE SIGNAL ;
    PORT
      LAYER M3 ;
        RECT  2.772 17.136 2.79 17.28 ;
    END
  END o[6]
  PIN o[70]
    DIRECTION OUTPUT ;
    USE SIGNAL ;
    PORT
      LAYER M3 ;
        RECT  8.928 17.136 8.946 17.28 ;
    END
  END o[70]
  PIN o[71]
    DIRECTION OUTPUT ;
    USE SIGNAL ;
    PORT
      LAYER M5 ;
        RECT  9.024 17.088 9.048 17.28 ;
    END
  END o[71]
  PIN o[72]
    DIRECTION OUTPUT ;
    USE SIGNAL ;
    PORT
      LAYER M3 ;
        RECT  9.108 17.136 9.126 17.28 ;
    END
  END o[72]
  PIN o[73]
    DIRECTION OUTPUT ;
    USE SIGNAL ;
    PORT
      LAYER M5 ;
        RECT  9.216 17.088 9.24 17.28 ;
    END
  END o[73]
  PIN o[74]
    DIRECTION OUTPUT ;
    USE SIGNAL ;
    PORT
      LAYER M3 ;
        RECT  9.288 17.136 9.306 17.28 ;
    END
  END o[74]
  PIN o[75]
    DIRECTION OUTPUT ;
    USE SIGNAL ;
    PORT
      LAYER M5 ;
        RECT  9.408 17.088 9.432 17.28 ;
    END
  END o[75]
  PIN o[76]
    DIRECTION OUTPUT ;
    USE SIGNAL ;
    PORT
      LAYER M3 ;
        RECT  9.504 17.136 9.522 17.28 ;
    END
  END o[76]
  PIN o[77]
    DIRECTION OUTPUT ;
    USE SIGNAL ;
    PORT
      LAYER M5 ;
        RECT  9.6 17.088 9.624 17.28 ;
    END
  END o[77]
  PIN o[78]
    DIRECTION OUTPUT ;
    USE SIGNAL ;
    PORT
      LAYER M3 ;
        RECT  9.684 17.136 9.702 17.28 ;
    END
  END o[78]
  PIN o[79]
    DIRECTION OUTPUT ;
    USE SIGNAL ;
    PORT
      LAYER M5 ;
        RECT  9.792 17.088 9.816 17.28 ;
    END
  END o[79]
  PIN o[7]
    DIRECTION OUTPUT ;
    USE SIGNAL ;
    PORT
      LAYER M5 ;
        RECT  2.88 17.088 2.904 17.28 ;
    END
  END o[7]
  PIN o[80]
    DIRECTION OUTPUT ;
    USE SIGNAL ;
    PORT
      LAYER M3 ;
        RECT  9.864 17.136 9.882 17.28 ;
    END
  END o[80]
  PIN o[81]
    DIRECTION OUTPUT ;
    USE SIGNAL ;
    PORT
      LAYER M5 ;
        RECT  9.984 17.088 10.008 17.28 ;
    END
  END o[81]
  PIN o[82]
    DIRECTION OUTPUT ;
    USE SIGNAL ;
    PORT
      LAYER M3 ;
        RECT  10.08 17.136 10.098 17.28 ;
    END
  END o[82]
  PIN o[83]
    DIRECTION OUTPUT ;
    USE SIGNAL ;
    PORT
      LAYER M5 ;
        RECT  10.176 17.088 10.2 17.28 ;
    END
  END o[83]
  PIN o[84]
    DIRECTION OUTPUT ;
    USE SIGNAL ;
    PORT
      LAYER M3 ;
        RECT  10.26 17.136 10.278 17.28 ;
    END
  END o[84]
  PIN o[85]
    DIRECTION OUTPUT ;
    USE SIGNAL ;
    PORT
      LAYER M5 ;
        RECT  10.368 17.088 10.392 17.28 ;
    END
  END o[85]
  PIN o[86]
    DIRECTION OUTPUT ;
    USE SIGNAL ;
    PORT
      LAYER M3 ;
        RECT  10.44 17.136 10.458 17.28 ;
    END
  END o[86]
  PIN o[87]
    DIRECTION OUTPUT ;
    USE SIGNAL ;
    PORT
      LAYER M5 ;
        RECT  10.56 17.088 10.584 17.28 ;
    END
  END o[87]
  PIN o[88]
    DIRECTION OUTPUT ;
    USE SIGNAL ;
    PORT
      LAYER M3 ;
        RECT  10.656 17.136 10.674 17.28 ;
    END
  END o[88]
  PIN o[89]
    DIRECTION OUTPUT ;
    USE SIGNAL ;
    PORT
      LAYER M5 ;
        RECT  10.752 17.088 10.776 17.28 ;
    END
  END o[89]
  PIN o[8]
    DIRECTION OUTPUT ;
    USE SIGNAL ;
    PORT
      LAYER M3 ;
        RECT  2.952 17.136 2.97 17.28 ;
    END
  END o[8]
  PIN o[90]
    DIRECTION OUTPUT ;
    USE SIGNAL ;
    PORT
      LAYER M3 ;
        RECT  10.836 17.136 10.854 17.28 ;
    END
  END o[90]
  PIN o[91]
    DIRECTION OUTPUT ;
    USE SIGNAL ;
    PORT
      LAYER M5 ;
        RECT  10.944 17.088 10.968 17.28 ;
    END
  END o[91]
  PIN o[92]
    DIRECTION OUTPUT ;
    USE SIGNAL ;
    PORT
      LAYER M3 ;
        RECT  11.016 17.136 11.034 17.28 ;
    END
  END o[92]
  PIN o[93]
    DIRECTION OUTPUT ;
    USE SIGNAL ;
    PORT
      LAYER M5 ;
        RECT  11.136 17.088 11.16 17.28 ;
    END
  END o[93]
  PIN o[94]
    DIRECTION OUTPUT ;
    USE SIGNAL ;
    PORT
      LAYER M3 ;
        RECT  11.232 17.136 11.25 17.28 ;
    END
  END o[94]
  PIN o[95]
    DIRECTION OUTPUT ;
    USE SIGNAL ;
    PORT
      LAYER M5 ;
        RECT  11.328 17.088 11.352 17.28 ;
    END
  END o[95]
  PIN o[96]
    DIRECTION OUTPUT ;
    USE SIGNAL ;
    PORT
      LAYER M3 ;
        RECT  11.412 17.136 11.43 17.28 ;
    END
  END o[96]
  PIN o[97]
    DIRECTION OUTPUT ;
    USE SIGNAL ;
    PORT
      LAYER M5 ;
        RECT  11.52 17.088 11.544 17.28 ;
    END
  END o[97]
  PIN o[98]
    DIRECTION OUTPUT ;
    USE SIGNAL ;
    PORT
      LAYER M3 ;
        RECT  11.592 17.136 11.61 17.28 ;
    END
  END o[98]
  PIN o[99]
    DIRECTION OUTPUT ;
    USE SIGNAL ;
    PORT
      LAYER M5 ;
        RECT  11.712 17.088 11.736 17.28 ;
    END
  END o[99]
  PIN o[9]
    DIRECTION OUTPUT ;
    USE SIGNAL ;
    PORT
      LAYER M5 ;
        RECT  3.072 17.088 3.096 17.28 ;
    END
  END o[9]
  PIN rs
    DIRECTION INPUT ;
    USE SIGNAL ;
    PORT
      LAYER M4 ;
        RECT  58.128 11.904 58.32 11.928 ;
    END
  END rs
  PIN VDD
    DIRECTION INOUT ;
    USE POWER ;
    PORT
      LAYER M5 ;
        RECT  53.892 2.151 54.012 15.129 ;
        RECT  51.192 2.151 51.312 15.129 ;
        RECT  48.492 2.151 48.612 15.129 ;
        RECT  45.792 2.151 45.912 15.129 ;
        RECT  43.092 2.151 43.212 15.129 ;
        RECT  40.392 2.151 40.512 15.129 ;
        RECT  37.692 2.151 37.812 15.129 ;
        RECT  34.992 2.151 35.112 15.129 ;
        RECT  32.292 2.151 32.412 15.129 ;
        RECT  29.592 2.151 29.712 15.129 ;
        RECT  26.892 2.151 27.012 15.129 ;
        RECT  24.192 2.151 24.312 15.129 ;
        RECT  21.492 2.151 21.612 15.129 ;
        RECT  18.792 2.151 18.912 15.129 ;
        RECT  16.092 2.151 16.212 15.129 ;
        RECT  13.392 2.151 13.512 15.129 ;
        RECT  10.692 2.151 10.812 15.129 ;
        RECT  7.992 2.151 8.112 15.129 ;
        RECT  5.292 2.151 5.412 15.129 ;
        RECT  2.592 2.151 2.712 15.129 ;
    END
  END VDD
  PIN VSS
    DIRECTION INOUT ;
    USE GROUND ;
    PORT
      LAYER M5 ;
        RECT  53.7 2.137 53.82 15.143 ;
        RECT  51 2.137 51.12 15.143 ;
        RECT  48.3 2.137 48.42 15.143 ;
        RECT  45.6 2.137 45.72 15.143 ;
        RECT  42.9 2.137 43.02 15.143 ;
        RECT  40.2 2.137 40.32 15.143 ;
        RECT  37.5 2.137 37.62 15.143 ;
        RECT  34.8 2.137 34.92 15.143 ;
        RECT  32.1 2.137 32.22 15.143 ;
        RECT  29.4 2.137 29.52 15.143 ;
        RECT  26.7 2.137 26.82 15.143 ;
        RECT  24 2.137 24.12 15.143 ;
        RECT  21.3 2.137 21.42 15.143 ;
        RECT  18.6 2.137 18.72 15.143 ;
        RECT  15.9 2.137 16.02 15.143 ;
        RECT  13.2 2.137 13.32 15.143 ;
        RECT  10.5 2.137 10.62 15.143 ;
        RECT  7.8 2.137 7.92 15.143 ;
        RECT  5.1 2.137 5.22 15.143 ;
        RECT  2.4 2.137 2.52 15.143 ;
    END
  END VSS
  OBS
    LAYER RVTN ;
     RECT  2.16 2.16 56.16 2.295 ;
     RECT  2.16 2.565 56.16 2.835 ;
     RECT  2.16 3.105 56.16 3.375 ;
     RECT  2.16 3.645 56.16 3.915 ;
     RECT  2.16 4.185 56.16 4.455 ;
     RECT  2.16 4.725 56.16 4.995 ;
     RECT  2.16 5.265 56.16 5.535 ;
     RECT  2.16 5.805 56.16 6.075 ;
     RECT  2.16 6.345 56.16 6.615 ;
     RECT  2.16 6.885 56.16 7.155 ;
     RECT  2.16 7.425 56.16 7.695 ;
     RECT  2.16 7.965 56.16 8.235 ;
     RECT  2.16 8.505 56.16 8.775 ;
     RECT  2.16 9.045 56.16 9.315 ;
     RECT  2.16 9.585 56.16 9.855 ;
     RECT  2.16 10.125 56.16 10.395 ;
     RECT  2.16 10.665 56.16 10.935 ;
     RECT  2.16 11.205 56.16 11.475 ;
     RECT  2.16 11.745 56.16 12.015 ;
     RECT  2.16 12.285 56.16 12.555 ;
     RECT  2.16 12.825 56.16 13.095 ;
     RECT  2.16 13.365 56.16 13.635 ;
     RECT  2.16 13.905 56.16 14.175 ;
     RECT  2.16 14.445 56.16 14.715 ;
     RECT  2.16 14.985 56.16 15.12 ;
    LAYER RVTP ;
     RECT  2.16 2.295 56.16 2.565 ;
     RECT  2.16 2.835 56.16 3.105 ;
     RECT  2.16 3.375 56.16 3.645 ;
     RECT  2.16 3.915 56.16 4.185 ;
     RECT  2.16 4.455 56.16 4.725 ;
     RECT  2.16 4.995 56.16 5.265 ;
     RECT  2.16 5.535 56.16 5.805 ;
     RECT  2.16 6.075 56.16 6.345 ;
     RECT  2.16 6.615 56.16 6.885 ;
     RECT  2.16 7.155 56.16 7.425 ;
     RECT  2.16 7.695 56.16 7.965 ;
     RECT  2.16 8.235 56.16 8.505 ;
     RECT  2.16 8.775 56.16 9.045 ;
     RECT  2.16 9.315 56.16 9.585 ;
     RECT  2.16 9.855 56.16 10.125 ;
     RECT  2.16 10.395 56.16 10.665 ;
     RECT  2.16 10.935 56.16 11.205 ;
     RECT  2.16 11.475 56.16 11.745 ;
     RECT  2.16 12.015 56.16 12.285 ;
     RECT  2.16 12.555 56.16 12.825 ;
     RECT  2.16 13.095 56.16 13.365 ;
     RECT  2.16 13.635 56.16 13.905 ;
     RECT  2.16 14.175 56.16 14.445 ;
     RECT  2.16 14.715 56.16 14.985 ;
    LAYER M1 ;
     RECT  2.16 2.151 56.16 15.129 ;
    LAYER M2 ;
     RECT  2.335 0.216 2.371 0.234 ;
     RECT  2.371 0.144 2.615 0.234 ;
     RECT  2.16 2.151 2.767 15.129 ;
     RECT  2.767 1.998 2.867 15.129 ;
     RECT  2.371 16.542 2.947 16.56 ;
     RECT  2.947 16.542 3.227 16.668 ;
     RECT  3.163 1.152 3.271 1.17 ;
     RECT  3.271 1.152 3.371 1.242 ;
     RECT  3.227 16.542 3.839 16.56 ;
     RECT  2.615 0.144 3.883 0.162 ;
     RECT  3.883 0.144 3.947 0.198 ;
     RECT  3.947 0.144 3.983 0.162 ;
     RECT  3.371 1.152 3.983 1.17 ;
     RECT  2.867 2.151 4.387 15.129 ;
     RECT  4.891 1.152 5.251 1.17 ;
     RECT  4.387 2.106 5.459 15.129 ;
     RECT  5.071 16.542 5.467 16.56 ;
     RECT  5.251 1.152 5.495 1.242 ;
     RECT  5.495 1.152 5.567 1.17 ;
     RECT  5.459 2.151 5.683 15.129 ;
     RECT  5.467 16.542 5.711 16.632 ;
     RECT  5.711 16.614 6.035 16.632 ;
     RECT  5.683 2.151 6.323 15.399 ;
     RECT  6.187 0.144 6.403 0.162 ;
     RECT  6.331 1.152 6.403 1.17 ;
     RECT  6.403 0.144 6.439 0.234 ;
     RECT  6.403 1.152 6.503 1.206 ;
     RECT  6.439 0.144 7.223 0.324 ;
     RECT  7.195 17.118 7.231 17.136 ;
     RECT  6.503 1.152 7.259 1.17 ;
     RECT  6.323 2.151 7.267 15.129 ;
     RECT  7.231 17.118 7.331 17.208 ;
     RECT  7.223 0.306 7.403 0.324 ;
     RECT  7.267 2.151 7.403 15.444 ;
     RECT  8.347 1.152 8.447 1.17 ;
     RECT  7.403 2.151 8.707 15.129 ;
     RECT  8.707 2.151 8.743 15.174 ;
     RECT  8.743 1.728 8.843 15.174 ;
     RECT  8.843 2.151 9.103 15.174 ;
     RECT  9.499 16.11 9.599 16.128 ;
     RECT  9.103 2.151 10.255 15.246 ;
     RECT  8.491 0.144 10.679 0.162 ;
     RECT  10.255 2.106 10.823 15.318 ;
     RECT  10.823 2.106 11.291 15.246 ;
     RECT  11.291 2.106 11.363 15.174 ;
     RECT  11.227 1.152 11.407 1.17 ;
     RECT  11.363 2.106 11.407 15.129 ;
     RECT  11.407 1.152 11.939 15.129 ;
     RECT  11.515 0.144 12.271 0.162 ;
     RECT  11.939 1.152 12.271 1.359 ;
     RECT  12.271 0.144 12.299 1.359 ;
     RECT  12.299 0.144 12.407 1.278 ;
     RECT  12.407 0.576 12.551 1.278 ;
     RECT  12.551 0.576 12.587 0.594 ;
     RECT  11.939 2.151 13.063 15.129 ;
     RECT  13.063 2.151 13.603 15.246 ;
     RECT  13.711 1.152 13.883 1.17 ;
     RECT  13.603 2.106 13.883 15.246 ;
     RECT  13.883 2.106 14.027 15.174 ;
     RECT  14.071 17.118 14.107 17.136 ;
     RECT  14.027 2.106 14.395 15.129 ;
     RECT  13.927 0.144 14.459 0.162 ;
     RECT  14.395 2.07 14.719 15.129 ;
     RECT  14.107 17.118 14.783 17.208 ;
     RECT  14.863 1.152 15.179 1.17 ;
     RECT  14.719 1.998 15.223 15.129 ;
     RECT  15.223 1.998 15.575 15.246 ;
     RECT  15.575 2.151 15.619 15.246 ;
     RECT  15.619 2.151 16.223 15.282 ;
     RECT  16.195 17.118 16.231 17.136 ;
     RECT  16.231 17.118 16.331 17.208 ;
     RECT  16.411 1.152 16.511 1.17 ;
     RECT  16.223 2.151 17.095 15.246 ;
     RECT  17.095 2.151 17.195 15.354 ;
     RECT  18.895 17.118 18.931 17.136 ;
     RECT  18.931 17.118 19.031 17.208 ;
     RECT  17.195 2.151 19.139 15.318 ;
     RECT  16.015 0.144 19.607 0.162 ;
     RECT  19.147 1.152 19.679 1.17 ;
     RECT  19.139 2.151 20.191 15.174 ;
     RECT  20.227 17.118 20.263 17.136 ;
     RECT  20.191 2.151 20.435 15.246 ;
     RECT  20.263 17.118 20.903 17.208 ;
     RECT  20.435 2.151 21.163 15.129 ;
     RECT  21.163 2.151 21.407 15.246 ;
     RECT  21.127 0.216 21.415 0.234 ;
     RECT  21.415 0.144 21.623 0.234 ;
     RECT  21.407 2.151 21.659 15.174 ;
     RECT  21.623 0.144 22.631 0.162 ;
     RECT  22.351 16.074 22.775 16.092 ;
     RECT  21.659 2.151 22.927 15.129 ;
     RECT  23.215 16.65 23.315 16.668 ;
     RECT  22.927 2.151 23.351 15.399 ;
     RECT  23.351 2.151 24.079 15.129 ;
     RECT  24.079 2.151 24.439 15.21 ;
     RECT  23.935 0.144 24.511 0.162 ;
     RECT  24.511 0.144 24.899 0.234 ;
     RECT  24.439 2.106 25.115 15.282 ;
     RECT  25.115 2.151 25.483 15.282 ;
     RECT  24.899 0.144 25.871 0.162 ;
     RECT  25.483 2.151 26.059 15.354 ;
     RECT  26.059 2.151 26.195 15.516 ;
     RECT  25.771 1.152 26.627 1.17 ;
     RECT  26.195 2.151 27.319 15.21 ;
     RECT  27.319 2.151 27.571 15.399 ;
     RECT  27.787 17.118 27.887 17.208 ;
     RECT  27.887 17.118 27.923 17.136 ;
     RECT  27.571 2.106 28.075 15.399 ;
     RECT  28.075 2.106 28.175 15.75 ;
     RECT  28.175 2.106 28.327 15.246 ;
     RECT  26.779 0.144 28.867 0.162 ;
     RECT  28.867 0.144 28.931 0.198 ;
     RECT  28.327 2.034 28.931 15.246 ;
     RECT  28.931 2.151 29.191 15.246 ;
     RECT  29.191 2.151 29.651 15.282 ;
     RECT  28.723 1.152 30.047 1.17 ;
     RECT  28.931 0.144 30.083 0.162 ;
     RECT  29.651 2.151 30.299 15.246 ;
     RECT  30.811 1.152 30.947 1.17 ;
     RECT  30.883 0.144 31.235 0.162 ;
     RECT  30.299 2.151 31.747 15.174 ;
     RECT  31.747 2.151 32.503 15.246 ;
     RECT  32.503 2.151 32.899 15.318 ;
     RECT  32.899 2.151 33.755 15.399 ;
     RECT  33.755 2.151 34.807 15.174 ;
     RECT  34.807 2.151 34.987 15.21 ;
     RECT  31.999 0.144 35.167 0.162 ;
     RECT  34.987 2.151 35.339 15.282 ;
     RECT  35.167 0.144 35.663 0.234 ;
     RECT  35.815 1.152 35.915 1.17 ;
     RECT  35.339 2.151 36.347 15.174 ;
     RECT  36.347 2.151 36.463 15.129 ;
     RECT  35.663 0.144 36.787 0.162 ;
     RECT  36.787 0.144 36.851 0.234 ;
     RECT  36.851 0.216 36.887 0.234 ;
     RECT  36.859 1.152 36.959 1.17 ;
     RECT  36.859 17.118 36.959 17.208 ;
     RECT  36.959 17.19 36.995 17.208 ;
     RECT  36.463 2.106 37.363 15.129 ;
     RECT  37.363 2.106 37.543 15.21 ;
     RECT  37.543 2.07 38.011 15.21 ;
     RECT  38.011 2.07 38.111 15.399 ;
     RECT  38.111 2.07 38.507 15.318 ;
     RECT  37.651 0.144 38.659 0.162 ;
     RECT  38.659 0.144 38.803 0.234 ;
     RECT  38.803 0.144 38.939 0.279 ;
     RECT  38.507 2.151 39.019 15.318 ;
     RECT  39.019 2.151 39.155 15.354 ;
     RECT  39.155 2.151 39.587 15.318 ;
     RECT  38.939 0.144 39.667 0.162 ;
     RECT  39.587 2.151 40.027 15.246 ;
     RECT  40.027 1.881 40.163 15.246 ;
     RECT  39.667 0.144 40.271 0.234 ;
     RECT  40.271 0.216 40.451 0.234 ;
     RECT  40.639 1.152 40.919 1.242 ;
     RECT  40.919 1.224 41.027 1.242 ;
     RECT  41.215 0.144 41.395 0.162 ;
     RECT  41.395 0.144 41.495 0.234 ;
     RECT  40.163 2.151 41.639 15.246 ;
     RECT  41.639 2.151 42.043 15.174 ;
     RECT  42.043 2.106 42.583 15.174 ;
     RECT  42.583 2.106 42.835 15.246 ;
     RECT  41.495 0.144 42.971 0.162 ;
     RECT  42.835 2.106 43.259 15.552 ;
     RECT  43.123 0.18 43.331 0.324 ;
     RECT  43.331 0.18 43.403 0.279 ;
     RECT  43.259 2.106 44.635 15.246 ;
     RECT  44.635 2.106 45.031 15.318 ;
     RECT  43.879 1.152 45.103 1.17 ;
     RECT  45.103 1.152 45.203 1.206 ;
     RECT  45.203 1.152 45.239 1.17 ;
     RECT  45.355 17.118 45.391 17.136 ;
     RECT  45.031 2.106 45.463 15.399 ;
     RECT  45.391 17.118 45.491 17.208 ;
     RECT  43.879 0.144 45.823 0.162 ;
     RECT  45.931 1.224 46.003 1.242 ;
     RECT  46.003 1.152 46.031 1.242 ;
     RECT  45.463 2.106 46.067 16.092 ;
     RECT  46.031 1.152 46.175 1.17 ;
     RECT  45.823 0.144 46.471 0.198 ;
     RECT  46.471 0.144 46.607 0.234 ;
     RECT  47.551 1.152 47.831 1.17 ;
     RECT  46.067 2.106 47.947 15.399 ;
     RECT  46.607 0.144 48.659 0.162 ;
     RECT  47.947 1.926 48.803 15.399 ;
     RECT  49.855 0.144 49.963 0.162 ;
     RECT  49.963 0.144 50.063 0.234 ;
     RECT  48.803 1.962 50.207 15.399 ;
     RECT  50.207 1.962 50.611 15.246 ;
     RECT  48.883 1.152 50.755 1.17 ;
     RECT  50.611 1.926 50.755 15.246 ;
     RECT  50.063 0.144 50.855 0.162 ;
     RECT  50.755 1.152 50.891 15.246 ;
     RECT  50.891 1.881 50.935 15.246 ;
     RECT  50.863 0.216 51.215 0.234 ;
     RECT  50.935 1.881 51.295 15.354 ;
     RECT  51.295 1.881 51.763 15.399 ;
     RECT  51.763 1.728 51.863 15.399 ;
     RECT  51.863 1.728 52.159 15.282 ;
     RECT  52.159 1.152 52.403 15.282 ;
     RECT  52.403 1.152 53.131 1.17 ;
     RECT  53.131 1.152 53.267 1.206 ;
     RECT  51.979 0.144 53.311 0.162 ;
     RECT  53.419 17.118 53.455 17.136 ;
     RECT  53.311 0.144 53.519 0.324 ;
     RECT  53.455 17.118 53.555 17.208 ;
     RECT  52.403 2.07 53.995 15.282 ;
     RECT  53.995 2.07 54.139 15.318 ;
     RECT  54.139 1.998 54.679 15.318 ;
     RECT  54.679 1.962 54.787 15.318 ;
     RECT  53.267 1.152 55.219 1.17 ;
     RECT  55.219 1.071 55.319 1.17 ;
     RECT  54.787 1.962 55.427 15.354 ;
     RECT  55.427 1.998 55.463 15.354 ;
     RECT  55.319 1.152 55.499 1.17 ;
     RECT  53.519 0.144 55.679 0.162 ;
     RECT  55.463 2.106 55.751 15.354 ;
     RECT  55.751 2.106 55.787 15.174 ;
     RECT  55.787 2.106 56.16 15.129 ;
     RECT  56.16 2.106 56.183 2.124 ;
     RECT  56.16 9.396 56.183 9.414 ;
     RECT  56.16 10.476 56.183 15.012 ;
     RECT  56.183 10.476 56.219 14.508 ;
     RECT  56.16 6.426 56.507 6.444 ;
     RECT  56.219 11.214 56.507 14.508 ;
     RECT  56.507 11.214 56.543 13.734 ;
     RECT  56.543 11.25 57.083 13.734 ;
     RECT  56.16 5.04 57.119 5.058 ;
     RECT  57.083 12.258 57.119 13.734 ;
     RECT  57.119 13.41 57.155 13.734 ;
     RECT  57.083 11.25 57.191 11.466 ;
     RECT  57.055 3.42 57.587 3.438 ;
     RECT  56.507 14.49 57.587 14.508 ;
     RECT  57.155 13.41 57.623 13.428 ;
     RECT  57.119 12.258 57.659 12.276 ;
    LAYER M3 ;
     RECT  2.196 0.108 56.034 0.187 ;
     RECT  2.196 0.187 56.142 0.557 ;
     RECT  2.196 0.557 53.514 1.723 ;
     RECT  2.196 1.723 53.586 1.771 ;
     RECT  54.468 0.557 56.142 1.771 ;
     RECT  2.196 1.771 56.142 2.101 ;
     RECT  57.06 2.587 57.078 3.067 ;
     RECT  57.024 3.067 57.078 3.415 ;
     RECT  57.024 3.415 57.582 3.595 ;
     RECT  2.196 2.101 56.178 3.691 ;
     RECT  57.024 3.595 57.618 3.691 ;
     RECT  2.196 3.691 57.618 5.765 ;
     RECT  2.34 5.765 57.618 5.947 ;
     RECT  2.34 5.947 57.654 8.509 ;
     RECT  2.196 8.509 57.654 12.281 ;
     RECT  2.196 12.281 57.618 13.433 ;
     RECT  2.196 13.433 57.582 13.739 ;
     RECT  2.196 13.739 56.502 14.279 ;
     RECT  57.564 13.739 57.582 14.513 ;
     RECT  2.196 14.279 56.178 15.017 ;
     RECT  2.196 15.017 56.034 15.053 ;
     RECT  2.196 15.053 55.926 16.555 ;
     RECT  2.196 16.555 56.106 17.148 ;
     RECT  7.236 17.148 7.326 17.213 ;
     RECT  14.112 17.148 14.778 17.213 ;
     RECT  16.236 17.148 16.326 17.213 ;
     RECT  18.936 17.148 19.026 17.213 ;
     RECT  20.268 17.148 20.898 17.213 ;
     RECT  27.792 17.148 27.882 17.213 ;
     RECT  36.864 17.148 36.99 17.213 ;
     RECT  45.396 17.148 45.486 17.213 ;
     RECT  53.46 17.148 53.55 17.213 ;
    LAYER M4 ;
     RECT  2.285 3.984 2.365 4.008 ;
     RECT  2.401 2.304 2.408 2.328 ;
     RECT  2.365 3.984 2.408 4.152 ;
     RECT  2.293 16.56 2.485 16.584 ;
     RECT  2.408 2.148 2.545 15.132 ;
     RECT  2.485 16.56 2.585 16.632 ;
     RECT  2.545 1.728 2.677 15.132 ;
     RECT  2.677 1.728 2.704 15.24 ;
     RECT  2.485 0.192 2.819 0.216 ;
     RECT  2.704 14.784 2.819 15.24 ;
     RECT  2.704 11.952 2.837 11.976 ;
     RECT  2.585 16.56 2.981 16.584 ;
     RECT  2.819 14.784 3.089 14.856 ;
     RECT  2.704 10.848 3.731 10.872 ;
     RECT  3.089 14.832 3.829 14.856 ;
     RECT  2.704 8.496 4.213 8.904 ;
     RECT  3.877 9.888 4.213 10.296 ;
     RECT  3.829 14.832 4.237 14.904 ;
     RECT  4.237 14.256 4.453 14.904 ;
     RECT  3.637 15.984 4.493 16.008 ;
     RECT  4.453 13.68 4.501 14.904 ;
     RECT  2.704 1.728 4.561 5.784 ;
     RECT  4.561 1.728 5.033 6.312 ;
     RECT  5.033 2.148 5.108 6.312 ;
     RECT  4.661 7.44 5.108 7.464 ;
     RECT  4.213 8.496 5.108 10.296 ;
     RECT  4.597 11.952 5.108 11.976 ;
     RECT  4.501 13.68 5.108 14.952 ;
     RECT  4.849 0.528 5.173 0.552 ;
     RECT  5.108 2.148 5.404 15.288 ;
     RECT  5.404 13.68 5.557 15.288 ;
     RECT  5.404 2.148 5.651 10.056 ;
     RECT  5.173 0.192 5.699 0.552 ;
     RECT  5.651 7.968 5.747 10.056 ;
     RECT  5.699 0.288 5.749 0.552 ;
     RECT  5.651 2.148 5.753 6.936 ;
     RECT  5.404 11.472 5.789 11.976 ;
     RECT  5.747 8.976 5.861 10.056 ;
     RECT  5.749 0.288 5.891 1.176 ;
     RECT  5.891 0.288 5.939 0.312 ;
     RECT  5.753 2.148 6.133 2.328 ;
     RECT  5.557 13.68 6.193 15.912 ;
     RECT  6.133 1.728 6.257 2.328 ;
     RECT  5.747 7.968 6.467 7.992 ;
     RECT  6.257 2.304 6.721 2.328 ;
     RECT  5.753 3.312 6.721 6.936 ;
     RECT  5.789 11.472 6.757 11.688 ;
     RECT  6.721 2.304 6.761 6.936 ;
     RECT  5.861 9.072 6.829 10.056 ;
     RECT  6.193 14.256 7.093 15.912 ;
     RECT  7.093 14.256 7.18 16.008 ;
     RECT  7.18 14.256 7.409 15.384 ;
     RECT  6.761 2.88 7.549 6.936 ;
     RECT  6.757 11.472 7.669 12.024 ;
     RECT  7.549 2.88 7.808 6.984 ;
     RECT  7.484 7.968 7.808 7.992 ;
     RECT  6.829 9.072 7.808 10.152 ;
     RECT  7.669 11.424 7.808 12.024 ;
     RECT  7.409 14.256 7.808 15.288 ;
     RECT  7.573 0.192 7.907 0.216 ;
     RECT  7.808 2.148 7.912 15.288 ;
     RECT  7.912 2.418 8.104 15.288 ;
     RECT  8.053 0.288 8.243 0.312 ;
     RECT  8.245 1.152 8.771 1.176 ;
     RECT  8.104 14.784 9.133 15.288 ;
     RECT  8.104 2.448 9.205 6.888 ;
     RECT  9.133 14.256 9.205 15.288 ;
     RECT  9.205 14.256 9.209 16.008 ;
     RECT  9.209 14.256 9.241 14.952 ;
     RECT  9.241 13.68 9.347 14.952 ;
     RECT  8.104 11.376 9.395 12.552 ;
     RECT  9.209 15.984 9.397 16.008 ;
     RECT  9.205 2.448 9.493 6.936 ;
     RECT  9.397 15.984 9.533 16.056 ;
     RECT  8.104 9.504 9.589 10.344 ;
     RECT  9.395 11.376 9.589 12.024 ;
     RECT  9.533 15.984 9.677 16.008 ;
     RECT  9.493 2.256 9.817 6.936 ;
     RECT  9.637 7.968 9.817 7.992 ;
     RECT  9.347 14.256 10.285 14.952 ;
     RECT  10.261 0.192 10.309 0.216 ;
     RECT  9.589 9.504 10.309 12.024 ;
     RECT  10.309 9.12 10.357 12.024 ;
     RECT  9.817 2.256 10.508 7.992 ;
     RECT  10.357 9.12 10.508 12.552 ;
     RECT  10.285 14.256 10.508 15.336 ;
     RECT  10.309 0.192 10.595 0.312 ;
     RECT  10.508 2.148 10.612 15.336 ;
     RECT  10.612 2.256 10.645 15.336 ;
     RECT  10.595 0.288 10.787 0.312 ;
     RECT  10.645 2.256 10.787 15.432 ;
     RECT  10.787 2.256 10.804 15.336 ;
     RECT  10.804 2.256 10.829 8.04 ;
     RECT  10.804 14.832 10.835 15.336 ;
     RECT  10.829 3.216 11.027 8.04 ;
     RECT  10.804 9.504 11.027 12.024 ;
     RECT  10.933 1.152 11.075 1.176 ;
     RECT  10.835 14.832 11.117 15.288 ;
     RECT  11.027 3.696 11.153 8.04 ;
     RECT  11.027 9.504 11.297 11.976 ;
     RECT  10.804 13.104 11.699 13.128 ;
     RECT  11.153 3.696 12.037 7.992 ;
     RECT  12.037 3.216 12.085 7.992 ;
     RECT  11.893 13.68 12.085 14.04 ;
     RECT  11.117 15.216 12.085 15.288 ;
     RECT  11.297 9.504 12.161 11.448 ;
     RECT  12.085 0.192 12.227 0.216 ;
     RECT  12.161 10.704 12.661 11.448 ;
     RECT  12.325 0.288 13.093 0.312 ;
     RECT  12.085 2.592 13.208 7.992 ;
     RECT  12.161 9.504 13.208 9.624 ;
     RECT  12.661 10.704 13.208 11.976 ;
     RECT  12.085 13.68 13.208 15.288 ;
     RECT  13.208 2.148 13.312 15.288 ;
     RECT  13.093 0.288 13.429 0.408 ;
     RECT  13.312 2.418 13.504 15.288 ;
     RECT  13.504 14.256 13.565 15.288 ;
     RECT  13.565 14.256 13.673 15.24 ;
     RECT  13.504 9.504 13.781 9.624 ;
     RECT  13.429 0.192 14.147 0.408 ;
     RECT  13.504 10.704 14.177 11.976 ;
     RECT  13.781 9.504 14.285 9.576 ;
     RECT  13.504 13.104 14.509 13.176 ;
     RECT  14.177 10.704 14.717 11.928 ;
     RECT  14.581 1.152 14.723 1.176 ;
     RECT  13.504 2.832 14.771 8.52 ;
     RECT  13.673 14.256 14.773 15 ;
     RECT  14.581 15.984 14.773 16.008 ;
     RECT  14.773 14.256 14.789 16.008 ;
     RECT  14.509 13.152 14.915 13.176 ;
     RECT  15.137 0.24 15.221 0.408 ;
     RECT  14.771 2.832 15.349 8.04 ;
     RECT  15.221 0.288 15.401 0.408 ;
     RECT  14.717 11.328 15.649 11.928 ;
     RECT  15.349 2.736 15.692 8.04 ;
     RECT  14.789 14.256 15.877 15.192 ;
     RECT  15.692 2.256 15.908 8.04 ;
     RECT  14.285 9.504 15.908 9.528 ;
     RECT  15.649 11.328 15.908 11.976 ;
     RECT  15.877 14.256 15.908 15.288 ;
     RECT  15.908 2.148 16.012 15.288 ;
     RECT  16.012 2.208 16.204 15.288 ;
     RECT  16.204 14.304 16.261 15.288 ;
     RECT  15.401 0.288 16.309 0.312 ;
     RECT  16.204 2.208 16.499 8.52 ;
     RECT  16.645 16.56 16.733 16.584 ;
     RECT  16.499 2.256 16.739 8.52 ;
     RECT  16.309 0.192 17.036 0.312 ;
     RECT  17.036 0.192 17.219 1.176 ;
     RECT  16.739 2.976 17.221 8.52 ;
     RECT  16.204 9.504 17.221 9.528 ;
     RECT  16.261 14.304 17.305 15.432 ;
     RECT  17.221 2.976 17.315 9.528 ;
     RECT  17.305 14.256 17.389 15.432 ;
     RECT  17.219 1.152 17.411 1.176 ;
     RECT  16.204 10.848 17.449 12.552 ;
     RECT  17.449 10.8 17.773 12.552 ;
     RECT  17.653 1.728 17.957 1.752 ;
     RECT  17.389 14.304 18.029 15.432 ;
     RECT  18.092 0.144 18.179 0.168 ;
     RECT  18.029 14.304 18.421 15.384 ;
     RECT  17.315 3.024 18.608 9.528 ;
     RECT  17.773 10.752 18.608 12.552 ;
     RECT  18.421 14.208 18.608 15.384 ;
     RECT  18.608 2.148 18.712 15.384 ;
     RECT  18.712 2.418 18.904 15.384 ;
     RECT  18.904 13.68 19.141 15.384 ;
     RECT  18.904 2.418 19.379 10.248 ;
     RECT  18.904 11.424 19.475 11.976 ;
     RECT  18.613 0.288 19.537 0.6 ;
     RECT  19.141 13.68 19.619 15.432 ;
     RECT  19.537 0.192 19.621 0.6 ;
     RECT  19.621 0.24 19.715 0.6 ;
     RECT  19.379 2.418 19.717 9.336 ;
     RECT  19.619 14.208 19.721 15.432 ;
     RECT  19.717 2.256 19.811 9.336 ;
     RECT  19.715 0.24 19.859 0.312 ;
     RECT  19.721 14.4 19.937 15.432 ;
     RECT  20.005 13.104 20.089 13.128 ;
     RECT  19.475 11.76 20.113 11.976 ;
     RECT  19.811 2.832 20.437 9.336 ;
     RECT  20.113 11.76 20.545 12.552 ;
     RECT  19.859 0.24 20.585 0.264 ;
     RECT  19.937 14.64 20.977 15.432 ;
     RECT  20.437 2.832 21.085 9.672 ;
     RECT  20.545 11.424 21.109 12.552 ;
     RECT  20.977 14.4 21.121 15.432 ;
     RECT  21.109 11.424 21.157 12.792 ;
     RECT  21.085 2.016 21.308 9.672 ;
     RECT  21.157 11.232 21.308 12.792 ;
     RECT  21.121 14.4 21.308 16.008 ;
     RECT  21.157 0.288 21.347 0.312 ;
     RECT  21.308 2.016 21.539 16.008 ;
     RECT  21.539 2.418 21.604 16.008 ;
     RECT  21.604 10.848 21.779 11.976 ;
     RECT  21.685 0.192 21.827 0.216 ;
     RECT  21.779 11.232 22.205 11.976 ;
     RECT  22.124 0.144 22.211 0.168 ;
     RECT  21.604 13.776 22.355 16.008 ;
     RECT  22.355 14.976 22.385 16.008 ;
     RECT  21.604 9.216 22.633 9.624 ;
     RECT  22.385 14.976 22.961 15.336 ;
     RECT  22.981 0.48 23.093 0.504 ;
     RECT  21.604 2.784 23.101 7.992 ;
     RECT  23.093 0.48 23.177 0.552 ;
     RECT  23.101 2.304 23.221 7.992 ;
     RECT  22.355 13.776 23.237 13.8 ;
     RECT  22.981 16.56 23.321 16.584 ;
     RECT  22.205 11.424 23.353 11.976 ;
     RECT  23.177 0.48 23.357 0.504 ;
     RECT  23.221 1.728 23.357 7.992 ;
     RECT  23.237 13.68 23.461 13.8 ;
     RECT  22.961 14.976 23.497 15.24 ;
     RECT  23.497 14.832 23.941 15.24 ;
     RECT  23.357 2.148 24.008 7.992 ;
     RECT  22.633 9.216 24.008 9.672 ;
     RECT  23.353 11.424 24.008 12.024 ;
     RECT  23.461 13.104 24.008 13.8 ;
     RECT  23.941 14.832 24.008 15.288 ;
     RECT  24.008 2.148 24.133 15.288 ;
     RECT  24.133 2.148 24.304 15.336 ;
     RECT  24.304 13.68 24.419 15.336 ;
     RECT  24.304 2.148 24.473 9.624 ;
     RECT  24.419 13.68 24.509 15.288 ;
     RECT  23.569 0.192 24.833 0.408 ;
     RECT  24.473 2.148 24.949 9.336 ;
     RECT  24.304 11.424 24.995 12.552 ;
     RECT  24.995 11.52 25.043 12.552 ;
     RECT  24.833 0.288 25.141 0.408 ;
     RECT  24.949 1.728 25.141 9.336 ;
     RECT  25.141 0.288 25.283 9.336 ;
     RECT  24.509 13.68 25.477 14.904 ;
     RECT  25.043 11.904 25.525 12.552 ;
     RECT  25.283 0.288 25.571 0.312 ;
     RECT  25.477 13.68 25.571 15 ;
     RECT  25.571 14.112 25.861 15 ;
     RECT  25.283 1.728 26.089 9.336 ;
     RECT  25.861 14.112 26.437 15.432 ;
     RECT  26.089 1.728 26.633 9.384 ;
     RECT  26.633 1.968 26.708 9.384 ;
     RECT  25.525 11.904 26.708 11.976 ;
     RECT  26.437 14.112 26.708 15.672 ;
     RECT  26.708 1.968 27.004 15.672 ;
     RECT  27.004 1.968 27.209 7.992 ;
     RECT  26.581 0.192 27.233 0.216 ;
     RECT  27.209 2.256 27.251 7.992 ;
     RECT  27.233 0.192 27.253 0.696 ;
     RECT  27.253 0.192 27.389 0.936 ;
     RECT  27.004 11.424 27.731 11.976 ;
     RECT  27.389 0.192 27.875 0.312 ;
     RECT  27.004 13.104 28.109 15.672 ;
     RECT  28.109 13.104 28.189 15.096 ;
     RECT  27.004 9.36 28.249 9.384 ;
     RECT  27.731 11.664 28.321 11.976 ;
     RECT  28.189 13.68 28.333 15.096 ;
     RECT  27.251 2.256 28.393 7.704 ;
     RECT  28.249 9.072 28.393 9.384 ;
     RECT  28.321 11.664 28.405 12.024 ;
     RECT  28.393 2.256 28.789 9.384 ;
     RECT  28.789 1.728 28.933 9.384 ;
     RECT  28.933 1.728 29.045 9.672 ;
     RECT  28.333 14.016 29.125 15.096 ;
     RECT  27.875 0.288 29.269 0.312 ;
     RECT  29.125 14.016 29.317 15.432 ;
     RECT  29.317 14.016 29.404 15.528 ;
     RECT  29.045 2.148 29.408 9.672 ;
     RECT  28.405 11.664 29.408 11.976 ;
     RECT  29.404 14.016 29.408 15.288 ;
     RECT  29.269 0.192 29.411 0.312 ;
     RECT  29.408 2.148 29.555 15.288 ;
     RECT  29.555 2.148 29.704 15.24 ;
     RECT  29.411 0.288 29.941 0.312 ;
     RECT  29.704 2.148 30.125 2.28 ;
     RECT  29.941 0.288 30.133 0.36 ;
     RECT  30.133 0.288 30.325 1.176 ;
     RECT  29.704 11.424 30.515 11.928 ;
     RECT  30.325 0.288 30.629 1.752 ;
     RECT  29.704 14.208 30.661 15.24 ;
     RECT  29.704 3.408 30.733 9.816 ;
     RECT  30.515 11.664 30.853 11.928 ;
     RECT  30.733 3.12 30.989 9.816 ;
     RECT  30.629 0.288 30.995 1.224 ;
     RECT  30.995 0.288 31.187 1.176 ;
     RECT  30.989 3.12 31.237 8.568 ;
     RECT  30.989 9.648 31.237 9.816 ;
     RECT  30.661 14.208 31.237 15.288 ;
     RECT  30.853 11.664 31.333 11.976 ;
     RECT  31.237 13.344 31.333 15.288 ;
     RECT  31.187 0.288 31.765 0.312 ;
     RECT  31.333 11.664 32.005 15.288 ;
     RECT  31.765 0.192 32.099 0.312 ;
     RECT  32.005 11.664 32.105 15.432 ;
     RECT  31.237 2.88 32.108 8.568 ;
     RECT  31.237 9.648 32.108 10.248 ;
     RECT  32.105 11.664 32.108 15.336 ;
     RECT  32.108 2.148 32.404 15.336 ;
     RECT  32.404 2.148 32.437 9.672 ;
     RECT  32.404 14.256 32.476 15.336 ;
     RECT  32.437 2.016 32.537 9.672 ;
     RECT  32.404 10.848 32.617 13.128 ;
     RECT  32.537 2.688 32.723 9.672 ;
     RECT  32.723 2.688 32.825 8.568 ;
     RECT  32.825 2.688 32.861 7.8 ;
     RECT  32.617 11.664 32.897 13.128 ;
     RECT  32.897 11.952 33.085 13.128 ;
     RECT  32.723 9.648 33.113 9.672 ;
     RECT  32.861 2.688 33.155 7.656 ;
     RECT  33.085 11.952 33.157 12.024 ;
     RECT  32.476 14.256 33.725 15.288 ;
     RECT  32.099 0.288 33.781 0.312 ;
     RECT  33.781 0.192 33.923 0.312 ;
     RECT  33.157 11.952 33.925 11.976 ;
     RECT  33.155 2.784 33.937 7.656 ;
     RECT  33.725 14.256 34.153 15.24 ;
     RECT  33.829 10.272 34.213 10.296 ;
     RECT  33.925 11.376 34.213 11.976 ;
     RECT  33.937 2.784 34.405 8.232 ;
     RECT  34.405 1.824 34.541 8.232 ;
     RECT  34.541 1.728 34.625 8.232 ;
     RECT  34.213 10.272 34.693 11.976 ;
     RECT  34.625 2.148 34.808 8.232 ;
     RECT  34.693 9.6 34.808 11.976 ;
     RECT  33.085 13.104 34.808 13.128 ;
     RECT  34.153 14.112 34.808 15.24 ;
     RECT  34.808 2.148 34.885 15.24 ;
     RECT  34.885 2.148 34.912 15.288 ;
     RECT  34.912 2.256 35.077 15.288 ;
     RECT  35.077 2.256 35.104 15.384 ;
     RECT  33.923 0.288 35.125 0.312 ;
     RECT  35.104 13.056 35.219 13.08 ;
     RECT  35.125 0.192 35.317 0.312 ;
     RECT  35.104 2.256 35.411 9.672 ;
     RECT  35.104 14.112 35.653 15.384 ;
     RECT  35.653 14.112 35.741 15.432 ;
     RECT  35.317 0.192 35.893 0.36 ;
     RECT  35.893 0.192 36.085 1.176 ;
     RECT  35.411 2.256 36.085 9.096 ;
     RECT  36.085 0.192 36.245 9.096 ;
     RECT  36.245 0.192 36.323 1.176 ;
     RECT  36.097 13.104 36.323 13.128 ;
     RECT  36.323 1.152 36.611 1.176 ;
     RECT  35.741 14.112 36.805 15.096 ;
     RECT  35.104 11.424 36.853 11.976 ;
     RECT  36.245 2.208 37.069 9.096 ;
     RECT  36.805 14.112 37.189 15.24 ;
     RECT  37.189 14.112 37.381 15.288 ;
     RECT  37.381 14.112 37.429 15.336 ;
     RECT  37.069 2.208 37.508 9.336 ;
     RECT  36.853 11.424 37.508 12.024 ;
     RECT  37.429 13.68 37.508 15.336 ;
     RECT  37.508 2.148 37.573 15.336 ;
     RECT  37.573 2.148 37.612 16.008 ;
     RECT  37.285 0.288 37.621 0.312 ;
     RECT  37.612 2.16 37.804 16.008 ;
     RECT  37.621 0.192 37.909 0.312 ;
     RECT  37.909 0.192 38.099 1.176 ;
     RECT  37.804 11.328 38.261 16.008 ;
     RECT  38.099 0.192 38.339 0.216 ;
     RECT  37.804 2.16 38.483 10.056 ;
     RECT  38.483 2.16 38.581 8.232 ;
     RECT  38.483 9.648 38.801 10.056 ;
     RECT  38.581 1.728 38.819 8.232 ;
     RECT  38.261 11.328 39.109 15.336 ;
     RECT  39.109 10.992 39.493 15.336 ;
     RECT  39.349 0.288 39.539 0.312 ;
     RECT  38.801 9.648 39.913 9.912 ;
     RECT  38.819 1.728 39.925 7.464 ;
     RECT  39.925 1.152 40.208 7.464 ;
     RECT  39.913 9.072 40.208 9.912 ;
     RECT  39.493 10.992 40.208 16.008 ;
     RECT  40.208 1.152 40.501 16.008 ;
     RECT  40.501 0.288 40.504 16.008 ;
     RECT  40.504 11.424 40.889 16.008 ;
     RECT  40.504 0.288 41.219 7.176 ;
     RECT  41.219 0.288 41.269 0.312 ;
     RECT  40.889 11.424 41.315 15.432 ;
     RECT  40.504 9.072 41.497 9.912 ;
     RECT  41.497 9.024 41.747 9.912 ;
     RECT  41.315 11.472 42.077 15.432 ;
     RECT  41.219 1.392 42.361 7.176 ;
     RECT  41.269 0.192 42.613 0.312 ;
     RECT  42.361 1.392 42.613 7.464 ;
     RECT  42.613 0.192 42.755 7.464 ;
     RECT  41.747 9.072 42.757 9.912 ;
     RECT  42.755 1.392 42.908 7.464 ;
     RECT  42.757 8.544 42.908 9.912 ;
     RECT  42.077 11.472 42.908 15.384 ;
     RECT  42.908 1.392 43.141 15.384 ;
     RECT  43.141 1.392 43.204 15.48 ;
     RECT  43.204 11.424 43.265 15.48 ;
     RECT  43.265 11.424 43.301 15.384 ;
     RECT  42.755 0.192 43.379 0.312 ;
     RECT  43.204 1.392 43.619 10.296 ;
     RECT  43.379 0.288 43.813 0.312 ;
     RECT  43.619 1.392 43.813 7.464 ;
     RECT  43.301 11.424 44.147 15.336 ;
     RECT  43.619 8.784 44.339 10.296 ;
     RECT  43.813 0.288 44.389 7.464 ;
     RECT  44.147 11.472 45.253 15.336 ;
     RECT  44.389 0.192 45.608 7.464 ;
     RECT  44.339 8.784 45.608 9.816 ;
     RECT  45.253 11.472 45.608 16.008 ;
     RECT  45.608 0.192 45.904 16.008 ;
     RECT  45.904 10.848 45.965 16.008 ;
     RECT  45.904 0.192 46.115 9.816 ;
     RECT  46.115 0.192 46.541 9.576 ;
     RECT  45.965 10.848 46.621 15.432 ;
     RECT  46.621 11.616 46.829 15.432 ;
     RECT  46.829 11.664 46.835 15.432 ;
     RECT  46.541 8.976 47.357 9.576 ;
     RECT  46.541 0.192 47.645 7.992 ;
     RECT  47.357 8.976 47.645 9.672 ;
     RECT  46.835 11.664 47.941 15.336 ;
     RECT  47.941 11.664 48.161 15.432 ;
     RECT  47.645 0.192 48.308 9.672 ;
     RECT  48.161 11.664 48.308 15.336 ;
     RECT  48.308 0.192 48.604 15.336 ;
     RECT  48.604 11.664 48.989 15.336 ;
     RECT  48.989 11.712 49.285 15.336 ;
     RECT  48.604 0.192 49.331 7.992 ;
     RECT  49.285 11.712 49.372 16.008 ;
     RECT  49.331 0.288 49.709 7.992 ;
     RECT  49.709 1.392 49.741 7.992 ;
     RECT  49.709 0.288 49.763 0.312 ;
     RECT  49.597 10.656 50.165 10.68 ;
     RECT  50.165 9.696 50.173 10.68 ;
     RECT  49.372 11.712 50.173 15.384 ;
     RECT  49.741 1.392 50.197 8.52 ;
     RECT  50.197 1.392 51.008 8.712 ;
     RECT  50.173 9.696 51.008 15.384 ;
     RECT  50.821 0.192 51.109 0.216 ;
     RECT  51.008 1.392 51.109 15.384 ;
     RECT  51.109 0.192 51.397 15.384 ;
     RECT  51.397 0.192 51.827 16.008 ;
     RECT  51.827 0.288 52.265 16.008 ;
     RECT  52.265 0.288 52.829 15.336 ;
     RECT  52.829 0.192 53.468 15.336 ;
     RECT  53.468 0.144 54.529 15.336 ;
     RECT  54.529 0.144 55.045 16.008 ;
     RECT  55.045 0.144 55.139 16.584 ;
     RECT  55.139 7.728 55.325 16.584 ;
     RECT  55.325 7.92 55.505 16.584 ;
     RECT  55.139 0.144 55.523 6.744 ;
     RECT  55.505 8.736 55.685 16.584 ;
     RECT  55.685 9.216 55.763 16.584 ;
     RECT  55.523 1.824 55.859 6.744 ;
     RECT  55.763 9.552 55.859 16.584 ;
     RECT  55.859 16.56 55.909 16.584 ;
     RECT  55.859 9.552 55.973 15.336 ;
     RECT  55.973 9.84 56.003 15.336 ;
     RECT  55.523 0.144 56.051 0.216 ;
     RECT  56.003 9.84 56.051 10.776 ;
     RECT  55.909 16.56 56.051 16.68 ;
     RECT  56.051 10.656 56.081 10.776 ;
     RECT  55.859 1.824 56.099 6.312 ;
     RECT  56.003 11.76 56.099 15.336 ;
     RECT  56.051 16.56 56.117 16.584 ;
     RECT  56.051 0.192 56.153 0.216 ;
     RECT  56.081 10.752 56.189 10.776 ;
     RECT  56.099 1.92 56.483 6.312 ;
     RECT  56.099 11.952 56.483 15.336 ;
     RECT  56.483 15.312 56.579 15.336 ;
     RECT  56.483 1.92 57.053 6.072 ;
     RECT  57.053 1.92 57.089 2.616 ;
     RECT  57.053 3.6 57.089 6.072 ;
     RECT  57.089 1.92 57.107 2.328 ;
     RECT  56.483 11.952 57.157 14.232 ;
     RECT  57.089 5.136 57.161 6.072 ;
     RECT  57.089 3.6 57.203 4.008 ;
     RECT  57.157 11.904 57.203 14.232 ;
     RECT  57.161 5.136 57.251 5.976 ;
     RECT  57.203 13.536 57.251 14.232 ;
     RECT  57.107 2.304 57.299 2.328 ;
     RECT  57.251 14.208 57.299 14.232 ;
     RECT  57.203 3.6 57.629 3.624 ;
     RECT  57.251 5.424 57.665 5.976 ;
     RECT  57.665 5.424 58.14 5.448 ;
     RECT  57.203 11.904 58.14 11.928 ;
    LAYER M5 ;
     RECT  18.144 0.133 18.168 0.144 ;
     RECT  22.176 0.133 22.2 0.144 ;
     RECT  53.52 0.133 56.04 0.144 ;
     RECT  2.304 0.144 56.136 0.227 ;
     RECT  2.304 0.227 56.04 1.813 ;
     RECT  2.304 1.813 56.088 2.053 ;
     RECT  57.072 1.909 57.096 2.053 ;
     RECT  2.304 2.053 57.096 2.293 ;
     RECT  2.304 2.293 57.288 4.019 ;
     RECT  2.4 4.019 57.288 5.795 ;
     RECT  2.4 5.795 2.712 8.485 ;
     RECT  3.696 5.795 57.288 8.485 ;
     RECT  2.4 8.485 57.288 9.683 ;
     RECT  2.4 9.683 35.208 11.413 ;
     RECT  36.288 9.683 57.288 11.413 ;
     RECT  2.4 11.413 57.288 12.035 ;
     RECT  7.2 12.035 57.288 12.563 ;
     RECT  2.4 12.035 6.168 13.715 ;
     RECT  7.2 12.563 48.612 13.715 ;
     RECT  49.68 12.563 57.288 13.715 ;
     RECT  49.68 13.715 54.984 13.859 ;
     RECT  56.016 13.715 57.288 14.243 ;
     RECT  2.4 13.715 6.024 14.821 ;
     RECT  7.2 13.715 19.272 14.821 ;
     RECT  20.4 13.715 48.612 14.821 ;
     RECT  49.68 13.859 54.012 14.821 ;
     RECT  56.016 14.243 56.568 14.821 ;
     RECT  2.4 14.821 56.568 15.143 ;
     RECT  2.688 15.143 56.568 15.347 ;
     RECT  2.688 15.347 56.04 16.549 ;
     RECT  2.304 16.549 56.04 17.104 ;
  END
END dsfd_dvrlyh_562_SN
END LIBRARY
